VERSION 5.8 ;
BUSBITCHARS "[]" ;
DIVIDERCHAR "/" ;
UNITS
    DATABASE MICRONS 1000 ;
END UNITS

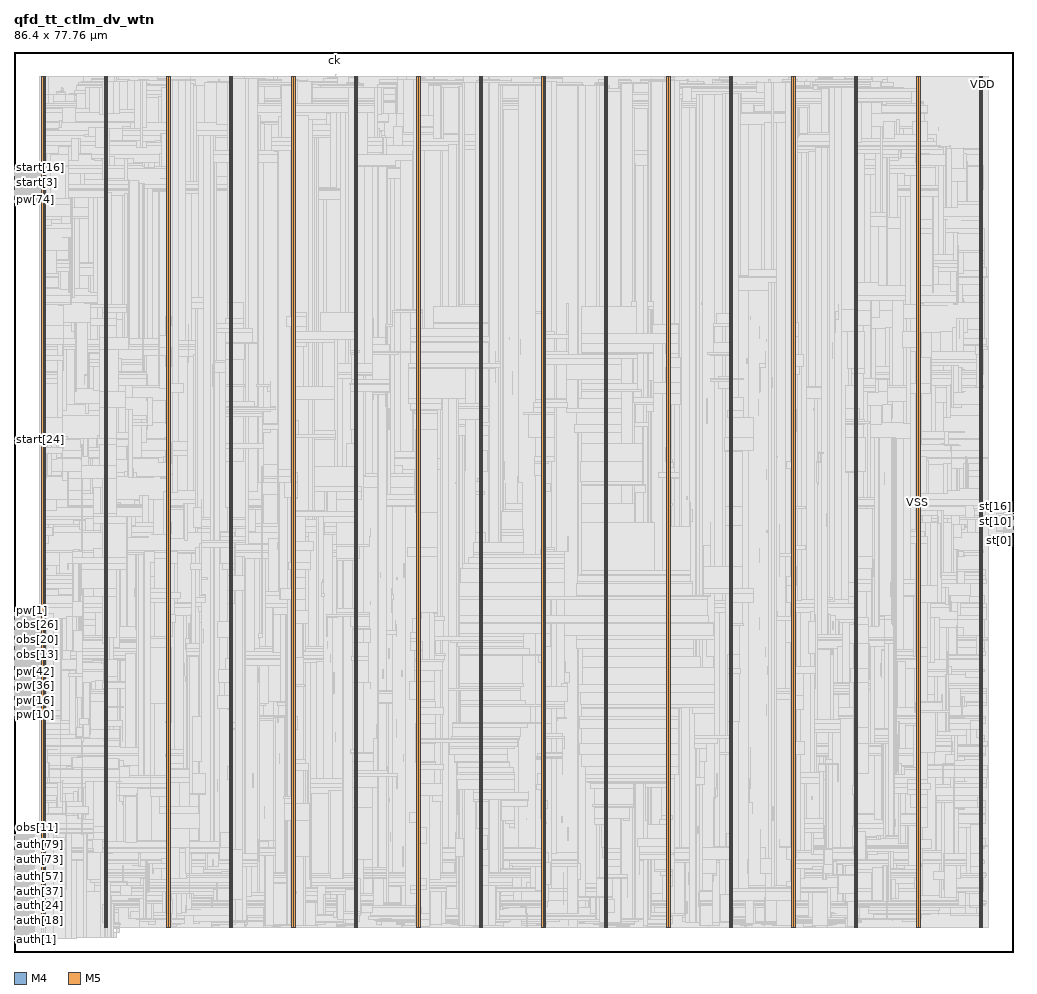
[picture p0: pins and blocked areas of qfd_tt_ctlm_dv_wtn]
MACRO qfd_tt_ctlm_dv_wtn
  FOREIGN qfd_tt_ctlm_dv_wtn 0 0 ;
  CLASS BLOCK ;
  SIZE 86.4 BY 77.76 ;
  PIN auth[0]
    DIRECTION INPUT ;
    USE SIGNAL ;
    PORT
      LAYER M4 ;
        RECT  0 1.008 0.084 1.032 ;
    END
  END auth[0]
  PIN auth[10]
    DIRECTION INPUT ;
    USE SIGNAL ;
    PORT
      LAYER M4 ;
        RECT  0 1.968 0.084 1.992 ;
    END
  END auth[10]
  PIN auth[11]
    DIRECTION INPUT ;
    USE SIGNAL ;
    PORT
      LAYER M4 ;
        RECT  0 2.064 0.084 2.088 ;
    END
  END auth[11]
  PIN auth[12]
    DIRECTION INPUT ;
    USE SIGNAL ;
    PORT
      LAYER M4 ;
        RECT  0 2.16 0.084 2.184 ;
    END
  END auth[12]
  PIN auth[13]
    DIRECTION INPUT ;
    USE SIGNAL ;
    PORT
      LAYER M4 ;
        RECT  0 2.256 0.084 2.28 ;
    END
  END auth[13]
  PIN auth[14]
    DIRECTION INPUT ;
    USE SIGNAL ;
    PORT
      LAYER M4 ;
        RECT  0 2.352 0.084 2.376 ;
    END
  END auth[14]
  PIN auth[15]
    DIRECTION INPUT ;
    USE SIGNAL ;
    PORT
      LAYER M4 ;
        RECT  0 2.448 0.084 2.472 ;
    END
  END auth[15]
  PIN auth[16]
    DIRECTION INPUT ;
    USE SIGNAL ;
    PORT
      LAYER M4 ;
        RECT  0 2.544 0.084 2.568 ;
    END
  END auth[16]
  PIN auth[17]
    DIRECTION INPUT ;
    USE SIGNAL ;
    PORT
      LAYER M4 ;
        RECT  0 2.64 0.084 2.664 ;
    END
  END auth[17]
  PIN auth[18]
    DIRECTION INPUT ;
    USE SIGNAL ;
    PORT
      LAYER M4 ;
        RECT  0 2.736 0.084 2.76 ;
    END
  END auth[18]
  PIN auth[19]
    DIRECTION INPUT ;
    USE SIGNAL ;
    PORT
      LAYER M4 ;
        RECT  0 2.832 0.084 2.856 ;
    END
  END auth[19]
  PIN auth[1]
    DIRECTION INPUT ;
    USE SIGNAL ;
    PORT
      LAYER M4 ;
        RECT  0 1.104 0.084 1.128 ;
    END
  END auth[1]
  PIN auth[20]
    DIRECTION INPUT ;
    USE SIGNAL ;
    PORT
      LAYER M4 ;
        RECT  0 2.928 0.084 2.952 ;
    END
  END auth[20]
  PIN auth[21]
    DIRECTION INPUT ;
    USE SIGNAL ;
    PORT
      LAYER M4 ;
        RECT  0 3.024 0.084 3.048 ;
    END
  END auth[21]
  PIN auth[22]
    DIRECTION INPUT ;
    USE SIGNAL ;
    PORT
      LAYER M4 ;
        RECT  0 3.12 0.084 3.144 ;
    END
  END auth[22]
  PIN auth[23]
    DIRECTION INPUT ;
    USE SIGNAL ;
    PORT
      LAYER M4 ;
        RECT  0 3.216 0.084 3.24 ;
    END
  END auth[23]
  PIN auth[24]
    DIRECTION INPUT ;
    USE SIGNAL ;
    PORT
      LAYER M4 ;
        RECT  0 3.312 0.084 3.336 ;
    END
  END auth[24]
  PIN auth[25]
    DIRECTION INPUT ;
    USE SIGNAL ;
    PORT
      LAYER M4 ;
        RECT  0 3.408 0.084 3.432 ;
    END
  END auth[25]
  PIN auth[26]
    DIRECTION INPUT ;
    USE SIGNAL ;
    PORT
      LAYER M4 ;
        RECT  0 3.504 0.084 3.528 ;
    END
  END auth[26]
  PIN auth[27]
    DIRECTION INPUT ;
    USE SIGNAL ;
    PORT
      LAYER M4 ;
        RECT  0 3.6 0.084 3.624 ;
    END
  END auth[27]
  PIN auth[28]
    DIRECTION INPUT ;
    USE SIGNAL ;
    PORT
      LAYER M4 ;
        RECT  0 3.696 0.084 3.72 ;
    END
  END auth[28]
  PIN auth[29]
    DIRECTION INPUT ;
    USE SIGNAL ;
    PORT
      LAYER M4 ;
        RECT  0 3.792 0.084 3.816 ;
    END
  END auth[29]
  PIN auth[2]
    DIRECTION INPUT ;
    USE SIGNAL ;
    PORT
      LAYER M4 ;
        RECT  0 1.2 0.084 1.224 ;
    END
  END auth[2]
  PIN auth[30]
    DIRECTION INPUT ;
    USE SIGNAL ;
    PORT
      LAYER M4 ;
        RECT  0 3.888 0.084 3.912 ;
    END
  END auth[30]
  PIN auth[31]
    DIRECTION INPUT ;
    USE SIGNAL ;
    PORT
      LAYER M4 ;
        RECT  0 3.984 0.084 4.008 ;
    END
  END auth[31]
  PIN auth[32]
    DIRECTION INPUT ;
    USE SIGNAL ;
    PORT
      LAYER M4 ;
        RECT  0 4.08 0.084 4.104 ;
    END
  END auth[32]
  PIN auth[33]
    DIRECTION INPUT ;
    USE SIGNAL ;
    PORT
      LAYER M4 ;
        RECT  0 4.176 0.084 4.2 ;
    END
  END auth[33]
  PIN auth[34]
    DIRECTION INPUT ;
    USE SIGNAL ;
    PORT
      LAYER M4 ;
        RECT  0 4.272 0.084 4.296 ;
    END
  END auth[34]
  PIN auth[35]
    DIRECTION INPUT ;
    USE SIGNAL ;
    PORT
      LAYER M4 ;
        RECT  0 4.368 0.084 4.392 ;
    END
  END auth[35]
  PIN auth[36]
    DIRECTION INPUT ;
    USE SIGNAL ;
    PORT
      LAYER M4 ;
        RECT  0 4.464 0.084 4.488 ;
    END
  END auth[36]
  PIN auth[37]
    DIRECTION INPUT ;
    USE SIGNAL ;
    PORT
      LAYER M4 ;
        RECT  0 4.56 0.084 4.584 ;
    END
  END auth[37]
  PIN auth[38]
    DIRECTION INPUT ;
    USE SIGNAL ;
    PORT
      LAYER M4 ;
        RECT  0 4.656 0.084 4.68 ;
    END
  END auth[38]
  PIN auth[39]
    DIRECTION INPUT ;
    USE SIGNAL ;
    PORT
      LAYER M4 ;
        RECT  0 4.752 0.084 4.776 ;
    END
  END auth[39]
  PIN auth[3]
    DIRECTION INPUT ;
    USE SIGNAL ;
    PORT
      LAYER M4 ;
        RECT  0 1.296 0.084 1.32 ;
    END
  END auth[3]
  PIN auth[40]
    DIRECTION INPUT ;
    USE SIGNAL ;
    PORT
      LAYER M4 ;
        RECT  0 4.848 0.084 4.872 ;
    END
  END auth[40]
  PIN auth[41]
    DIRECTION INPUT ;
    USE SIGNAL ;
    PORT
      LAYER M4 ;
        RECT  0 4.944 0.084 4.968 ;
    END
  END auth[41]
  PIN auth[42]
    DIRECTION INPUT ;
    USE SIGNAL ;
    PORT
      LAYER M4 ;
        RECT  0 5.04 0.084 5.064 ;
    END
  END auth[42]
  PIN auth[43]
    DIRECTION INPUT ;
    USE SIGNAL ;
    PORT
      LAYER M4 ;
        RECT  0 5.136 0.084 5.16 ;
    END
  END auth[43]
  PIN auth[44]
    DIRECTION INPUT ;
    USE SIGNAL ;
    PORT
      LAYER M4 ;
        RECT  0 5.232 0.084 5.256 ;
    END
  END auth[44]
  PIN auth[45]
    DIRECTION INPUT ;
    USE SIGNAL ;
    PORT
      LAYER M4 ;
        RECT  0 5.328 0.084 5.352 ;
    END
  END auth[45]
  PIN auth[46]
    DIRECTION INPUT ;
    USE SIGNAL ;
    PORT
      LAYER M4 ;
        RECT  0 5.424 0.084 5.448 ;
    END
  END auth[46]
  PIN auth[47]
    DIRECTION INPUT ;
    USE SIGNAL ;
    PORT
      LAYER M4 ;
        RECT  0 5.52 0.084 5.544 ;
    END
  END auth[47]
  PIN auth[48]
    DIRECTION INPUT ;
    USE SIGNAL ;
    PORT
      LAYER M4 ;
        RECT  0 5.616 0.084 5.64 ;
    END
  END auth[48]
  PIN auth[49]
    DIRECTION INPUT ;
    USE SIGNAL ;
    PORT
      LAYER M4 ;
        RECT  0 5.712 0.084 5.736 ;
    END
  END auth[49]
  PIN auth[4]
    DIRECTION INPUT ;
    USE SIGNAL ;
    PORT
      LAYER M4 ;
        RECT  0 1.392 0.084 1.416 ;
    END
  END auth[4]
  PIN auth[50]
    DIRECTION INPUT ;
    USE SIGNAL ;
    PORT
      LAYER M4 ;
        RECT  0 5.808 0.084 5.832 ;
    END
  END auth[50]
  PIN auth[51]
    DIRECTION INPUT ;
    USE SIGNAL ;
    PORT
      LAYER M4 ;
        RECT  0 5.904 0.084 5.928 ;
    END
  END auth[51]
  PIN auth[52]
    DIRECTION INPUT ;
    USE SIGNAL ;
    PORT
      LAYER M4 ;
        RECT  0 6 0.084 6.024 ;
    END
  END auth[52]
  PIN auth[53]
    DIRECTION INPUT ;
    USE SIGNAL ;
    PORT
      LAYER M4 ;
        RECT  0 6.096 0.084 6.12 ;
    END
  END auth[53]
  PIN auth[54]
    DIRECTION INPUT ;
    USE SIGNAL ;
    PORT
      LAYER M4 ;
        RECT  0 6.192 0.084 6.216 ;
    END
  END auth[54]
  PIN auth[55]
    DIRECTION INPUT ;
    USE SIGNAL ;
    PORT
      LAYER M4 ;
        RECT  0 6.288 0.084 6.312 ;
    END
  END auth[55]
  PIN auth[56]
    DIRECTION INPUT ;
    USE SIGNAL ;
    PORT
      LAYER M4 ;
        RECT  0 6.384 0.084 6.408 ;
    END
  END auth[56]
  PIN auth[57]
    DIRECTION INPUT ;
    USE SIGNAL ;
    PORT
      LAYER M4 ;
        RECT  0 6.48 0.084 6.504 ;
    END
  END auth[57]
  PIN auth[58]
    DIRECTION INPUT ;
    USE SIGNAL ;
    PORT
      LAYER M4 ;
        RECT  0 6.576 0.084 6.6 ;
    END
  END auth[58]
  PIN auth[59]
    DIRECTION INPUT ;
    USE SIGNAL ;
    PORT
      LAYER M4 ;
        RECT  0 6.672 0.084 6.696 ;
    END
  END auth[59]
  PIN auth[5]
    DIRECTION INPUT ;
    USE SIGNAL ;
    PORT
      LAYER M4 ;
        RECT  0 1.488 0.084 1.512 ;
    END
  END auth[5]
  PIN auth[60]
    DIRECTION INPUT ;
    USE SIGNAL ;
    PORT
      LAYER M4 ;
        RECT  0 6.768 0.084 6.792 ;
    END
  END auth[60]
  PIN auth[61]
    DIRECTION INPUT ;
    USE SIGNAL ;
    PORT
      LAYER M4 ;
        RECT  0 6.864 0.084 6.888 ;
    END
  END auth[61]
  PIN auth[62]
    DIRECTION INPUT ;
    USE SIGNAL ;
    PORT
      LAYER M4 ;
        RECT  0 6.96 0.084 6.984 ;
    END
  END auth[62]
  PIN auth[63]
    DIRECTION INPUT ;
    USE SIGNAL ;
    PORT
      LAYER M4 ;
        RECT  0 7.056 0.084 7.08 ;
    END
  END auth[63]
  PIN auth[64]
    DIRECTION INPUT ;
    USE SIGNAL ;
    PORT
      LAYER M4 ;
        RECT  0 7.152 0.084 7.176 ;
    END
  END auth[64]
  PIN auth[65]
    DIRECTION INPUT ;
    USE SIGNAL ;
    PORT
      LAYER M4 ;
        RECT  0 7.248 0.084 7.272 ;
    END
  END auth[65]
  PIN auth[66]
    DIRECTION INPUT ;
    USE SIGNAL ;
    PORT
      LAYER M4 ;
        RECT  0 7.344 0.084 7.368 ;
    END
  END auth[66]
  PIN auth[67]
    DIRECTION INPUT ;
    USE SIGNAL ;
    PORT
      LAYER M4 ;
        RECT  0 7.44 0.084 7.464 ;
    END
  END auth[67]
  PIN auth[68]
    DIRECTION INPUT ;
    USE SIGNAL ;
    PORT
      LAYER M4 ;
        RECT  0 7.536 0.084 7.56 ;
    END
  END auth[68]
  PIN auth[69]
    DIRECTION INPUT ;
    USE SIGNAL ;
    PORT
      LAYER M4 ;
        RECT  0 7.632 0.084 7.656 ;
    END
  END auth[69]
  PIN auth[6]
    DIRECTION INPUT ;
    USE SIGNAL ;
    PORT
      LAYER M4 ;
        RECT  0 1.584 0.084 1.608 ;
    END
  END auth[6]
  PIN auth[70]
    DIRECTION INPUT ;
    USE SIGNAL ;
    PORT
      LAYER M4 ;
        RECT  0 7.728 0.084 7.752 ;
    END
  END auth[70]
  PIN auth[71]
    DIRECTION INPUT ;
    USE SIGNAL ;
    PORT
      LAYER M4 ;
        RECT  0 7.824 0.084 7.848 ;
    END
  END auth[71]
  PIN auth[72]
    DIRECTION INPUT ;
    USE SIGNAL ;
    PORT
      LAYER M4 ;
        RECT  0 7.92 0.084 7.944 ;
    END
  END auth[72]
  PIN auth[73]
    DIRECTION INPUT ;
    USE SIGNAL ;
    PORT
      LAYER M4 ;
        RECT  0 8.016 0.084 8.04 ;
    END
  END auth[73]
  PIN auth[74]
    DIRECTION INPUT ;
    USE SIGNAL ;
    PORT
      LAYER M4 ;
        RECT  0 8.112 0.084 8.136 ;
    END
  END auth[74]
  PIN auth[75]
    DIRECTION INPUT ;
    USE SIGNAL ;
    PORT
      LAYER M4 ;
        RECT  0 8.208 0.084 8.232 ;
    END
  END auth[75]
  PIN auth[76]
    DIRECTION INPUT ;
    USE SIGNAL ;
    PORT
      LAYER M4 ;
        RECT  0 8.304 0.084 8.328 ;
    END
  END auth[76]
  PIN auth[77]
    DIRECTION INPUT ;
    USE SIGNAL ;
    PORT
      LAYER M4 ;
        RECT  0 8.4 0.084 8.424 ;
    END
  END auth[77]
  PIN auth[78]
    DIRECTION INPUT ;
    USE SIGNAL ;
    PORT
      LAYER M4 ;
        RECT  0 8.496 0.084 8.52 ;
    END
  END auth[78]
  PIN auth[79]
    DIRECTION INPUT ;
    USE SIGNAL ;
    PORT
      LAYER M4 ;
        RECT  0 8.592 0.084 8.616 ;
    END
  END auth[79]
  PIN auth[7]
    DIRECTION INPUT ;
    USE SIGNAL ;
    PORT
      LAYER M4 ;
        RECT  0 1.68 0.084 1.704 ;
    END
  END auth[7]
  PIN auth[80]
    DIRECTION INPUT ;
    USE SIGNAL ;
    PORT
      LAYER M4 ;
        RECT  0 8.688 0.084 8.712 ;
    END
  END auth[80]
  PIN auth[81]
    DIRECTION INPUT ;
    USE SIGNAL ;
    PORT
      LAYER M4 ;
        RECT  0 8.784 0.084 8.808 ;
    END
  END auth[81]
  PIN auth[82]
    DIRECTION INPUT ;
    USE SIGNAL ;
    PORT
      LAYER M4 ;
        RECT  0 8.88 0.084 8.904 ;
    END
  END auth[82]
  PIN auth[8]
    DIRECTION INPUT ;
    USE SIGNAL ;
    PORT
      LAYER M4 ;
        RECT  0 1.776 0.084 1.8 ;
    END
  END auth[8]
  PIN auth[9]
    DIRECTION INPUT ;
    USE SIGNAL ;
    PORT
      LAYER M4 ;
        RECT  0 1.872 0.084 1.896 ;
    END
  END auth[9]
  PIN ck
    DIRECTION INPUT ;
    USE SIGNAL ;
    PORT
      LAYER M5 ;
        RECT  27.696 77.676 27.72 77.76 ;
    END
  END ck
  PIN obs[0]
    DIRECTION INPUT ;
    USE SIGNAL ;
    PORT
      LAYER M4 ;
        RECT  0 8.976 0.084 9 ;
    END
  END obs[0]
  PIN obs[10]
    DIRECTION INPUT ;
    USE SIGNAL ;
    PORT
      LAYER M4 ;
        RECT  0 9.936 0.084 9.96 ;
    END
  END obs[10]
  PIN obs[11]
    DIRECTION INPUT ;
    USE SIGNAL ;
    PORT
      LAYER M4 ;
        RECT  0 10.032 0.084 10.056 ;
    END
  END obs[11]
  PIN obs[12]
    DIRECTION INPUT ;
    USE SIGNAL ;
    PORT
      LAYER M4 ;
        RECT  0 10.128 0.084 10.152 ;
    END
  END obs[12]
  PIN obs[13]
    DIRECTION INPUT ;
    USE SIGNAL ;
    PORT
      LAYER M4 ;
        RECT  0 26.352 0.084 26.376 ;
    END
  END obs[13]
  PIN obs[14]
    DIRECTION INPUT ;
    USE SIGNAL ;
    PORT
      LAYER M4 ;
        RECT  0 26.448 0.084 26.472 ;
    END
  END obs[14]
  PIN obs[15]
    DIRECTION INPUT ;
    USE SIGNAL ;
    PORT
      LAYER M4 ;
        RECT  0 26.544 0.084 26.568 ;
    END
  END obs[15]
  PIN obs[16]
    DIRECTION INPUT ;
    USE SIGNAL ;
    PORT
      LAYER M4 ;
        RECT  0 26.64 0.084 26.664 ;
    END
  END obs[16]
  PIN obs[17]
    DIRECTION INPUT ;
    USE SIGNAL ;
    PORT
      LAYER M4 ;
        RECT  0 26.736 0.084 26.76 ;
    END
  END obs[17]
  PIN obs[18]
    DIRECTION INPUT ;
    USE SIGNAL ;
    PORT
      LAYER M4 ;
        RECT  0 26.832 0.084 26.856 ;
    END
  END obs[18]
  PIN obs[19]
    DIRECTION INPUT ;
    USE SIGNAL ;
    PORT
      LAYER M4 ;
        RECT  0 26.928 0.084 26.952 ;
    END
  END obs[19]
  PIN obs[1]
    DIRECTION INPUT ;
    USE SIGNAL ;
    PORT
      LAYER M4 ;
        RECT  0 9.072 0.084 9.096 ;
    END
  END obs[1]
  PIN obs[20]
    DIRECTION INPUT ;
    USE SIGNAL ;
    PORT
      LAYER M4 ;
        RECT  0 27.024 0.084 27.048 ;
    END
  END obs[20]
  PIN obs[21]
    DIRECTION INPUT ;
    USE SIGNAL ;
    PORT
      LAYER M4 ;
        RECT  0 27.12 0.084 27.144 ;
    END
  END obs[21]
  PIN obs[22]
    DIRECTION INPUT ;
    USE SIGNAL ;
    PORT
      LAYER M4 ;
        RECT  0 27.216 0.084 27.24 ;
    END
  END obs[22]
  PIN obs[23]
    DIRECTION INPUT ;
    USE SIGNAL ;
    PORT
      LAYER M4 ;
        RECT  0 27.312 0.084 27.336 ;
    END
  END obs[23]
  PIN obs[24]
    DIRECTION INPUT ;
    USE SIGNAL ;
    PORT
      LAYER M4 ;
        RECT  0 27.408 0.084 27.432 ;
    END
  END obs[24]
  PIN obs[25]
    DIRECTION INPUT ;
    USE SIGNAL ;
    PORT
      LAYER M4 ;
        RECT  0 27.504 0.084 27.528 ;
    END
  END obs[25]
  PIN obs[26]
    DIRECTION INPUT ;
    USE SIGNAL ;
    PORT
      LAYER M4 ;
        RECT  0 27.6 0.084 27.624 ;
    END
  END obs[26]
  PIN obs[27]
    DIRECTION INPUT ;
    USE SIGNAL ;
    PORT
      LAYER M4 ;
        RECT  0 27.696 0.084 27.72 ;
    END
  END obs[27]
  PIN obs[28]
    DIRECTION INPUT ;
    USE SIGNAL ;
    PORT
      LAYER M4 ;
        RECT  0 27.792 0.084 27.816 ;
    END
  END obs[28]
  PIN obs[29]
    DIRECTION INPUT ;
    USE SIGNAL ;
    PORT
      LAYER M4 ;
        RECT  0 27.888 0.084 27.912 ;
    END
  END obs[29]
  PIN obs[2]
    DIRECTION INPUT ;
    USE SIGNAL ;
    PORT
      LAYER M4 ;
        RECT  0 9.168 0.084 9.192 ;
    END
  END obs[2]
  PIN obs[30]
    DIRECTION INPUT ;
    USE SIGNAL ;
    PORT
      LAYER M4 ;
        RECT  0 27.984 0.084 28.008 ;
    END
  END obs[30]
  PIN obs[31]
    DIRECTION INPUT ;
    USE SIGNAL ;
    PORT
      LAYER M4 ;
        RECT  0 28.08 0.084 28.104 ;
    END
  END obs[31]
  PIN obs[32]
    DIRECTION INPUT ;
    USE SIGNAL ;
    PORT
      LAYER M4 ;
        RECT  0 28.176 0.084 28.2 ;
    END
  END obs[32]
  PIN obs[33]
    DIRECTION INPUT ;
    USE SIGNAL ;
    PORT
      LAYER M4 ;
        RECT  0 28.272 0.084 28.296 ;
    END
  END obs[33]
  PIN obs[34]
    DIRECTION INPUT ;
    USE SIGNAL ;
    PORT
      LAYER M4 ;
        RECT  0 28.368 0.084 28.392 ;
    END
  END obs[34]
  PIN obs[35]
    DIRECTION INPUT ;
    USE SIGNAL ;
    PORT
      LAYER M4 ;
        RECT  0 28.464 0.084 28.488 ;
    END
  END obs[35]
  PIN obs[36]
    DIRECTION INPUT ;
    USE SIGNAL ;
    PORT
      LAYER M4 ;
        RECT  0 28.56 0.084 28.584 ;
    END
  END obs[36]
  PIN obs[37]
    DIRECTION INPUT ;
    USE SIGNAL ;
    PORT
      LAYER M4 ;
        RECT  0 28.656 0.084 28.68 ;
    END
  END obs[37]
  PIN obs[3]
    DIRECTION INPUT ;
    USE SIGNAL ;
    PORT
      LAYER M4 ;
        RECT  0 9.264 0.084 9.288 ;
    END
  END obs[3]
  PIN obs[4]
    DIRECTION INPUT ;
    USE SIGNAL ;
    PORT
      LAYER M4 ;
        RECT  0 9.36 0.084 9.384 ;
    END
  END obs[4]
  PIN obs[5]
    DIRECTION INPUT ;
    USE SIGNAL ;
    PORT
      LAYER M4 ;
        RECT  0 9.456 0.084 9.48 ;
    END
  END obs[5]
  PIN obs[6]
    DIRECTION INPUT ;
    USE SIGNAL ;
    PORT
      LAYER M4 ;
        RECT  0 9.552 0.084 9.576 ;
    END
  END obs[6]
  PIN obs[7]
    DIRECTION INPUT ;
    USE SIGNAL ;
    PORT
      LAYER M4 ;
        RECT  0 9.648 0.084 9.672 ;
    END
  END obs[7]
  PIN obs[8]
    DIRECTION INPUT ;
    USE SIGNAL ;
    PORT
      LAYER M4 ;
        RECT  0 9.744 0.084 9.768 ;
    END
  END obs[8]
  PIN obs[9]
    DIRECTION INPUT ;
    USE SIGNAL ;
    PORT
      LAYER M4 ;
        RECT  0 9.84 0.084 9.864 ;
    END
  END obs[9]
  PIN pw[0]
    DIRECTION INPUT ;
    USE SIGNAL ;
    PORT
      LAYER M4 ;
        RECT  0 28.752 0.084 28.776 ;
    END
  END pw[0]
  PIN pw[10]
    DIRECTION INPUT ;
    USE SIGNAL ;
    PORT
      LAYER M4 ;
        RECT  0 20.496 0.084 20.52 ;
    END
  END pw[10]
  PIN pw[11]
    DIRECTION INPUT ;
    USE SIGNAL ;
    PORT
      LAYER M4 ;
        RECT  0 20.592 0.084 20.616 ;
    END
  END pw[11]
  PIN pw[12]
    DIRECTION INPUT ;
    USE SIGNAL ;
    PORT
      LAYER M4 ;
        RECT  0 20.688 0.084 20.712 ;
    END
  END pw[12]
  PIN pw[13]
    DIRECTION INPUT ;
    USE SIGNAL ;
    PORT
      LAYER M4 ;
        RECT  0 20.784 0.084 20.808 ;
    END
  END pw[13]
  PIN pw[14]
    DIRECTION INPUT ;
    USE SIGNAL ;
    PORT
      LAYER M4 ;
        RECT  0 20.88 0.084 20.904 ;
    END
  END pw[14]
  PIN pw[15]
    DIRECTION INPUT ;
    USE SIGNAL ;
    PORT
      LAYER M4 ;
        RECT  0 20.976 0.084 21 ;
    END
  END pw[15]
  PIN pw[16]
    DIRECTION INPUT ;
    USE SIGNAL ;
    PORT
      LAYER M4 ;
        RECT  0 21.072 0.084 21.096 ;
    END
  END pw[16]
  PIN pw[17]
    DIRECTION INPUT ;
    USE SIGNAL ;
    PORT
      LAYER M4 ;
        RECT  0 21.168 0.084 21.192 ;
    END
  END pw[17]
  PIN pw[18]
    DIRECTION INPUT ;
    USE SIGNAL ;
    PORT
      LAYER M4 ;
        RECT  0 21.264 0.084 21.288 ;
    END
  END pw[18]
  PIN pw[19]
    DIRECTION INPUT ;
    USE SIGNAL ;
    PORT
      LAYER M4 ;
        RECT  0 21.36 0.084 21.384 ;
    END
  END pw[19]
  PIN pw[1]
    DIRECTION INPUT ;
    USE SIGNAL ;
    PORT
      LAYER M4 ;
        RECT  0 28.848 0.084 28.872 ;
    END
  END pw[1]
  PIN pw[20]
    DIRECTION INPUT ;
    USE SIGNAL ;
    PORT
      LAYER M4 ;
        RECT  0 21.456 0.084 21.48 ;
    END
  END pw[20]
  PIN pw[21]
    DIRECTION INPUT ;
    USE SIGNAL ;
    PORT
      LAYER M4 ;
        RECT  0 21.552 0.084 21.576 ;
    END
  END pw[21]
  PIN pw[22]
    DIRECTION INPUT ;
    USE SIGNAL ;
    PORT
      LAYER M4 ;
        RECT  0 21.648 0.084 21.672 ;
    END
  END pw[22]
  PIN pw[23]
    DIRECTION INPUT ;
    USE SIGNAL ;
    PORT
      LAYER M4 ;
        RECT  0 21.744 0.084 21.768 ;
    END
  END pw[23]
  PIN pw[24]
    DIRECTION INPUT ;
    USE SIGNAL ;
    PORT
      LAYER M4 ;
        RECT  0 21.84 0.084 21.864 ;
    END
  END pw[24]
  PIN pw[25]
    DIRECTION INPUT ;
    USE SIGNAL ;
    PORT
      LAYER M4 ;
        RECT  0 21.936 0.084 21.96 ;
    END
  END pw[25]
  PIN pw[26]
    DIRECTION INPUT ;
    USE SIGNAL ;
    PORT
      LAYER M4 ;
        RECT  0 22.032 0.084 22.056 ;
    END
  END pw[26]
  PIN pw[27]
    DIRECTION INPUT ;
    USE SIGNAL ;
    PORT
      LAYER M4 ;
        RECT  0 22.128 0.084 22.152 ;
    END
  END pw[27]
  PIN pw[28]
    DIRECTION INPUT ;
    USE SIGNAL ;
    PORT
      LAYER M4 ;
        RECT  0 22.224 0.084 22.248 ;
    END
  END pw[28]
  PIN pw[29]
    DIRECTION INPUT ;
    USE SIGNAL ;
    PORT
      LAYER M4 ;
        RECT  0 22.32 0.084 22.344 ;
    END
  END pw[29]
  PIN pw[2]
    DIRECTION INPUT ;
    USE SIGNAL ;
    PORT
      LAYER M4 ;
        RECT  0 28.944 0.084 28.968 ;
    END
  END pw[2]
  PIN pw[30]
    DIRECTION INPUT ;
    USE SIGNAL ;
    PORT
      LAYER M4 ;
        RECT  0 22.416 0.084 22.44 ;
    END
  END pw[30]
  PIN pw[31]
    DIRECTION INPUT ;
    USE SIGNAL ;
    PORT
      LAYER M4 ;
        RECT  0 22.512 0.084 22.536 ;
    END
  END pw[31]
  PIN pw[32]
    DIRECTION INPUT ;
    USE SIGNAL ;
    PORT
      LAYER M4 ;
        RECT  0 22.608 0.084 22.632 ;
    END
  END pw[32]
  PIN pw[33]
    DIRECTION INPUT ;
    USE SIGNAL ;
    PORT
      LAYER M4 ;
        RECT  0 22.704 0.084 22.728 ;
    END
  END pw[33]
  PIN pw[34]
    DIRECTION INPUT ;
    USE SIGNAL ;
    PORT
      LAYER M4 ;
        RECT  0 22.8 0.084 22.824 ;
    END
  END pw[34]
  PIN pw[35]
    DIRECTION INPUT ;
    USE SIGNAL ;
    PORT
      LAYER M4 ;
        RECT  0 22.896 0.084 22.92 ;
    END
  END pw[35]
  PIN pw[36]
    DIRECTION INPUT ;
    USE SIGNAL ;
    PORT
      LAYER M4 ;
        RECT  0 22.992 0.084 23.016 ;
    END
  END pw[36]
  PIN pw[37]
    DIRECTION INPUT ;
    USE SIGNAL ;
    PORT
      LAYER M4 ;
        RECT  0 23.088 0.084 23.112 ;
    END
  END pw[37]
  PIN pw[38]
    DIRECTION INPUT ;
    USE SIGNAL ;
    PORT
      LAYER M4 ;
        RECT  0 23.184 0.084 23.208 ;
    END
  END pw[38]
  PIN pw[39]
    DIRECTION INPUT ;
    USE SIGNAL ;
    PORT
      LAYER M4 ;
        RECT  0 23.28 0.084 23.304 ;
    END
  END pw[39]
  PIN pw[3]
    DIRECTION INPUT ;
    USE SIGNAL ;
    PORT
      LAYER M4 ;
        RECT  0 29.04 0.084 29.064 ;
    END
  END pw[3]
  PIN pw[40]
    DIRECTION INPUT ;
    USE SIGNAL ;
    PORT
      LAYER M4 ;
        RECT  0 23.376 0.084 23.4 ;
    END
  END pw[40]
  PIN pw[41]
    DIRECTION INPUT ;
    USE SIGNAL ;
    PORT
      LAYER M4 ;
        RECT  0 23.472 0.084 23.496 ;
    END
  END pw[41]
  PIN pw[42]
    DIRECTION INPUT ;
    USE SIGNAL ;
    PORT
      LAYER M4 ;
        RECT  0 23.568 0.084 23.592 ;
    END
  END pw[42]
  PIN pw[43]
    DIRECTION INPUT ;
    USE SIGNAL ;
    PORT
      LAYER M4 ;
        RECT  0 23.664 0.084 23.688 ;
    END
  END pw[43]
  PIN pw[44]
    DIRECTION INPUT ;
    USE SIGNAL ;
    PORT
      LAYER M4 ;
        RECT  0 23.76 0.084 23.784 ;
    END
  END pw[44]
  PIN pw[45]
    DIRECTION INPUT ;
    USE SIGNAL ;
    PORT
      LAYER M4 ;
        RECT  0 23.856 0.084 23.88 ;
    END
  END pw[45]
  PIN pw[46]
    DIRECTION INPUT ;
    USE SIGNAL ;
    PORT
      LAYER M4 ;
        RECT  0 23.952 0.084 23.976 ;
    END
  END pw[46]
  PIN pw[47]
    DIRECTION INPUT ;
    USE SIGNAL ;
    PORT
      LAYER M4 ;
        RECT  0 24.048 0.084 24.072 ;
    END
  END pw[47]
  PIN pw[48]
    DIRECTION INPUT ;
    USE SIGNAL ;
    PORT
      LAYER M4 ;
        RECT  0 24.144 0.084 24.168 ;
    END
  END pw[48]
  PIN pw[49]
    DIRECTION INPUT ;
    USE SIGNAL ;
    PORT
      LAYER M4 ;
        RECT  0 24.24 0.084 24.264 ;
    END
  END pw[49]
  PIN pw[4]
    DIRECTION INPUT ;
    USE SIGNAL ;
    PORT
      LAYER M4 ;
        RECT  0 29.136 0.084 29.16 ;
    END
  END pw[4]
  PIN pw[50]
    DIRECTION INPUT ;
    USE SIGNAL ;
    PORT
      LAYER M4 ;
        RECT  0 24.336 0.084 24.36 ;
    END
  END pw[50]
  PIN pw[51]
    DIRECTION INPUT ;
    USE SIGNAL ;
    PORT
      LAYER M4 ;
        RECT  0 24.432 0.084 24.456 ;
    END
  END pw[51]
  PIN pw[52]
    DIRECTION INPUT ;
    USE SIGNAL ;
    PORT
      LAYER M4 ;
        RECT  0 24.528 0.084 24.552 ;
    END
  END pw[52]
  PIN pw[53]
    DIRECTION INPUT ;
    USE SIGNAL ;
    PORT
      LAYER M4 ;
        RECT  0 24.624 0.084 24.648 ;
    END
  END pw[53]
  PIN pw[54]
    DIRECTION INPUT ;
    USE SIGNAL ;
    PORT
      LAYER M4 ;
        RECT  0 24.72 0.084 24.744 ;
    END
  END pw[54]
  PIN pw[55]
    DIRECTION INPUT ;
    USE SIGNAL ;
    PORT
      LAYER M4 ;
        RECT  0 24.816 0.084 24.84 ;
    END
  END pw[55]
  PIN pw[56]
    DIRECTION INPUT ;
    USE SIGNAL ;
    PORT
      LAYER M4 ;
        RECT  0 24.912 0.084 24.936 ;
    END
  END pw[56]
  PIN pw[57]
    DIRECTION INPUT ;
    USE SIGNAL ;
    PORT
      LAYER M4 ;
        RECT  0 25.008 0.084 25.032 ;
    END
  END pw[57]
  PIN pw[58]
    DIRECTION INPUT ;
    USE SIGNAL ;
    PORT
      LAYER M4 ;
        RECT  0 25.104 0.084 25.128 ;
    END
  END pw[58]
  PIN pw[59]
    DIRECTION INPUT ;
    USE SIGNAL ;
    PORT
      LAYER M4 ;
        RECT  0 25.2 0.084 25.224 ;
    END
  END pw[59]
  PIN pw[5]
    DIRECTION INPUT ;
    USE SIGNAL ;
    PORT
      LAYER M4 ;
        RECT  0 29.232 0.084 29.256 ;
    END
  END pw[5]
  PIN pw[60]
    DIRECTION INPUT ;
    USE SIGNAL ;
    PORT
      LAYER M4 ;
        RECT  0 25.296 0.084 25.32 ;
    END
  END pw[60]
  PIN pw[61]
    DIRECTION INPUT ;
    USE SIGNAL ;
    PORT
      LAYER M4 ;
        RECT  0 25.392 0.084 25.416 ;
    END
  END pw[61]
  PIN pw[62]
    DIRECTION INPUT ;
    USE SIGNAL ;
    PORT
      LAYER M4 ;
        RECT  0 25.488 0.084 25.512 ;
    END
  END pw[62]
  PIN pw[63]
    DIRECTION INPUT ;
    USE SIGNAL ;
    PORT
      LAYER M4 ;
        RECT  0 25.584 0.084 25.608 ;
    END
  END pw[63]
  PIN pw[64]
    DIRECTION INPUT ;
    USE SIGNAL ;
    PORT
      LAYER M4 ;
        RECT  0 25.68 0.084 25.704 ;
    END
  END pw[64]
  PIN pw[65]
    DIRECTION INPUT ;
    USE SIGNAL ;
    PORT
      LAYER M4 ;
        RECT  0 25.776 0.084 25.8 ;
    END
  END pw[65]
  PIN pw[66]
    DIRECTION INPUT ;
    USE SIGNAL ;
    PORT
      LAYER M4 ;
        RECT  0 25.872 0.084 25.896 ;
    END
  END pw[66]
  PIN pw[67]
    DIRECTION INPUT ;
    USE SIGNAL ;
    PORT
      LAYER M4 ;
        RECT  0 25.968 0.084 25.992 ;
    END
  END pw[67]
  PIN pw[68]
    DIRECTION INPUT ;
    USE SIGNAL ;
    PORT
      LAYER M4 ;
        RECT  0 26.064 0.084 26.088 ;
    END
  END pw[68]
  PIN pw[69]
    DIRECTION INPUT ;
    USE SIGNAL ;
    PORT
      LAYER M4 ;
        RECT  0 26.16 0.084 26.184 ;
    END
  END pw[69]
  PIN pw[6]
    DIRECTION INPUT ;
    USE SIGNAL ;
    PORT
      LAYER M4 ;
        RECT  0 29.328 0.084 29.352 ;
    END
  END pw[6]
  PIN pw[70]
    DIRECTION INPUT ;
    USE SIGNAL ;
    PORT
      LAYER M4 ;
        RECT  0 26.256 0.084 26.28 ;
    END
  END pw[70]
  PIN pw[71]
    DIRECTION INPUT ;
    USE SIGNAL ;
    PORT
      LAYER M4 ;
        RECT  0 64.752 0.084 64.776 ;
    END
  END pw[71]
  PIN pw[72]
    DIRECTION INPUT ;
    USE SIGNAL ;
    PORT
      LAYER M4 ;
        RECT  0 64.848 0.084 64.872 ;
    END
  END pw[72]
  PIN pw[73]
    DIRECTION INPUT ;
    USE SIGNAL ;
    PORT
      LAYER M4 ;
        RECT  0 64.944 0.084 64.968 ;
    END
  END pw[73]
  PIN pw[74]
    DIRECTION INPUT ;
    USE SIGNAL ;
    PORT
      LAYER M4 ;
        RECT  0 65.04 0.084 65.064 ;
    END
  END pw[74]
  PIN pw[7]
    DIRECTION INPUT ;
    USE SIGNAL ;
    PORT
      LAYER M4 ;
        RECT  0 20.208 0.084 20.232 ;
    END
  END pw[7]
  PIN pw[8]
    DIRECTION INPUT ;
    USE SIGNAL ;
    PORT
      LAYER M4 ;
        RECT  0 20.304 0.084 20.328 ;
    END
  END pw[8]
  PIN pw[9]
    DIRECTION INPUT ;
    USE SIGNAL ;
    PORT
      LAYER M4 ;
        RECT  0 20.4 0.084 20.424 ;
    END
  END pw[9]
  PIN retire[0]
    DIRECTION INPUT ;
    USE SIGNAL ;
    PORT
      LAYER M4 ;
        RECT  0 65.136 0.084 65.16 ;
    END
  END retire[0]
  PIN retire[1]
    DIRECTION INPUT ;
    USE SIGNAL ;
    PORT
      LAYER M4 ;
        RECT  0 65.232 0.084 65.256 ;
    END
  END retire[1]
  PIN retire[2]
    DIRECTION INPUT ;
    USE SIGNAL ;
    PORT
      LAYER M4 ;
        RECT  0 65.328 0.084 65.352 ;
    END
  END retire[2]
  PIN retire[3]
    DIRECTION INPUT ;
    USE SIGNAL ;
    PORT
      LAYER M4 ;
        RECT  0 65.424 0.084 65.448 ;
    END
  END retire[3]
  PIN rst_n
    DIRECTION INPUT ;
    USE SIGNAL ;
    PORT
      LAYER M5 ;
        RECT  27.792 77.676 27.816 77.76 ;
    END
  END rst_n
  PIN st[0]
    DIRECTION OUTPUT ;
    USE SIGNAL ;
    PORT
      LAYER M4 ;
        RECT  86.316 36.24 86.4 36.264 ;
    END
  END st[0]
  PIN st[10]
    DIRECTION OUTPUT ;
    USE SIGNAL ;
    PORT
      LAYER M4 ;
        RECT  86.316 37.2 86.4 37.224 ;
    END
  END st[10]
  PIN st[11]
    DIRECTION OUTPUT ;
    USE SIGNAL ;
    PORT
      LAYER M4 ;
        RECT  86.316 37.296 86.4 37.32 ;
    END
  END st[11]
  PIN st[12]
    DIRECTION OUTPUT ;
    USE SIGNAL ;
    PORT
      LAYER M4 ;
        RECT  86.316 37.392 86.4 37.416 ;
    END
  END st[12]
  PIN st[13]
    DIRECTION OUTPUT ;
    USE SIGNAL ;
    PORT
      LAYER M4 ;
        RECT  86.316 37.488 86.4 37.512 ;
    END
  END st[13]
  PIN st[14]
    DIRECTION OUTPUT ;
    USE SIGNAL ;
    PORT
      LAYER M4 ;
        RECT  86.316 37.584 86.4 37.608 ;
    END
  END st[14]
  PIN st[15]
    DIRECTION OUTPUT ;
    USE SIGNAL ;
    PORT
      LAYER M4 ;
        RECT  86.316 37.68 86.4 37.704 ;
    END
  END st[15]
  PIN st[16]
    DIRECTION OUTPUT ;
    USE SIGNAL ;
    PORT
      LAYER M4 ;
        RECT  86.316 37.776 86.4 37.8 ;
    END
  END st[16]
  PIN st[1]
    DIRECTION OUTPUT ;
    USE SIGNAL ;
    PORT
      LAYER M4 ;
        RECT  86.316 36.336 86.4 36.36 ;
    END
  END st[1]
  PIN st[2]
    DIRECTION OUTPUT ;
    USE SIGNAL ;
    PORT
      LAYER M4 ;
        RECT  86.316 36.432 86.4 36.456 ;
    END
  END st[2]
  PIN st[3]
    DIRECTION OUTPUT ;
    USE SIGNAL ;
    PORT
      LAYER M4 ;
        RECT  86.316 36.528 86.4 36.552 ;
    END
  END st[3]
  PIN st[4]
    DIRECTION OUTPUT ;
    USE SIGNAL ;
    PORT
      LAYER M4 ;
        RECT  86.316 36.624 86.4 36.648 ;
    END
  END st[4]
  PIN st[5]
    DIRECTION OUTPUT ;
    USE SIGNAL ;
    PORT
      LAYER M4 ;
        RECT  86.316 36.72 86.4 36.744 ;
    END
  END st[5]
  PIN st[6]
    DIRECTION OUTPUT ;
    USE SIGNAL ;
    PORT
      LAYER M4 ;
        RECT  86.316 36.816 86.4 36.84 ;
    END
  END st[6]
  PIN st[7]
    DIRECTION OUTPUT ;
    USE SIGNAL ;
    PORT
      LAYER M4 ;
        RECT  86.316 36.912 86.4 36.936 ;
    END
  END st[7]
  PIN st[8]
    DIRECTION OUTPUT ;
    USE SIGNAL ;
    PORT
      LAYER M4 ;
        RECT  86.316 37.008 86.4 37.032 ;
    END
  END st[8]
  PIN st[9]
    DIRECTION OUTPUT ;
    USE SIGNAL ;
    PORT
      LAYER M4 ;
        RECT  86.316 37.104 86.4 37.128 ;
    END
  END st[9]
  PIN start[0]
    DIRECTION INPUT ;
    USE SIGNAL ;
    PORT
      LAYER M4 ;
        RECT  0 65.52 0.084 65.544 ;
    END
  END start[0]
  PIN start[10]
    DIRECTION INPUT ;
    USE SIGNAL ;
    PORT
      LAYER M4 ;
        RECT  0 66.48 0.084 66.504 ;
    END
  END start[10]
  PIN start[11]
    DIRECTION INPUT ;
    USE SIGNAL ;
    PORT
      LAYER M4 ;
        RECT  0 66.576 0.084 66.6 ;
    END
  END start[11]
  PIN start[12]
    DIRECTION INPUT ;
    USE SIGNAL ;
    PORT
      LAYER M4 ;
        RECT  0 66.672 0.084 66.696 ;
    END
  END start[12]
  PIN start[13]
    DIRECTION INPUT ;
    USE SIGNAL ;
    PORT
      LAYER M4 ;
        RECT  0 66.768 0.084 66.792 ;
    END
  END start[13]
  PIN start[14]
    DIRECTION INPUT ;
    USE SIGNAL ;
    PORT
      LAYER M4 ;
        RECT  0 66.864 0.084 66.888 ;
    END
  END start[14]
  PIN start[15]
    DIRECTION INPUT ;
    USE SIGNAL ;
    PORT
      LAYER M4 ;
        RECT  0 66.96 0.084 66.984 ;
    END
  END start[15]
  PIN start[16]
    DIRECTION INPUT ;
    USE SIGNAL ;
    PORT
      LAYER M4 ;
        RECT  0 67.056 0.084 67.08 ;
    END
  END start[16]
  PIN start[17]
    DIRECTION INPUT ;
    USE SIGNAL ;
    PORT
      LAYER M4 ;
        RECT  0 67.152 0.084 67.176 ;
    END
  END start[17]
  PIN start[18]
    DIRECTION INPUT ;
    USE SIGNAL ;
    PORT
      LAYER M4 ;
        RECT  0 67.248 0.084 67.272 ;
    END
  END start[18]
  PIN start[19]
    DIRECTION INPUT ;
    USE SIGNAL ;
    PORT
      LAYER M4 ;
        RECT  0 67.344 0.084 67.368 ;
    END
  END start[19]
  PIN start[1]
    DIRECTION INPUT ;
    USE SIGNAL ;
    PORT
      LAYER M4 ;
        RECT  0 65.616 0.084 65.64 ;
    END
  END start[1]
  PIN start[20]
    DIRECTION INPUT ;
    USE SIGNAL ;
    PORT
      LAYER M4 ;
        RECT  0 67.44 0.084 67.464 ;
    END
  END start[20]
  PIN start[21]
    DIRECTION INPUT ;
    USE SIGNAL ;
    PORT
      LAYER M4 ;
        RECT  0 67.536 0.084 67.56 ;
    END
  END start[21]
  PIN start[22]
    DIRECTION INPUT ;
    USE SIGNAL ;
    PORT
      LAYER M4 ;
        RECT  0 67.632 0.084 67.656 ;
    END
  END start[22]
  PIN start[23]
    DIRECTION INPUT ;
    USE SIGNAL ;
    PORT
      LAYER M4 ;
        RECT  0 67.728 0.084 67.752 ;
    END
  END start[23]
  PIN start[24]
    DIRECTION INPUT ;
    USE SIGNAL ;
    PORT
      LAYER M4 ;
        RECT  0 44.304 0.084 44.328 ;
    END
    PORT
      LAYER M4 ;
        RECT  0.06 44.304 2.408 44.328 ;
    END
  END start[24]
  PIN start[2]
    DIRECTION INPUT ;
    USE SIGNAL ;
    PORT
      LAYER M4 ;
        RECT  0 65.712 0.084 65.736 ;
    END
  END start[2]
  PIN start[3]
    DIRECTION INPUT ;
    USE SIGNAL ;
    PORT
      LAYER M4 ;
        RECT  0 65.808 0.084 65.832 ;
    END
  END start[3]
  PIN start[4]
    DIRECTION INPUT ;
    USE SIGNAL ;
    PORT
      LAYER M4 ;
        RECT  0 65.904 0.084 65.928 ;
    END
  END start[4]
  PIN start[5]
    DIRECTION INPUT ;
    USE SIGNAL ;
    PORT
      LAYER M4 ;
        RECT  0 66 0.084 66.024 ;
    END
  END start[5]
  PIN start[6]
    DIRECTION INPUT ;
    USE SIGNAL ;
    PORT
      LAYER M4 ;
        RECT  0 66.096 0.084 66.12 ;
    END
  END start[6]
  PIN start[7]
    DIRECTION INPUT ;
    USE SIGNAL ;
    PORT
      LAYER M4 ;
        RECT  0 66.192 0.084 66.216 ;
    END
  END start[7]
  PIN start[8]
    DIRECTION INPUT ;
    USE SIGNAL ;
    PORT
      LAYER M4 ;
        RECT  0 66.288 0.084 66.312 ;
    END
  END start[8]
  PIN start[9]
    DIRECTION INPUT ;
    USE SIGNAL ;
    PORT
      LAYER M4 ;
        RECT  0 66.384 0.084 66.408 ;
    END
  END start[9]
  PIN VDD
    DIRECTION INOUT ;
    USE POWER ;
    PORT
      LAYER M5 ;
        RECT  83.592 2.151 83.712 75.609 ;
        RECT  78.192 2.151 78.312 75.609 ;
        RECT  72.792 2.151 72.912 75.609 ;
        RECT  67.392 2.151 67.512 75.609 ;
        RECT  61.992 2.151 62.112 75.609 ;
        RECT  56.592 2.151 56.712 75.609 ;
        RECT  51.192 2.151 51.312 75.609 ;
        RECT  45.792 2.151 45.912 75.609 ;
        RECT  40.392 2.151 40.512 75.609 ;
        RECT  34.992 2.151 35.112 75.609 ;
        RECT  29.592 2.151 29.712 75.609 ;
        RECT  24.192 2.151 24.312 75.609 ;
        RECT  18.792 2.151 18.912 75.609 ;
        RECT  13.392 2.151 13.512 75.609 ;
        RECT  7.992 2.151 8.112 75.609 ;
        RECT  2.592 2.151 2.712 75.609 ;
    END
  END VDD
  PIN VSS
    DIRECTION INOUT ;
    USE GROUND ;
    PORT
      LAYER M5 ;
        RECT  83.4 2.137 83.52 75.623 ;
        RECT  78 2.137 78.12 75.623 ;
        RECT  72.6 2.137 72.72 75.623 ;
        RECT  67.2 2.137 67.32 75.623 ;
        RECT  61.8 2.137 61.92 75.623 ;
        RECT  56.4 2.137 56.52 75.623 ;
        RECT  51 2.137 51.12 75.623 ;
        RECT  45.6 2.137 45.72 75.623 ;
        RECT  40.2 2.137 40.32 75.623 ;
        RECT  34.8 2.137 34.92 75.623 ;
        RECT  29.4 2.137 29.52 75.623 ;
        RECT  24 2.137 24.12 75.623 ;
        RECT  18.6 2.137 18.72 75.623 ;
        RECT  13.2 2.137 13.32 75.623 ;
        RECT  7.8 2.137 7.92 75.623 ;
        RECT  2.4 2.137 2.52 75.623 ;
    END
  END VSS
  # OT_OBS_CLOSED layer=M5 d_um=1.536 added=723
  OBS
    LAYER RVTN ;
     RECT  2.16 2.16 84.24 2.295 ;
     RECT  2.16 2.565 84.24 2.835 ;
     RECT  2.16 3.105 84.24 3.375 ;
     RECT  2.16 3.645 84.24 3.915 ;
     RECT  2.16 4.185 84.24 4.455 ;
     RECT  2.16 4.725 84.24 4.995 ;
     RECT  2.16 5.265 84.24 5.535 ;
     RECT  2.16 5.805 84.24 6.075 ;
     RECT  2.16 6.345 84.24 6.615 ;
     RECT  2.16 6.885 84.24 7.155 ;
     RECT  2.16 7.425 84.24 7.695 ;
     RECT  2.16 7.965 84.24 8.235 ;
     RECT  2.16 8.505 84.24 8.775 ;
     RECT  2.16 9.045 84.24 9.315 ;
     RECT  2.16 9.585 84.24 9.855 ;
     RECT  2.16 10.125 84.24 10.395 ;
     RECT  2.16 10.665 84.24 10.935 ;
     RECT  2.16 11.205 84.24 11.475 ;
     RECT  2.16 11.745 84.24 12.015 ;
     RECT  2.16 12.285 84.24 12.555 ;
     RECT  2.16 12.825 84.24 13.095 ;
     RECT  2.16 13.365 84.24 13.635 ;
     RECT  2.16 13.905 84.24 14.175 ;
     RECT  2.16 14.445 84.24 14.715 ;
     RECT  2.16 14.985 84.24 15.255 ;
     RECT  2.16 15.525 84.24 15.795 ;
     RECT  2.16 16.065 84.24 16.335 ;
     RECT  2.16 16.605 84.24 16.875 ;
     RECT  2.16 17.145 84.24 17.415 ;
     RECT  2.16 17.685 84.24 17.955 ;
     RECT  2.16 18.225 84.24 18.495 ;
     RECT  2.16 18.765 84.24 19.035 ;
     RECT  2.16 19.305 84.24 19.575 ;
     RECT  2.16 19.845 84.24 20.115 ;
     RECT  2.16 20.385 84.24 20.655 ;
     RECT  2.16 20.925 84.24 21.195 ;
     RECT  2.16 21.465 84.24 21.735 ;
     RECT  2.16 22.005 84.24 22.275 ;
     RECT  2.16 22.545 84.24 22.815 ;
     RECT  2.16 23.085 84.24 23.355 ;
     RECT  2.16 23.625 84.24 23.895 ;
     RECT  2.16 24.165 84.24 24.435 ;
     RECT  2.16 24.705 84.24 24.975 ;
     RECT  2.16 25.245 84.24 25.515 ;
     RECT  2.16 25.785 84.24 26.055 ;
     RECT  2.16 26.325 84.24 26.595 ;
     RECT  2.16 26.865 84.24 27.135 ;
     RECT  2.16 27.405 84.24 27.675 ;
     RECT  2.16 27.945 84.24 28.215 ;
     RECT  2.16 28.485 84.24 28.755 ;
     RECT  2.16 29.025 84.24 29.295 ;
     RECT  2.16 29.565 84.24 29.835 ;
     RECT  2.16 30.105 84.24 30.375 ;
     RECT  2.16 30.645 84.24 30.915 ;
     RECT  2.16 31.185 84.24 31.455 ;
     RECT  2.16 31.725 84.24 31.995 ;
     RECT  2.16 32.265 84.24 32.535 ;
     RECT  2.16 32.805 84.24 33.075 ;
     RECT  2.16 33.345 84.24 33.615 ;
     RECT  2.16 33.885 84.24 34.155 ;
     RECT  2.16 34.425 84.24 34.695 ;
     RECT  2.16 34.965 84.24 35.235 ;
     RECT  2.16 35.505 84.24 35.775 ;
     RECT  2.16 36.045 84.24 36.315 ;
     RECT  2.16 36.585 84.24 36.855 ;
     RECT  2.16 37.125 84.24 37.395 ;
     RECT  2.16 37.665 84.24 37.935 ;
     RECT  2.16 38.205 84.24 38.475 ;
     RECT  2.16 38.745 84.24 39.015 ;
     RECT  2.16 39.285 84.24 39.555 ;
     RECT  2.16 39.825 84.24 40.095 ;
     RECT  2.16 40.365 84.24 40.635 ;
     RECT  2.16 40.905 84.24 41.175 ;
     RECT  2.16 41.445 84.24 41.715 ;
     RECT  2.16 41.985 84.24 42.255 ;
     RECT  2.16 42.525 84.24 42.795 ;
     RECT  2.16 43.065 84.24 43.335 ;
     RECT  2.16 43.605 84.24 43.875 ;
     RECT  2.16 44.145 84.24 44.415 ;
     RECT  2.16 44.685 84.24 44.955 ;
     RECT  2.16 45.225 84.24 45.495 ;
     RECT  2.16 45.765 84.24 46.035 ;
     RECT  2.16 46.305 84.24 46.575 ;
     RECT  2.16 46.845 84.24 47.115 ;
     RECT  2.16 47.385 84.24 47.655 ;
     RECT  2.16 47.925 84.24 48.195 ;
     RECT  2.16 48.465 84.24 48.735 ;
     RECT  2.16 49.005 84.24 49.275 ;
     RECT  2.16 49.545 84.24 49.815 ;
     RECT  2.16 50.085 84.24 50.355 ;
     RECT  2.16 50.625 84.24 50.895 ;
     RECT  2.16 51.165 84.24 51.435 ;
     RECT  2.16 51.705 84.24 51.975 ;
     RECT  2.16 52.245 84.24 52.515 ;
     RECT  2.16 52.785 84.24 53.055 ;
     RECT  2.16 53.325 84.24 53.595 ;
     RECT  2.16 53.865 84.24 54.135 ;
     RECT  2.16 54.405 84.24 54.675 ;
     RECT  2.16 54.945 84.24 55.215 ;
     RECT  2.16 55.485 84.24 55.755 ;
     RECT  2.16 56.025 84.24 56.295 ;
     RECT  2.16 56.565 84.24 56.835 ;
     RECT  2.16 57.105 84.24 57.375 ;
     RECT  2.16 57.645 84.24 57.915 ;
     RECT  2.16 58.185 84.24 58.455 ;
     RECT  2.16 58.725 84.24 58.995 ;
     RECT  2.16 59.265 84.24 59.535 ;
     RECT  2.16 59.805 84.24 60.075 ;
     RECT  2.16 60.345 84.24 60.615 ;
     RECT  2.16 60.885 84.24 61.155 ;
     RECT  2.16 61.425 84.24 61.695 ;
     RECT  2.16 61.965 84.24 62.235 ;
     RECT  2.16 62.505 84.24 62.775 ;
     RECT  2.16 63.045 84.24 63.315 ;
     RECT  2.16 63.585 84.24 63.855 ;
     RECT  2.16 64.125 84.24 64.395 ;
     RECT  2.16 64.665 84.24 64.935 ;
     RECT  2.16 65.205 84.24 65.475 ;
     RECT  2.16 65.745 84.24 66.015 ;
     RECT  2.16 66.285 84.24 66.555 ;
     RECT  2.16 66.825 84.24 67.095 ;
     RECT  2.16 67.365 84.24 67.635 ;
     RECT  2.16 67.905 84.24 68.175 ;
     RECT  2.16 68.445 84.24 68.715 ;
     RECT  2.16 68.985 84.24 69.255 ;
     RECT  2.16 69.525 84.24 69.795 ;
     RECT  2.16 70.065 84.24 70.335 ;
     RECT  2.16 70.605 84.24 70.875 ;
     RECT  2.16 71.145 84.24 71.415 ;
     RECT  2.16 71.685 84.24 71.955 ;
     RECT  2.16 72.225 84.24 72.495 ;
     RECT  2.16 72.765 84.24 73.035 ;
     RECT  2.16 73.305 84.24 73.575 ;
     RECT  2.16 73.845 84.24 74.115 ;
     RECT  2.16 74.385 84.24 74.655 ;
     RECT  2.16 74.925 84.24 75.195 ;
     RECT  2.16 75.465 84.24 75.6 ;
    LAYER RVTP ;
     RECT  2.16 2.295 84.24 2.565 ;
     RECT  2.16 2.835 84.24 3.105 ;
     RECT  2.16 3.375 84.24 3.645 ;
     RECT  2.16 3.915 84.24 4.185 ;
     RECT  2.16 4.455 84.24 4.725 ;
     RECT  2.16 4.995 84.24 5.265 ;
     RECT  2.16 5.535 84.24 5.805 ;
     RECT  2.16 6.075 84.24 6.345 ;
     RECT  2.16 6.615 84.24 6.885 ;
     RECT  2.16 7.155 84.24 7.425 ;
     RECT  2.16 7.695 84.24 7.965 ;
     RECT  2.16 8.235 84.24 8.505 ;
     RECT  2.16 8.775 84.24 9.045 ;
     RECT  2.16 9.315 84.24 9.585 ;
     RECT  2.16 9.855 84.24 10.125 ;
     RECT  2.16 10.395 84.24 10.665 ;
     RECT  2.16 10.935 84.24 11.205 ;
     RECT  2.16 11.475 84.24 11.745 ;
     RECT  2.16 12.015 84.24 12.285 ;
     RECT  2.16 12.555 84.24 12.825 ;
     RECT  2.16 13.095 84.24 13.365 ;
     RECT  2.16 13.635 84.24 13.905 ;
     RECT  2.16 14.175 84.24 14.445 ;
     RECT  2.16 14.715 84.24 14.985 ;
     RECT  2.16 15.255 84.24 15.525 ;
     RECT  2.16 15.795 84.24 16.065 ;
     RECT  2.16 16.335 84.24 16.605 ;
     RECT  2.16 16.875 84.24 17.145 ;
     RECT  2.16 17.415 84.24 17.685 ;
     RECT  2.16 17.955 84.24 18.225 ;
     RECT  2.16 18.495 84.24 18.765 ;
     RECT  2.16 19.035 84.24 19.305 ;
     RECT  2.16 19.575 84.24 19.845 ;
     RECT  2.16 20.115 84.24 20.385 ;
     RECT  2.16 20.655 84.24 20.925 ;
     RECT  2.16 21.195 84.24 21.465 ;
     RECT  2.16 21.735 84.24 22.005 ;
     RECT  2.16 22.275 84.24 22.545 ;
     RECT  2.16 22.815 84.24 23.085 ;
     RECT  2.16 23.355 84.24 23.625 ;
     RECT  2.16 23.895 84.24 24.165 ;
     RECT  2.16 24.435 84.24 24.705 ;
     RECT  2.16 24.975 84.24 25.245 ;
     RECT  2.16 25.515 84.24 25.785 ;
     RECT  2.16 26.055 84.24 26.325 ;
     RECT  2.16 26.595 84.24 26.865 ;
     RECT  2.16 27.135 84.24 27.405 ;
     RECT  2.16 27.675 84.24 27.945 ;
     RECT  2.16 28.215 84.24 28.485 ;
     RECT  2.16 28.755 84.24 29.025 ;
     RECT  2.16 29.295 84.24 29.565 ;
     RECT  2.16 29.835 84.24 30.105 ;
     RECT  2.16 30.375 84.24 30.645 ;
     RECT  2.16 30.915 84.24 31.185 ;
     RECT  2.16 31.455 84.24 31.725 ;
     RECT  2.16 31.995 84.24 32.265 ;
     RECT  2.16 32.535 84.24 32.805 ;
     RECT  2.16 33.075 84.24 33.345 ;
     RECT  2.16 33.615 84.24 33.885 ;
     RECT  2.16 34.155 84.24 34.425 ;
     RECT  2.16 34.695 84.24 34.965 ;
     RECT  2.16 35.235 84.24 35.505 ;
     RECT  2.16 35.775 84.24 36.045 ;
     RECT  2.16 36.315 84.24 36.585 ;
     RECT  2.16 36.855 84.24 37.125 ;
     RECT  2.16 37.395 84.24 37.665 ;
     RECT  2.16 37.935 84.24 38.205 ;
     RECT  2.16 38.475 84.24 38.745 ;
     RECT  2.16 39.015 84.24 39.285 ;
     RECT  2.16 39.555 84.24 39.825 ;
     RECT  2.16 40.095 84.24 40.365 ;
     RECT  2.16 40.635 84.24 40.905 ;
     RECT  2.16 41.175 84.24 41.445 ;
     RECT  2.16 41.715 84.24 41.985 ;
     RECT  2.16 42.255 84.24 42.525 ;
     RECT  2.16 42.795 84.24 43.065 ;
     RECT  2.16 43.335 84.24 43.605 ;
     RECT  2.16 43.875 84.24 44.145 ;
     RECT  2.16 44.415 84.24 44.685 ;
     RECT  2.16 44.955 84.24 45.225 ;
     RECT  2.16 45.495 84.24 45.765 ;
     RECT  2.16 46.035 84.24 46.305 ;
     RECT  2.16 46.575 84.24 46.845 ;
     RECT  2.16 47.115 84.24 47.385 ;
     RECT  2.16 47.655 84.24 47.925 ;
     RECT  2.16 48.195 84.24 48.465 ;
     RECT  2.16 48.735 84.24 49.005 ;
     RECT  2.16 49.275 84.24 49.545 ;
     RECT  2.16 49.815 84.24 50.085 ;
     RECT  2.16 50.355 84.24 50.625 ;
     RECT  2.16 50.895 84.24 51.165 ;
     RECT  2.16 51.435 84.24 51.705 ;
     RECT  2.16 51.975 84.24 52.245 ;
     RECT  2.16 52.515 84.24 52.785 ;
     RECT  2.16 53.055 84.24 53.325 ;
     RECT  2.16 53.595 84.24 53.865 ;
     RECT  2.16 54.135 84.24 54.405 ;
     RECT  2.16 54.675 84.24 54.945 ;
     RECT  2.16 55.215 84.24 55.485 ;
     RECT  2.16 55.755 84.24 56.025 ;
     RECT  2.16 56.295 84.24 56.565 ;
     RECT  2.16 56.835 84.24 57.105 ;
     RECT  2.16 57.375 84.24 57.645 ;
     RECT  2.16 57.915 84.24 58.185 ;
     RECT  2.16 58.455 84.24 58.725 ;
     RECT  2.16 58.995 84.24 59.265 ;
     RECT  2.16 59.535 84.24 59.805 ;
     RECT  2.16 60.075 84.24 60.345 ;
     RECT  2.16 60.615 84.24 60.885 ;
     RECT  2.16 61.155 84.24 61.425 ;
     RECT  2.16 61.695 84.24 61.965 ;
     RECT  2.16 62.235 84.24 62.505 ;
     RECT  2.16 62.775 84.24 63.045 ;
     RECT  2.16 63.315 84.24 63.585 ;
     RECT  2.16 63.855 84.24 64.125 ;
     RECT  2.16 64.395 84.24 64.665 ;
     RECT  2.16 64.935 84.24 65.205 ;
     RECT  2.16 65.475 84.24 65.745 ;
     RECT  2.16 66.015 84.24 66.285 ;
     RECT  2.16 66.555 84.24 66.825 ;
     RECT  2.16 67.095 84.24 67.365 ;
     RECT  2.16 67.635 84.24 67.905 ;
     RECT  2.16 68.175 84.24 68.445 ;
     RECT  2.16 68.715 84.24 68.985 ;
     RECT  2.16 69.255 84.24 69.525 ;
     RECT  2.16 69.795 84.24 70.065 ;
     RECT  2.16 70.335 84.24 70.605 ;
     RECT  2.16 70.875 84.24 71.145 ;
     RECT  2.16 71.415 84.24 71.685 ;
     RECT  2.16 71.955 84.24 72.225 ;
     RECT  2.16 72.495 84.24 72.765 ;
     RECT  2.16 73.035 84.24 73.305 ;
     RECT  2.16 73.575 84.24 73.845 ;
     RECT  2.16 74.115 84.24 74.385 ;
     RECT  2.16 74.655 84.24 74.925 ;
     RECT  2.16 75.195 84.24 75.465 ;
    LAYER M1 ;
     RECT  2.16 2.151 84.24 75.609 ;
    LAYER M2 ;
     RECT  0.103 2.538 0.203 2.556 ;
     RECT  0.103 4.23 0.535 4.248 ;
     RECT  0.175 7.398 0.535 7.416 ;
     RECT  0.103 8.442 0.535 9.108 ;
     RECT  0.535 3.96 0.571 4.248 ;
     RECT  0.535 22.212 0.571 22.806 ;
     RECT  0.571 3.96 1.147 4.824 ;
     RECT  1.147 3.312 1.291 4.824 ;
     RECT  1.291 3.114 1.723 4.824 ;
     RECT  1.723 2.502 1.759 4.824 ;
     RECT  1.759 2.376 2.16 4.824 ;
     RECT  0.535 6.696 2.16 9.108 ;
     RECT  0.571 22.176 2.16 22.806 ;
     RECT  0.535 24.444 2.16 24.462 ;
     RECT  0.535 26.37 2.16 26.388 ;
     RECT  0.535 27.918 2.16 27.936 ;
     RECT  0.103 64.944 2.16 65.538 ;
     RECT  0.535 67.14 2.16 67.158 ;
     RECT  2.16 2.151 2.695 75.609 ;
     RECT  2.695 2.07 3.019 75.609 ;
     RECT  3.019 1.962 6.035 75.609 ;
     RECT  6.035 2.034 8.663 75.609 ;
     RECT  8.663 2.106 8.987 75.609 ;
     RECT  8.987 2.151 19.939 75.609 ;
     RECT  19.939 2.106 22.379 75.609 ;
     RECT  22.379 2.151 84.24 75.609 ;
     RECT  84.24 35.982 85.487 38.124 ;
     RECT  85.487 35.982 85.523 38.034 ;
     RECT  85.523 36.396 86.315 36.414 ;
     RECT  85.523 37.944 86.315 37.962 ;
    LAYER M3 ;
     RECT  1.728 1.003 1.746 1.099 ;
     RECT  1.728 1.099 1.782 1.387 ;
     RECT  5.328 1.195 5.346 1.579 ;
     RECT  8.82 1.291 8.838 1.675 ;
     RECT  2.556 1.771 2.574 1.867 ;
     RECT  2.556 1.867 2.646 1.957 ;
     RECT  5.184 1.579 5.346 1.957 ;
     RECT  8.82 1.675 9.126 2.029 ;
     RECT  8.64 2.029 9.126 2.059 ;
     RECT  4.104 2.029 4.122 2.065 ;
     RECT  5.184 1.957 6.03 2.065 ;
     RECT  2.556 1.957 3.042 2.101 ;
     RECT  7.38 2.029 7.47 2.101 ;
     RECT  1.152 1.387 1.782 2.143 ;
     RECT  2.556 2.101 3.33 2.143 ;
     RECT  7.236 2.101 7.578 2.143 ;
     RECT  8.46 2.059 9.126 2.143 ;
     RECT  7.236 2.143 9.126 2.191 ;
     RECT  13.215 2.143 13.305 2.191 ;
     RECT  22.356 2.101 22.374 2.191 ;
     RECT  45.615 2.143 45.705 2.191 ;
     RECT  56.415 2.143 56.505 2.191 ;
     RECT  27.9 2.191 27.918 2.227 ;
     RECT  40.215 2.143 40.305 2.227 ;
     RECT  51.015 2.143 51.105 2.227 ;
     RECT  52.416 2.191 52.434 2.227 ;
     RECT  55.62 2.191 56.505 2.227 ;
     RECT  68.22 2.191 68.238 2.227 ;
     RECT  71.82 2.191 71.838 2.227 ;
     RECT  72.615 2.143 72.705 2.227 ;
     RECT  68.22 2.227 68.346 2.24 ;
     RECT  69.264 2.227 69.282 2.24 ;
     RECT  26.244 2.191 26.262 2.251 ;
     RECT  34.815 2.143 34.905 2.251 ;
     RECT  42.264 2.227 42.282 2.251 ;
     RECT  45.615 2.191 45.774 2.251 ;
     RECT  67.215 2.143 67.305 2.251 ;
     RECT  4.104 2.065 6.03 2.263 ;
     RECT  17.1 2.227 17.118 2.263 ;
     RECT  27.9 2.227 28.602 2.263 ;
     RECT  29.415 2.143 29.505 2.263 ;
     RECT  38.484 2.227 38.502 2.263 ;
     RECT  50.58 2.227 51.105 2.263 ;
     RECT  52.056 2.227 53.154 2.263 ;
     RECT  60.012 2.191 60.03 2.263 ;
     RECT  65.916 2.251 65.934 2.263 ;
     RECT  67.215 2.251 67.374 2.263 ;
     RECT  70.236 2.227 70.29 2.263 ;
     RECT  19.944 2.101 19.962 2.299 ;
     RECT  21.528 2.101 21.546 2.299 ;
     RECT  22.356 2.191 23.022 2.299 ;
     RECT  24.015 2.143 24.105 2.299 ;
     RECT  25.992 2.251 26.262 2.299 ;
     RECT  38.484 2.263 38.862 2.299 ;
     RECT  59.58 2.263 60.03 2.299 ;
     RECT  63.108 2.227 63.27 2.299 ;
     RECT  66.924 2.263 67.374 2.335 ;
     RECT  35.928 2.251 35.946 2.347 ;
     RECT  7.056 2.191 9.126 2.371 ;
     RECT  13.215 2.191 14.022 2.371 ;
     RECT  17.1 2.263 17.73 2.371 ;
     RECT  18.615 2.143 18.705 2.371 ;
     RECT  19.944 2.299 20.07 2.371 ;
     RECT  25.884 2.299 26.262 2.371 ;
     RECT  31.752 2.299 31.77 2.371 ;
     RECT  33.516 2.227 33.534 2.371 ;
     RECT  34.704 2.251 34.905 2.371 ;
     RECT  35.928 2.347 35.982 2.371 ;
     RECT  36.936 2.299 36.954 2.371 ;
     RECT  38.34 2.299 38.862 2.371 ;
     RECT  39.672 2.227 40.305 2.371 ;
     RECT  45.108 2.251 45.774 2.371 ;
     RECT  47.916 2.263 47.934 2.371 ;
     RECT  50.58 2.263 53.154 2.371 ;
     RECT  62.748 2.299 63.774 2.371 ;
     RECT  64.8 2.263 64.818 2.371 ;
     RECT  65.556 2.263 66.042 2.371 ;
     RECT  66.852 2.335 67.374 2.371 ;
     RECT  70.236 2.263 70.722 2.371 ;
     RECT  21.528 2.299 24.105 2.413 ;
     RECT  24.948 2.251 24.966 2.413 ;
     RECT  27.9 2.263 29.505 2.413 ;
     RECT  33.084 2.371 34.905 2.413 ;
     RECT  54.684 2.227 56.505 2.413 ;
     RECT  61.815 2.143 61.905 2.413 ;
     RECT  62.64 2.371 63.81 2.413 ;
     RECT  64.62 2.371 67.374 2.413 ;
     RECT  71.82 2.227 72.705 2.413 ;
     RECT  78.015 2.143 78.105 2.413 ;
     RECT  83.415 2.143 83.505 2.413 ;
     RECT  61.815 2.413 63.81 2.443 ;
     RECT  64.62 2.413 67.497 2.443 ;
     RECT  13.215 2.371 14.382 2.461 ;
     RECT  43.848 2.251 43.866 2.461 ;
     RECT  45.108 2.371 46.026 2.461 ;
     RECT  48.708 2.227 48.726 2.461 ;
     RECT  50.076 2.371 53.586 2.461 ;
     RECT  54.684 2.413 56.697 2.461 ;
     RECT  61.815 2.443 67.497 2.461 ;
     RECT  68.22 2.24 69.282 2.461 ;
     RECT  7.056 2.371 9.234 2.489 ;
     RECT  1.152 2.143 3.33 2.491 ;
     RECT  4.104 2.263 6.21 2.491 ;
     RECT  35.928 2.371 36.954 2.491 ;
     RECT  37.8 2.371 40.59 2.491 ;
     RECT  16.02 2.461 16.038 2.497 ;
     RECT  33.084 2.413 35.097 2.497 ;
     RECT  35.928 2.491 40.59 2.497 ;
     RECT  48.708 2.461 49.086 2.497 ;
     RECT  49.932 2.461 53.586 2.497 ;
     RECT  70.236 2.371 71.046 2.497 ;
     RECT  71.82 2.413 72.897 2.497 ;
     RECT  7.056 2.489 9.126 2.525 ;
     RECT  7.056 2.525 8.658 2.533 ;
     RECT  25.884 2.371 26.946 2.533 ;
     RECT  27.9 2.413 29.697 2.533 ;
     RECT  41.544 2.251 42.282 2.533 ;
     RECT  59.58 2.299 60.966 2.539 ;
     RECT  17.1 2.371 19.098 2.569 ;
     RECT  19.944 2.371 20.142 2.569 ;
     RECT  33.084 2.497 35.19 2.569 ;
     RECT  35.928 2.497 40.662 2.569 ;
     RECT  61.815 2.461 69.282 2.569 ;
     RECT  70.236 2.497 72.897 2.569 ;
     RECT  1.152 2.491 6.21 2.605 ;
     RECT  6.984 2.533 8.658 2.605 ;
     RECT  21.528 2.413 24.966 2.605 ;
     RECT  31.284 2.371 31.77 2.605 ;
     RECT  33.084 2.569 40.662 2.605 ;
     RECT  48.708 2.497 53.586 2.605 ;
     RECT  58.032 2.533 58.05 2.605 ;
     RECT  59.148 2.539 61.074 2.605 ;
     RECT  1.152 2.605 8.658 2.621 ;
     RECT  10.8 2.227 10.818 2.641 ;
     RECT  11.664 2.371 12.186 2.641 ;
     RECT  15.48 2.497 16.038 2.641 ;
     RECT  17.1 2.569 20.142 2.641 ;
     RECT  20.88 2.605 24.966 2.641 ;
     RECT  25.884 2.533 29.697 2.641 ;
     RECT  41.544 2.533 42.714 2.641 ;
     RECT  43.848 2.461 46.026 2.641 ;
     RECT  46.764 2.605 47.07 2.641 ;
     RECT  58.968 2.605 61.074 2.641 ;
     RECT  61.815 2.569 73.242 2.641 ;
     RECT  76.752 2.605 76.77 2.641 ;
     RECT  78.015 2.413 78.297 2.641 ;
     RECT  2.268 2.621 8.658 2.669 ;
     RECT  31.284 2.605 40.698 2.731 ;
     RECT  58.968 2.641 73.242 2.731 ;
     RECT  0.108 2.524 0.198 2.765 ;
     RECT  31.176 2.731 40.698 2.767 ;
     RECT  41.508 2.641 42.858 2.767 ;
     RECT  58.896 2.731 73.242 2.767 ;
     RECT  58.824 2.767 73.242 2.795 ;
     RECT  10.8 2.641 12.222 2.803 ;
     RECT  31.176 2.767 42.858 2.803 ;
     RECT  43.848 2.641 47.142 2.803 ;
     RECT  47.88 2.371 47.934 2.803 ;
     RECT  48.708 2.605 53.946 2.803 ;
     RECT  75.888 2.731 75.906 2.803 ;
     RECT  10.584 2.803 12.222 2.839 ;
     RECT  13.215 2.461 14.706 2.839 ;
     RECT  30.636 2.803 53.946 2.839 ;
     RECT  54.684 2.461 56.862 2.839 ;
     RECT  10.584 2.839 14.706 2.875 ;
     RECT  74.232 2.767 74.25 2.911 ;
     RECT  75.456 2.803 75.906 2.911 ;
     RECT  76.752 2.641 78.297 2.911 ;
     RECT  57.78 2.605 58.05 3.001 ;
     RECT  58.824 2.795 73.062 3.001 ;
     RECT  30.636 2.839 56.862 3.029 ;
     RECT  1.152 2.621 1.314 3.137 ;
     RECT  30.816 3.029 56.862 3.145 ;
     RECT  57.78 3.001 73.062 3.145 ;
     RECT  9.864 2.875 14.706 3.181 ;
     RECT  15.48 2.641 29.862 3.181 ;
     RECT  80.928 3.145 81.666 3.181 ;
     RECT  83.415 2.413 83.697 3.181 ;
     RECT  74.232 2.911 78.426 3.271 ;
     RECT  74.232 3.271 79.146 3.301 ;
     RECT  79.884 3.271 79.902 3.301 ;
     RECT  74.232 3.301 79.902 3.307 ;
     RECT  1.152 3.137 1.17 3.335 ;
     RECT  80.928 3.181 83.697 3.335 ;
     RECT  2.304 2.669 8.658 3.379 ;
     RECT  2.304 3.379 8.694 3.451 ;
     RECT  0.144 2.765 0.198 3.499 ;
     RECT  73.8 3.307 79.902 3.613 ;
     RECT  2.304 3.451 9.054 3.713 ;
     RECT  6.948 3.713 9.054 3.811 ;
     RECT  9.864 3.181 29.97 3.811 ;
     RECT  0.144 3.499 0.594 3.883 ;
     RECT  30.816 3.145 73.062 3.883 ;
     RECT  73.8 3.613 79.938 3.883 ;
     RECT  80.928 3.335 82.206 3.883 ;
     RECT  6.948 3.811 29.97 3.979 ;
     RECT  30.816 3.883 82.206 3.979 ;
     RECT  83.124 3.335 83.697 3.991 ;
     RECT  6.948 3.979 82.206 4.081 ;
     RECT  83.124 3.991 83.898 4.081 ;
     RECT  6.948 4.081 83.898 4.153 ;
     RECT  0.108 3.883 0.594 4.253 ;
     RECT  6.948 4.153 84.042 4.379 ;
     RECT  6.948 4.379 83.898 4.415 ;
     RECT  0.144 4.253 0.594 4.445 ;
     RECT  0.576 4.445 0.594 4.829 ;
     RECT  6.948 4.415 43.146 4.919 ;
     RECT  2.304 3.713 6.138 5.179 ;
     RECT  6.948 4.919 9.234 5.179 ;
     RECT  2.304 5.179 9.234 5.225 ;
     RECT  10.116 4.919 43.146 5.269 ;
     RECT  43.884 4.415 83.697 5.269 ;
     RECT  2.304 5.225 6.21 5.419 ;
     RECT  10.116 5.269 83.79 5.459 ;
     RECT  10.116 5.459 83.754 5.531 ;
     RECT  2.268 5.419 6.21 5.603 ;
     RECT  6.948 5.225 9.234 5.707 ;
     RECT  10.116 5.531 43.038 5.707 ;
     RECT  2.304 5.603 6.21 5.729 ;
     RECT  6.948 5.707 43.038 5.971 ;
     RECT  2.304 5.729 5.814 5.999 ;
     RECT  0.144 5.899 0.162 6.077 ;
     RECT  2.304 5.999 4.302 6.305 ;
     RECT  6.588 5.971 43.038 6.421 ;
     RECT  43.884 5.531 83.754 6.421 ;
     RECT  5.04 5.999 5.814 6.583 ;
     RECT  6.588 6.421 83.898 6.583 ;
     RECT  5.04 6.583 83.898 6.619 ;
     RECT  5.04 6.619 84.042 6.809 ;
     RECT  3.744 6.305 4.302 6.811 ;
     RECT  5.04 6.809 83.898 6.811 ;
     RECT  3.744 6.811 83.898 6.845 ;
     RECT  0.54 6.691 0.558 6.893 ;
     RECT  2.304 6.305 2.934 7.087 ;
     RECT  3.744 6.845 83.697 7.087 ;
     RECT  0.324 7.051 0.342 7.181 ;
     RECT  0.216 7.195 0.234 7.393 ;
     RECT  0.18 7.393 0.234 7.469 ;
     RECT  2.304 7.087 83.697 7.663 ;
     RECT  2.304 7.663 83.862 7.889 ;
     RECT  2.304 7.889 83.79 8.033 ;
     RECT  0.54 7.933 0.558 8.141 ;
     RECT  0.324 8.395 0.342 8.437 ;
     RECT  0.108 8.437 0.342 8.525 ;
     RECT  2.304 8.033 83.697 8.573 ;
     RECT  2.304 8.573 6.894 8.683 ;
     RECT  2.268 8.683 6.894 8.735 ;
     RECT  7.668 8.573 83.697 8.941 ;
     RECT  2.304 8.735 6.894 8.969 ;
     RECT  7.668 8.941 83.826 9.005 ;
     RECT  22.788 9.005 83.826 9.085 ;
     RECT  0.108 8.525 0.126 9.197 ;
     RECT  22.788 9.085 84.114 9.239 ;
     RECT  7.668 9.005 22.014 9.509 ;
     RECT  2.304 8.969 6.75 9.643 ;
     RECT  2.268 9.643 6.75 9.691 ;
     RECT  7.668 9.509 21.978 9.691 ;
     RECT  22.788 9.239 83.898 9.815 ;
     RECT  2.268 9.691 21.978 9.887 ;
     RECT  0.144 9.739 0.162 9.917 ;
     RECT  22.788 9.815 83.697 9.959 ;
     RECT  2.304 9.887 21.978 10.355 ;
     RECT  2.34 10.355 21.978 10.363 ;
     RECT  22.788 9.959 48.762 10.363 ;
     RECT  2.34 10.363 48.762 10.625 ;
     RECT  2.415 10.625 48.762 10.699 ;
     RECT  49.608 9.959 83.697 10.699 ;
     RECT  2.415 10.699 83.697 11.137 ;
     RECT  2.415 11.137 83.898 11.911 ;
     RECT  2.376 11.911 83.898 11.947 ;
     RECT  2.376 11.947 83.934 12.479 ;
     RECT  2.376 12.479 83.898 13.055 ;
     RECT  2.376 13.055 83.697 13.559 ;
     RECT  2.376 13.559 31.878 14.179 ;
     RECT  32.616 13.559 83.697 14.251 ;
     RECT  2.34 14.179 31.878 14.521 ;
     RECT  32.616 14.251 84.042 14.521 ;
     RECT  2.34 14.521 84.042 15.061 ;
     RECT  2.34 15.061 84.114 15.791 ;
     RECT  2.376 15.791 84.114 16.133 ;
     RECT  2.376 16.133 83.697 16.951 ;
     RECT  2.376 16.951 83.97 17.117 ;
     RECT  2.415 17.117 83.97 17.725 ;
     RECT  2.415 17.725 84.114 17.879 ;
     RECT  22.752 17.879 84.114 18.149 ;
     RECT  2.415 17.879 22.014 18.419 ;
     RECT  22.788 18.149 83.862 18.419 ;
     RECT  22.86 18.419 83.862 18.725 ;
     RECT  2.415 18.419 21.978 19.192 ;
     RECT  22.86 18.725 83.697 19.192 ;
     RECT  2.415 19.192 83.697 19.741 ;
     RECT  2.415 19.741 83.97 20.155 ;
     RECT  2.304 20.155 83.97 20.309 ;
     RECT  2.304 20.309 83.862 20.345 ;
     RECT  2.304 20.345 83.697 20.395 ;
     RECT  2.196 20.395 83.697 20.417 ;
     RECT  2.196 20.417 21.546 20.453 ;
     RECT  2.304 20.453 21.546 21.271 ;
     RECT  22.86 20.417 83.697 21.271 ;
     RECT  2.304 21.271 21.69 21.433 ;
     RECT  2.304 21.433 21.726 21.496 ;
     RECT  22.752 21.271 84.006 21.541 ;
     RECT  0.576 22.171 0.594 22.207 ;
     RECT  0.54 22.207 0.594 22.349 ;
     RECT  2.304 21.496 21.942 22.351 ;
     RECT  22.716 21.541 84.006 22.351 ;
     RECT  2.304 22.351 84.042 22.477 ;
     RECT  2.268 22.477 84.042 22.739 ;
     RECT  2.268 22.739 83.898 22.775 ;
     RECT  0.54 22.349 0.558 22.925 ;
     RECT  2.268 22.775 83.697 23.035 ;
     RECT  1.98 23.035 83.697 23.213 ;
     RECT  0.144 23.947 0.162 24.221 ;
     RECT  2.268 23.213 83.697 24.241 ;
     RECT  2.268 24.241 83.862 24.395 ;
     RECT  0.54 24.439 0.558 24.557 ;
     RECT  2.268 24.395 83.697 25.277 ;
     RECT  4.896 25.277 83.697 25.321 ;
     RECT  4.896 25.321 83.718 25.591 ;
     RECT  2.268 25.277 4.158 25.825 ;
     RECT  2.232 25.825 4.158 25.949 ;
     RECT  4.896 25.591 83.97 25.979 ;
     RECT  2.304 25.949 4.158 26.248 ;
     RECT  4.896 25.979 83.862 26.248 ;
     RECT  0.324 25.675 0.342 26.299 ;
     RECT  0.144 26.299 0.342 26.365 ;
     RECT  0.144 26.365 0.558 26.477 ;
     RECT  0.54 26.477 0.558 26.861 ;
     RECT  2.304 26.248 83.862 26.941 ;
     RECT  2.304 26.941 84.114 27.019 ;
     RECT  1.98 27.019 84.114 27.197 ;
     RECT  2.304 27.197 84.114 27.203 ;
     RECT  0.324 27.787 0.342 27.913 ;
     RECT  0.324 27.913 0.558 27.917 ;
     RECT  0.54 27.917 0.558 28.013 ;
     RECT  2.304 27.203 83.826 28.723 ;
     RECT  2.304 28.723 84.042 29.795 ;
     RECT  2.415 29.795 84.042 30.101 ;
     RECT  2.415 30.101 83.826 30.839 ;
     RECT  2.415 30.839 83.697 31.801 ;
     RECT  2.376 31.801 84.042 32.189 ;
     RECT  2.376 32.189 83.898 32.539 ;
     RECT  2.34 32.539 83.898 33.035 ;
     RECT  2.34 33.035 83.697 34.501 ;
     RECT  2.34 34.501 83.79 34.655 ;
     RECT  85.5 35.977 85.518 36.121 ;
     RECT  2.34 34.655 83.697 36.239 ;
     RECT  2.34 36.239 82.35 36.275 ;
     RECT  85.464 36.121 85.518 36.319 ;
     RECT  86.292 36.391 86.31 36.557 ;
     RECT  80.568 36.275 82.35 36.701 ;
     RECT  2.34 36.275 79.686 36.779 ;
     RECT  80.64 36.701 82.35 36.779 ;
     RECT  79.236 36.779 79.686 37.201 ;
     RECT  84.888 36.319 85.518 37.387 ;
     RECT  2.34 36.779 78.498 37.391 ;
     RECT  81.72 36.779 82.35 37.399 ;
     RECT  83.088 36.239 83.697 37.399 ;
     RECT  79.236 37.201 79.866 37.435 ;
     RECT  80.64 36.779 80.982 37.435 ;
     RECT  81.72 37.399 83.697 37.499 ;
     RECT  2.415 37.391 78.498 37.613 ;
     RECT  2.415 37.613 19.602 37.625 ;
     RECT  83.016 37.499 83.697 37.675 ;
     RECT  20.628 37.613 78.498 37.733 ;
     RECT  73.62 37.733 78.498 37.741 ;
     RECT  79.236 37.435 80.982 37.741 ;
     RECT  81.72 37.499 82.206 37.741 ;
     RECT  84.852 37.387 85.518 37.859 ;
     RECT  86.292 37.579 86.31 37.967 ;
     RECT  85.464 37.859 85.518 38.039 ;
     RECT  83.016 37.675 83.934 38.129 ;
     RECT  85.464 38.039 85.482 38.129 ;
     RECT  83.016 38.129 83.697 38.281 ;
     RECT  2.415 37.625 19.566 38.407 ;
     RECT  2.415 38.407 19.638 38.443 ;
     RECT  20.628 37.733 72.897 38.443 ;
     RECT  2.415 38.443 72.897 38.479 ;
     RECT  73.62 37.741 82.206 38.479 ;
     RECT  2.415 38.479 82.206 38.551 ;
     RECT  82.944 38.281 83.697 38.551 ;
     RECT  2.415 38.551 83.697 39.067 ;
     RECT  2.376 39.067 83.697 39.119 ;
     RECT  2.415 39.119 83.697 41.107 ;
     RECT  2.34 41.107 83.697 42.601 ;
     RECT  2.34 42.601 84.114 42.719 ;
     RECT  2.34 42.719 83.697 43.295 ;
     RECT  2.415 43.295 83.697 44.299 ;
     RECT  2.304 44.299 83.697 44.375 ;
     RECT  2.415 44.375 83.697 46.345 ;
     RECT  2.376 46.345 83.697 48.811 ;
     RECT  2.376 48.811 83.754 48.965 ;
     RECT  2.376 48.965 83.697 49.549 ;
     RECT  2.34 49.549 83.697 49.891 ;
     RECT  2.34 49.891 83.754 50.081 ;
     RECT  2.376 50.081 83.754 50.971 ;
     RECT  2.376 50.971 83.79 51.161 ;
     RECT  2.376 51.161 83.754 52.051 ;
     RECT  2.376 52.051 84.114 52.277 ;
     RECT  2.376 52.277 84.042 52.475 ;
     RECT  2.415 52.475 84.042 52.979 ;
     RECT  2.415 52.979 83.826 56.101 ;
     RECT  2.376 56.101 83.826 56.759 ;
     RECT  2.415 56.759 83.826 58.261 ;
     RECT  2.415 58.261 84.114 58.379 ;
     RECT  2.415 58.379 84.042 59.099 ;
     RECT  2.415 59.099 83.826 59.467 ;
     RECT  2.412 59.467 83.826 59.765 ;
     RECT  2.415 59.765 83.826 60.571 ;
     RECT  2.376 60.571 83.826 62.501 ;
     RECT  2.376 62.501 83.697 63.509 ;
     RECT  2.415 63.509 83.697 64.597 ;
     RECT  0.108 64.939 0.126 65.035 ;
     RECT  0.108 65.035 0.342 65.443 ;
     RECT  0.108 65.443 0.558 65.645 ;
     RECT  0.54 65.645 0.558 65.741 ;
     RECT  2.304 64.597 83.697 65.785 ;
     RECT  2.268 65.785 83.697 65.911 ;
     RECT  2.268 65.911 83.79 65.933 ;
     RECT  2.304 65.933 83.79 66.317 ;
     RECT  0.18 66.907 0.198 66.955 ;
     RECT  0.18 66.955 0.342 67.135 ;
     RECT  0.18 67.135 0.558 67.277 ;
     RECT  0.144 67.435 0.162 67.613 ;
     RECT  2.304 66.317 83.754 67.667 ;
     RECT  2.34 67.667 83.754 67.973 ;
     RECT  2.34 67.973 83.697 68.909 ;
     RECT  2.34 68.909 41.31 68.945 ;
     RECT  42.048 68.909 83.697 69.323 ;
     RECT  81.828 69.323 83.697 69.449 ;
     RECT  82.008 69.449 82.026 69.485 ;
     RECT  42.048 69.323 80.874 69.581 ;
     RECT  2.415 68.945 41.31 69.691 ;
     RECT  42.048 69.581 80.082 69.691 ;
     RECT  2.415 69.691 80.082 69.719 ;
     RECT  80.856 69.581 80.874 69.719 ;
     RECT  2.415 69.719 79.722 69.989 ;
     RECT  2.415 69.989 32.13 70.565 ;
     RECT  32.868 69.989 79.722 70.637 ;
     RECT  32.868 70.637 78.93 70.877 ;
     RECT  32.868 70.877 78.678 70.879 ;
     RECT  2.415 70.565 32.022 70.951 ;
     RECT  79.884 70.951 79.902 71.213 ;
     RECT  32.76 70.879 78.678 71.309 ;
     RECT  2.376 70.951 32.022 71.653 ;
     RECT  2.376 71.653 32.346 71.753 ;
     RECT  33.084 71.309 78.678 72.463 ;
     RECT  2.415 71.753 32.346 72.523 ;
     RECT  33.084 72.463 78.894 72.523 ;
     RECT  2.415 72.523 78.894 72.571 ;
     RECT  2.415 72.571 78.966 73.103 ;
     RECT  2.415 73.103 78.606 73.301 ;
     RECT  3.42 73.301 78.606 73.499 ;
     RECT  5.184 73.499 57.762 73.571 ;
     RECT  58.536 73.499 78.354 73.769 ;
     RECT  5.22 73.571 57.762 74.093 ;
     RECT  3.42 73.499 4.446 74.098 ;
     RECT  16.488 74.093 57.762 74.111 ;
     RECT  16.488 74.111 25.614 74.183 ;
     RECT  3.636 74.098 4.446 74.219 ;
     RECT  3.636 74.219 4.374 74.309 ;
     RECT  3.636 74.309 4.302 74.345 ;
     RECT  58.536 73.769 78.297 74.353 ;
     RECT  16.488 74.183 25.506 74.381 ;
     RECT  3.996 74.345 4.302 74.417 ;
     RECT  4.032 74.417 4.302 74.453 ;
     RECT  5.22 74.093 15.678 74.453 ;
     RECT  4.068 74.453 4.302 74.579 ;
     RECT  26.46 74.111 57.762 74.579 ;
     RECT  58.5 74.353 78.297 74.579 ;
     RECT  30.96 74.579 51.426 74.621 ;
     RECT  58.5 74.579 76.878 74.651 ;
     RECT  39.888 74.621 51.426 74.687 ;
     RECT  52.272 74.579 57.762 74.695 ;
     RECT  58.5 74.651 76.41 74.695 ;
     RECT  4.068 74.579 4.158 74.723 ;
     RECT  39.924 74.687 51.426 74.723 ;
     RECT  52.272 74.695 76.41 74.723 ;
     RECT  52.272 74.723 76.014 74.759 ;
     RECT  50.112 74.723 51.426 74.849 ;
     RECT  5.364 74.453 15.678 74.885 ;
     RECT  39.924 74.723 49.338 74.885 ;
     RECT  26.46 74.579 30.222 74.893 ;
     RECT  31.392 74.621 39.114 74.921 ;
     RECT  50.112 74.849 51.297 74.921 ;
     RECT  52.272 74.759 74.178 74.921 ;
     RECT  39.924 74.885 49.194 74.957 ;
     RECT  21.096 74.381 25.506 74.965 ;
     RECT  26.28 74.893 30.222 74.965 ;
     RECT  5.472 74.885 15.678 74.993 ;
     RECT  21.096 74.965 30.222 74.993 ;
     RECT  52.272 74.921 62.406 74.993 ;
     RECT  28.764 74.993 30.222 75.029 ;
     RECT  31.572 74.921 39.114 75.029 ;
     RECT  50.148 74.921 51.297 75.029 ;
     RECT  5.616 74.993 9.99 75.119 ;
     RECT  21.096 74.993 27.918 75.119 ;
     RECT  28.764 75.029 29.826 75.119 ;
     RECT  31.572 75.029 38.898 75.119 ;
     RECT  39.924 74.957 49.086 75.119 ;
     RECT  50.256 75.029 51.297 75.119 ;
     RECT  52.272 74.993 59.634 75.119 ;
     RECT  63.288 74.921 74.178 75.119 ;
     RECT  74.916 74.759 76.014 75.119 ;
     RECT  16.488 74.381 20.358 75.155 ;
     RECT  21.096 75.119 23.166 75.155 ;
     RECT  28.764 75.119 29.754 75.155 ;
     RECT  39.924 75.119 43.254 75.155 ;
     RECT  48.528 75.119 48.546 75.155 ;
     RECT  60.372 74.993 62.406 75.155 ;
     RECT  65.232 75.119 74.178 75.155 ;
     RECT  5.796 75.119 9.99 75.191 ;
     RECT  16.704 75.155 20.358 75.191 ;
     RECT  24.015 75.119 27.918 75.191 ;
     RECT  64.188 75.119 64.206 75.191 ;
     RECT  58.14 75.119 59.526 75.197 ;
     RECT  6.336 75.191 9.99 75.227 ;
     RECT  16.956 75.191 20.358 75.227 ;
     RECT  24.015 75.191 25.866 75.227 ;
     RECT  26.676 75.191 27.918 75.227 ;
     RECT  59.076 75.197 59.31 75.227 ;
     RECT  66.42 75.155 74.178 75.227 ;
     RECT  6.66 75.227 9.99 75.245 ;
     RECT  24.015 75.227 25.65 75.245 ;
     RECT  66.42 75.227 68.49 75.245 ;
     RECT  10.728 74.993 15.678 75.263 ;
     RECT  18.615 75.227 20.358 75.263 ;
     RECT  24.015 75.245 25.398 75.263 ;
     RECT  52.272 75.119 53.334 75.263 ;
     RECT  21.096 75.155 23.094 75.271 ;
     RECT  54.144 75.119 57.294 75.293 ;
     RECT  10.764 75.263 15.678 75.299 ;
     RECT  33.876 75.119 38.826 75.299 ;
     RECT  39.924 75.155 43.002 75.299 ;
     RECT  2.415 73.301 2.697 75.347 ;
     RECT  6.66 75.245 8.097 75.347 ;
     RECT  40.14 75.299 41.958 75.347 ;
     RECT  50.544 75.119 51.297 75.347 ;
     RECT  60.372 75.155 62.097 75.347 ;
     RECT  78.015 74.579 78.297 75.347 ;
     RECT  83.415 69.449 83.697 75.347 ;
     RECT  6.66 75.347 7.974 75.389 ;
     RECT  8.856 75.245 9.99 75.389 ;
     RECT  10.764 75.299 11.646 75.389 ;
     RECT  12.384 75.299 15.678 75.389 ;
     RECT  17.676 75.227 17.766 75.389 ;
     RECT  18.615 75.263 19.854 75.389 ;
     RECT  20.772 75.271 23.094 75.389 ;
     RECT  24.015 75.263 24.57 75.389 ;
     RECT  25.38 75.263 25.398 75.389 ;
     RECT  31.572 75.119 33.138 75.389 ;
     RECT  33.876 75.299 37.422 75.389 ;
     RECT  38.16 75.299 38.826 75.389 ;
     RECT  41.04 75.347 41.958 75.389 ;
     RECT  50.544 75.347 51.105 75.389 ;
     RECT  52.272 75.263 53.226 75.389 ;
     RECT  54.144 75.293 57.042 75.389 ;
     RECT  58.14 75.197 58.302 75.389 ;
     RECT  59.076 75.227 59.094 75.389 ;
     RECT  60.372 75.347 61.974 75.389 ;
     RECT  65.232 75.155 65.394 75.389 ;
     RECT  66.42 75.245 67.698 75.389 ;
     RECT  68.472 75.245 68.49 75.389 ;
     RECT  69.264 75.227 74.178 75.389 ;
     RECT  75.024 75.119 75.474 75.389 ;
     RECT  8.856 75.389 9.126 75.425 ;
     RECT  11.412 75.389 11.43 75.425 ;
     RECT  12.384 75.389 13.878 75.425 ;
     RECT  17.676 75.389 17.694 75.425 ;
     RECT  22.752 75.389 23.094 75.425 ;
     RECT  31.572 75.389 31.59 75.425 ;
     RECT  33.876 75.389 34.002 75.425 ;
     RECT  40.14 75.347 40.305 75.425 ;
     RECT  54.144 75.389 54.162 75.425 ;
     RECT  54.972 75.389 55.098 75.425 ;
     RECT  55.908 75.389 57.042 75.425 ;
     RECT  58.14 75.389 58.158 75.425 ;
     RECT  60.516 75.389 61.974 75.425 ;
     RECT  66.924 75.389 67.554 75.425 ;
     RECT  69.264 75.389 72.846 75.425 ;
     RECT  73.584 75.389 74.142 75.425 ;
     RECT  20.772 75.389 21.726 75.437 ;
     RECT  21.708 75.437 21.726 75.461 ;
     RECT  26.748 75.227 27.918 75.461 ;
     RECT  42.984 75.299 43.002 75.461 ;
     RECT  55.08 75.425 55.098 75.461 ;
     RECT  71.784 75.425 72.846 75.461 ;
     RECT  6.696 75.389 7.974 75.497 ;
     RECT  12.384 75.425 13.374 75.497 ;
     RECT  19.44 75.389 19.458 75.497 ;
     RECT  34.815 75.389 35.514 75.497 ;
     RECT  44.892 75.119 47.394 75.497 ;
     RECT  69.48 75.425 70.686 75.497 ;
     RECT  7.815 75.497 7.974 75.533 ;
     RECT  15.228 75.389 15.246 75.533 ;
     RECT  22.752 75.425 22.77 75.533 ;
     RECT  27.072 75.461 27.918 75.533 ;
     RECT  28.944 75.155 29.754 75.533 ;
     RECT  33.12 75.389 33.138 75.533 ;
     RECT  36.288 75.389 36.306 75.533 ;
     RECT  38.808 75.389 38.826 75.533 ;
     RECT  44.892 75.497 47.358 75.533 ;
     RECT  56.196 75.425 57.042 75.533 ;
     RECT  60.948 75.425 61.974 75.533 ;
     RECT  69.516 75.497 70.686 75.533 ;
     RECT  71.784 75.461 71.802 75.533 ;
     RECT  72.615 75.461 72.846 75.533 ;
     RECT  74.124 75.425 74.142 75.533 ;
     RECT  75.456 75.389 75.474 75.533 ;
     RECT  8.856 75.425 8.874 75.569 ;
     RECT  12.384 75.497 12.402 75.569 ;
     RECT  13.215 75.497 13.374 75.569 ;
     RECT  24.015 75.389 24.174 75.569 ;
     RECT  28.944 75.533 29.505 75.569 ;
     RECT  33.876 75.425 33.894 75.569 ;
     RECT  34.815 75.497 35.478 75.569 ;
     RECT  41.04 75.389 41.058 75.569 ;
     RECT  46.476 75.533 47.358 75.569 ;
     RECT  60.948 75.533 60.966 75.569 ;
     RECT  61.815 75.533 61.974 75.569 ;
     RECT  66.924 75.425 67.305 75.569 ;
     RECT  69.516 75.533 69.534 75.569 ;
     RECT  2.415 75.347 2.505 75.617 ;
     RECT  7.815 75.533 7.905 75.617 ;
     RECT  13.215 75.569 13.305 75.617 ;
     RECT  18.615 75.389 18.705 75.617 ;
     RECT  24.015 75.569 24.105 75.617 ;
     RECT  29.415 75.569 29.505 75.617 ;
     RECT  34.815 75.569 34.905 75.617 ;
     RECT  40.215 75.425 40.305 75.617 ;
     RECT  45.615 75.533 45.705 75.617 ;
     RECT  51.015 75.389 51.105 75.617 ;
     RECT  56.415 75.533 56.505 75.617 ;
     RECT  61.815 75.569 61.905 75.617 ;
     RECT  67.215 75.569 67.305 75.617 ;
     RECT  72.615 75.533 72.705 75.617 ;
     RECT  78.015 75.347 78.105 75.617 ;
     RECT  83.415 75.347 83.505 75.617 ;
     RECT  27.792 75.533 27.81 75.821 ;
    LAYER M4 ;
     RECT  0.084 1.008 1.757 1.032 ;
     RECT  0.06 1.032 1.757 1.104 ;
     RECT  0.084 1.104 1.757 1.128 ;
     RECT  0.06 1.128 1.757 1.2 ;
     RECT  0.084 1.2 1.757 1.224 ;
     RECT  0.06 1.224 1.757 1.296 ;
     RECT  0.084 1.296 1.757 1.32 ;
     RECT  0.06 1.32 1.757 1.392 ;
     RECT  0.084 1.392 1.757 1.416 ;
     RECT  0.06 1.416 1.757 1.488 ;
     RECT  0.084 1.488 1.757 1.512 ;
     RECT  0.06 1.512 1.757 1.584 ;
     RECT  0.084 1.584 1.757 1.608 ;
     RECT  0.06 1.608 1.757 1.68 ;
     RECT  0.084 1.68 1.757 1.704 ;
     RECT  0.06 1.704 1.757 1.776 ;
     RECT  0.084 1.776 1.757 1.8 ;
     RECT  0.06 1.8 1.757 1.872 ;
     RECT  0.084 1.872 1.757 1.896 ;
     RECT  0.06 1.896 1.757 1.968 ;
     RECT  0.084 1.968 1.757 1.992 ;
     RECT  0.06 1.992 1.757 2.064 ;
     RECT  0.084 2.064 1.757 2.088 ;
     RECT  0.06 2.088 1.757 2.16 ;
     RECT  0.084 2.16 1.757 2.184 ;
     RECT  0.06 2.184 1.757 2.256 ;
     RECT  0.084 2.256 1.757 2.28 ;
     RECT  0.06 2.28 1.757 2.352 ;
     RECT  0.084 2.352 1.757 2.376 ;
     RECT  0.06 2.376 1.757 2.448 ;
     RECT  0.084 2.448 1.757 2.472 ;
     RECT  0.06 2.472 1.757 2.544 ;
     RECT  0.084 2.544 1.757 2.568 ;
     RECT  0.06 2.568 1.757 2.64 ;
     RECT  0.084 2.64 1.757 2.664 ;
     RECT  0.06 2.664 1.757 2.736 ;
     RECT  0.084 2.736 1.757 2.76 ;
     RECT  0.06 2.76 1.757 2.832 ;
     RECT  0.084 2.832 1.757 2.856 ;
     RECT  0.06 2.856 1.757 2.928 ;
     RECT  0.084 2.928 1.757 2.952 ;
     RECT  0.06 2.952 1.757 3.024 ;
     RECT  0.084 3.024 1.757 3.048 ;
     RECT  0.06 3.048 1.757 3.12 ;
     RECT  0.084 3.12 1.757 3.144 ;
     RECT  0.06 3.144 1.757 3.216 ;
     RECT  0.084 3.216 1.757 3.24 ;
     RECT  0.06 3.24 1.757 3.312 ;
     RECT  0.084 3.312 1.757 3.336 ;
     RECT  0.06 3.336 1.757 3.408 ;
     RECT  0.084 3.408 1.757 3.432 ;
     RECT  0.06 3.432 1.757 3.504 ;
     RECT  0.084 3.504 1.757 3.528 ;
     RECT  0.06 3.528 1.757 3.6 ;
     RECT  0.084 3.6 1.757 3.624 ;
     RECT  0.06 3.624 1.757 3.696 ;
     RECT  0.084 3.696 1.757 3.72 ;
     RECT  0.06 3.72 1.757 3.792 ;
     RECT  0.084 3.792 1.757 3.816 ;
     RECT  0.06 3.816 1.757 3.888 ;
     RECT  0.084 3.888 1.757 3.912 ;
     RECT  0.06 3.912 1.757 3.984 ;
     RECT  0.084 3.984 1.757 4.008 ;
     RECT  0.06 4.008 1.757 4.08 ;
     RECT  0.084 4.08 1.757 4.104 ;
     RECT  0.06 4.104 1.757 4.176 ;
     RECT  0.084 4.176 1.757 4.2 ;
     RECT  0.06 4.2 1.757 4.272 ;
     RECT  0.084 4.272 1.757 4.296 ;
     RECT  0.06 4.296 1.757 4.368 ;
     RECT  0.084 4.368 1.757 4.392 ;
     RECT  0.06 4.392 1.757 4.464 ;
     RECT  0.084 4.464 1.757 4.488 ;
     RECT  0.06 4.488 1.757 4.56 ;
     RECT  0.084 4.56 1.757 4.584 ;
     RECT  0.06 4.584 1.757 4.656 ;
     RECT  0.084 4.656 1.757 4.68 ;
     RECT  0.06 4.68 1.757 4.752 ;
     RECT  0.084 4.752 1.757 4.776 ;
     RECT  0.06 4.776 1.757 4.848 ;
     RECT  0.084 4.848 1.757 4.872 ;
     RECT  0.06 4.872 1.757 4.944 ;
     RECT  0.084 4.944 1.757 4.968 ;
     RECT  0.06 4.968 1.757 5.04 ;
     RECT  0.084 5.04 1.757 5.064 ;
     RECT  0.06 5.064 1.757 5.136 ;
     RECT  0.084 5.136 1.757 5.16 ;
     RECT  0.06 5.16 1.757 5.232 ;
     RECT  0.084 5.232 1.757 5.256 ;
     RECT  0.06 5.256 1.757 5.328 ;
     RECT  0.084 5.328 1.757 5.352 ;
     RECT  0.06 5.352 1.757 5.424 ;
     RECT  0.084 5.424 1.757 5.448 ;
     RECT  0.06 5.448 1.757 5.52 ;
     RECT  0.084 5.52 1.757 5.544 ;
     RECT  0.06 5.544 1.757 5.616 ;
     RECT  0.084 5.616 1.757 5.64 ;
     RECT  0.06 5.64 1.757 5.712 ;
     RECT  0.084 5.712 1.757 5.736 ;
     RECT  0.06 5.736 1.757 5.808 ;
     RECT  0.084 5.808 1.757 5.832 ;
     RECT  0.06 5.832 1.757 5.904 ;
     RECT  0.084 5.904 1.757 5.928 ;
     RECT  0.06 5.928 1.757 6 ;
     RECT  0.084 6 1.757 6.024 ;
     RECT  0.06 6.024 1.757 6.096 ;
     RECT  0.084 6.096 1.757 6.12 ;
     RECT  0.06 6.12 1.757 6.192 ;
     RECT  0.084 6.192 1.757 6.216 ;
     RECT  0.06 6.216 1.757 6.288 ;
     RECT  0.084 6.288 1.757 6.312 ;
     RECT  0.06 6.312 1.757 6.384 ;
     RECT  0.084 6.384 1.757 6.408 ;
     RECT  0.06 6.408 1.757 6.48 ;
     RECT  0.084 6.48 1.757 6.504 ;
     RECT  0.06 6.504 1.757 6.576 ;
     RECT  0.084 6.576 1.757 6.6 ;
     RECT  0.06 6.6 1.757 6.672 ;
     RECT  0.084 6.672 1.757 6.696 ;
     RECT  0.06 6.696 1.757 6.768 ;
     RECT  0.084 6.768 1.757 6.792 ;
     RECT  0.06 6.792 1.757 6.864 ;
     RECT  0.084 6.864 1.757 6.888 ;
     RECT  0.06 6.888 1.757 6.96 ;
     RECT  0.084 6.96 1.757 6.984 ;
     RECT  0.06 6.984 1.757 7.056 ;
     RECT  0.084 7.056 1.757 7.08 ;
     RECT  0.06 7.08 1.757 7.152 ;
     RECT  0.084 7.152 1.757 7.176 ;
     RECT  0.06 7.176 1.757 7.248 ;
     RECT  0.084 7.248 1.757 7.272 ;
     RECT  0.06 7.272 1.757 7.344 ;
     RECT  0.084 7.344 1.757 7.368 ;
     RECT  0.06 7.368 1.757 7.44 ;
     RECT  0.084 7.44 1.757 7.464 ;
     RECT  0.06 7.464 1.757 7.536 ;
     RECT  0.084 7.536 1.757 7.56 ;
     RECT  0.06 7.56 1.757 7.632 ;
     RECT  0.084 7.632 1.757 7.656 ;
     RECT  0.06 7.656 1.757 7.728 ;
     RECT  0.084 7.728 1.757 7.752 ;
     RECT  0.06 7.752 1.757 7.824 ;
     RECT  0.084 7.824 1.757 7.848 ;
     RECT  0.06 7.848 1.757 7.92 ;
     RECT  0.084 7.92 1.757 7.944 ;
     RECT  0.06 7.944 1.757 8.016 ;
     RECT  0.084 8.016 1.757 8.04 ;
     RECT  0.06 8.04 1.757 8.112 ;
     RECT  0.084 8.112 1.757 8.136 ;
     RECT  0.06 8.136 1.757 8.208 ;
     RECT  0.084 8.208 1.757 8.232 ;
     RECT  0.06 8.232 1.757 8.304 ;
     RECT  0.084 8.304 1.757 8.328 ;
     RECT  0.06 8.328 1.757 8.4 ;
     RECT  0.084 8.4 1.757 8.424 ;
     RECT  0.06 8.424 1.757 8.496 ;
     RECT  0.084 8.496 1.757 8.52 ;
     RECT  0.06 8.52 1.757 8.592 ;
     RECT  0.084 8.592 1.757 8.616 ;
     RECT  0.06 8.616 1.757 8.688 ;
     RECT  0.084 8.688 1.757 8.712 ;
     RECT  0.06 8.712 1.757 8.784 ;
     RECT  0.084 8.784 1.757 8.808 ;
     RECT  0.06 8.808 1.757 8.88 ;
     RECT  0.084 8.88 1.757 8.904 ;
     RECT  0.06 8.904 1.757 8.976 ;
     RECT  0.084 8.976 1.757 9 ;
     RECT  0.06 9 1.757 9.072 ;
     RECT  0.084 9.072 1.757 9.096 ;
     RECT  0.06 9.096 1.757 9.168 ;
     RECT  0.084 9.168 1.757 9.192 ;
     RECT  0.06 9.192 1.757 9.264 ;
     RECT  0.084 9.264 1.757 9.288 ;
     RECT  0.06 9.288 1.757 9.36 ;
     RECT  0.084 9.36 1.757 9.384 ;
     RECT  0.06 9.384 1.757 9.456 ;
     RECT  0.084 9.456 1.757 9.48 ;
     RECT  0.06 9.48 1.757 9.552 ;
     RECT  0.084 9.552 1.757 9.576 ;
     RECT  0.06 9.576 1.757 9.648 ;
     RECT  0.084 9.648 1.757 9.672 ;
     RECT  0.06 9.672 1.757 9.744 ;
     RECT  0.084 9.744 1.757 9.768 ;
     RECT  0.06 9.768 1.757 9.84 ;
     RECT  0.084 9.84 1.757 9.864 ;
     RECT  0.06 9.864 1.757 9.936 ;
     RECT  0.084 9.936 1.757 9.96 ;
     RECT  0.06 9.96 1.757 10.032 ;
     RECT  0.084 10.032 1.757 10.056 ;
     RECT  0.06 10.056 1.757 10.128 ;
     RECT  0.084 10.128 1.757 10.152 ;
     RECT  1.757 1.104 1.793 10.152 ;
     RECT  1.793 1.2 2.408 10.152 ;
     RECT  2.365 11.952 2.408 12.552 ;
     RECT  2.365 14.64 2.408 14.664 ;
     RECT  2.365 16.368 2.408 17.112 ;
     RECT  0.084 20.208 2.408 20.232 ;
     RECT  0.06 20.232 2.408 20.304 ;
     RECT  0.084 20.304 2.408 20.328 ;
     RECT  0.06 20.328 2.408 20.4 ;
     RECT  0.084 20.4 2.408 20.424 ;
     RECT  0.06 20.424 2.408 20.496 ;
     RECT  0.084 20.496 2.408 20.52 ;
     RECT  0.06 20.52 2.408 20.592 ;
     RECT  0.084 20.592 2.408 20.616 ;
     RECT  0.06 20.616 2.408 20.688 ;
     RECT  0.084 20.688 2.408 20.712 ;
     RECT  0.06 20.712 2.408 20.784 ;
     RECT  0.084 20.784 2.408 20.808 ;
     RECT  0.06 20.808 2.408 20.88 ;
     RECT  0.084 20.88 2.408 20.904 ;
     RECT  0.06 20.904 2.408 20.976 ;
     RECT  0.084 20.976 2.408 21 ;
     RECT  0.06 21 2.408 21.072 ;
     RECT  0.084 21.072 2.408 21.096 ;
     RECT  0.06 21.096 2.408 21.168 ;
     RECT  0.084 21.168 2.408 21.192 ;
     RECT  0.06 21.192 2.408 21.264 ;
     RECT  0.084 21.264 2.408 21.288 ;
     RECT  0.06 21.288 2.408 21.36 ;
     RECT  0.084 21.36 2.408 21.384 ;
     RECT  0.06 21.384 2.408 21.456 ;
     RECT  0.084 21.456 2.408 21.48 ;
     RECT  0.06 21.48 2.408 21.552 ;
     RECT  0.084 21.552 2.408 21.576 ;
     RECT  0.06 21.576 2.408 21.648 ;
     RECT  0.084 21.648 2.408 21.672 ;
     RECT  0.06 21.672 2.408 21.744 ;
     RECT  0.084 21.744 2.408 21.768 ;
     RECT  0.06 21.768 2.408 21.84 ;
     RECT  0.084 21.84 2.408 21.864 ;
     RECT  0.06 21.864 2.408 21.936 ;
     RECT  0.084 21.936 2.408 21.96 ;
     RECT  0.06 21.96 2.408 22.032 ;
     RECT  0.084 22.032 2.408 22.056 ;
     RECT  0.06 22.056 2.408 22.128 ;
     RECT  0.084 22.128 2.408 22.152 ;
     RECT  0.06 22.152 2.408 22.224 ;
     RECT  0.084 22.224 2.408 22.248 ;
     RECT  0.06 22.248 2.408 22.32 ;
     RECT  0.084 22.32 2.408 22.344 ;
     RECT  0.06 22.344 2.408 22.416 ;
     RECT  0.084 22.416 2.408 22.44 ;
     RECT  0.06 22.44 2.408 22.512 ;
     RECT  0.084 22.512 2.408 22.536 ;
     RECT  0.06 22.536 2.408 22.608 ;
     RECT  0.084 22.608 2.408 22.632 ;
     RECT  0.06 22.632 2.408 22.704 ;
     RECT  0.084 22.704 2.408 22.728 ;
     RECT  0.06 22.728 2.408 22.8 ;
     RECT  0.084 22.8 2.408 22.824 ;
     RECT  0.06 22.824 2.408 22.896 ;
     RECT  0.084 22.896 2.408 22.92 ;
     RECT  0.06 22.92 2.408 22.992 ;
     RECT  0.084 22.992 2.408 23.016 ;
     RECT  0.06 23.016 2.408 23.088 ;
     RECT  0.084 23.088 2.408 23.112 ;
     RECT  0.06 23.112 2.408 23.184 ;
     RECT  0.084 23.184 2.408 23.208 ;
     RECT  0.06 23.208 2.408 23.28 ;
     RECT  0.084 23.28 2.408 23.304 ;
     RECT  0.06 23.304 2.408 23.376 ;
     RECT  0.084 23.376 2.408 23.4 ;
     RECT  0.06 23.4 2.408 23.472 ;
     RECT  0.084 23.472 2.408 23.496 ;
     RECT  0.06 23.496 2.408 23.568 ;
     RECT  0.084 23.568 2.408 23.592 ;
     RECT  0.06 23.592 2.408 23.664 ;
     RECT  0.084 23.664 2.408 23.688 ;
     RECT  0.06 23.688 2.408 23.76 ;
     RECT  0.084 23.76 2.408 23.784 ;
     RECT  0.06 23.784 2.408 23.856 ;
     RECT  0.084 23.856 2.408 23.88 ;
     RECT  0.06 23.88 2.408 23.952 ;
     RECT  0.084 23.952 2.408 23.976 ;
     RECT  0.06 23.976 2.408 24.048 ;
     RECT  0.084 24.048 2.408 24.072 ;
     RECT  0.06 24.072 2.408 24.144 ;
     RECT  0.084 24.144 2.408 24.168 ;
     RECT  0.06 24.168 2.408 24.24 ;
     RECT  0.084 24.24 2.408 24.264 ;
     RECT  0.06 24.264 2.408 24.336 ;
     RECT  0.084 24.336 2.408 24.36 ;
     RECT  0.06 24.36 2.408 24.432 ;
     RECT  0.084 24.432 2.408 24.456 ;
     RECT  0.06 24.456 2.408 24.528 ;
     RECT  0.084 24.528 2.408 24.552 ;
     RECT  0.06 24.552 2.408 24.624 ;
     RECT  0.084 24.624 2.408 24.648 ;
     RECT  0.06 24.648 2.408 24.72 ;
     RECT  0.084 24.72 2.408 24.744 ;
     RECT  0.06 24.744 2.408 24.816 ;
     RECT  0.084 24.816 2.408 24.84 ;
     RECT  0.06 24.84 2.408 24.912 ;
     RECT  0.084 24.912 2.408 24.936 ;
     RECT  0.06 24.936 2.408 25.008 ;
     RECT  0.084 25.008 2.408 25.032 ;
     RECT  0.06 25.032 2.408 25.104 ;
     RECT  0.084 25.104 2.408 25.128 ;
     RECT  0.06 25.128 2.408 25.2 ;
     RECT  0.084 25.2 2.408 25.224 ;
     RECT  0.06 25.224 2.408 25.296 ;
     RECT  0.084 25.296 2.408 25.32 ;
     RECT  0.06 25.32 2.408 25.392 ;
     RECT  0.084 25.392 2.408 25.416 ;
     RECT  0.06 25.416 2.408 25.488 ;
     RECT  0.084 25.488 2.408 25.512 ;
     RECT  0.06 25.512 2.408 25.584 ;
     RECT  0.084 25.584 2.408 25.608 ;
     RECT  0.06 25.608 2.408 25.68 ;
     RECT  0.084 25.68 2.408 25.704 ;
     RECT  0.06 25.704 2.408 25.776 ;
     RECT  0.084 25.776 2.408 25.8 ;
     RECT  0.06 25.8 2.408 25.872 ;
     RECT  0.084 25.872 2.408 25.896 ;
     RECT  0.06 25.896 2.408 25.968 ;
     RECT  0.084 25.968 2.408 25.992 ;
     RECT  0.06 25.992 2.408 26.064 ;
     RECT  0.084 26.064 2.408 26.088 ;
     RECT  0.06 26.088 2.408 26.16 ;
     RECT  0.084 26.16 2.408 26.184 ;
     RECT  0.06 26.184 2.408 26.256 ;
     RECT  0.084 26.256 2.408 26.28 ;
     RECT  0.06 26.28 2.408 26.352 ;
     RECT  0.084 26.352 2.408 26.376 ;
     RECT  0.06 26.376 2.408 26.448 ;
     RECT  0.084 26.448 2.408 26.472 ;
     RECT  0.06 26.472 2.408 26.544 ;
     RECT  0.084 26.544 2.408 26.568 ;
     RECT  0.06 26.568 2.408 26.64 ;
     RECT  0.084 26.64 2.408 26.664 ;
     RECT  0.06 26.664 2.408 26.736 ;
     RECT  0.084 26.736 2.408 26.76 ;
     RECT  0.06 26.76 2.408 26.832 ;
     RECT  0.084 26.832 2.408 26.856 ;
     RECT  0.06 26.856 2.408 26.928 ;
     RECT  0.084 26.928 2.408 26.952 ;
     RECT  0.06 26.952 2.408 27.024 ;
     RECT  0.084 27.024 2.408 27.048 ;
     RECT  0.06 27.048 2.408 27.12 ;
     RECT  0.084 27.12 2.408 27.144 ;
     RECT  0.06 27.144 2.408 27.216 ;
     RECT  0.084 27.216 2.408 27.24 ;
     RECT  0.06 27.24 2.408 27.312 ;
     RECT  0.084 27.312 2.408 27.336 ;
     RECT  0.06 27.336 2.408 27.408 ;
     RECT  0.084 27.408 2.408 27.432 ;
     RECT  0.06 27.432 2.408 27.504 ;
     RECT  0.084 27.504 2.408 27.528 ;
     RECT  0.06 27.528 2.408 27.6 ;
     RECT  0.084 27.6 2.408 27.624 ;
     RECT  0.06 27.624 2.408 27.696 ;
     RECT  0.084 27.696 2.408 27.72 ;
     RECT  0.06 27.72 2.408 27.792 ;
     RECT  0.084 27.792 2.408 27.816 ;
     RECT  0.06 27.816 2.408 27.888 ;
     RECT  0.084 27.888 2.408 27.912 ;
     RECT  0.06 27.912 2.408 27.984 ;
     RECT  0.084 27.984 2.408 28.008 ;
     RECT  0.06 28.008 2.408 28.08 ;
     RECT  0.084 28.08 2.408 28.104 ;
     RECT  0.06 28.104 2.408 28.176 ;
     RECT  0.084 28.176 2.408 28.2 ;
     RECT  0.06 28.2 2.408 28.272 ;
     RECT  0.084 28.272 2.408 28.296 ;
     RECT  0.06 28.296 2.408 28.368 ;
     RECT  0.084 28.368 2.408 28.392 ;
     RECT  0.06 28.392 2.408 28.464 ;
     RECT  0.084 28.464 2.408 28.488 ;
     RECT  0.06 28.488 2.408 28.56 ;
     RECT  0.084 28.56 2.408 28.584 ;
     RECT  0.06 28.584 2.408 28.656 ;
     RECT  0.084 28.656 2.408 28.68 ;
     RECT  0.06 28.68 2.408 28.752 ;
     RECT  0.084 28.752 2.408 28.776 ;
     RECT  0.06 28.776 2.408 28.848 ;
     RECT  0.084 28.848 2.408 28.872 ;
     RECT  0.06 28.872 2.408 28.944 ;
     RECT  0.084 28.944 2.408 28.968 ;
     RECT  0.06 28.968 2.408 29.04 ;
     RECT  0.084 29.04 2.408 29.064 ;
     RECT  0.06 29.064 2.408 29.136 ;
     RECT  0.084 29.136 2.408 29.16 ;
     RECT  0.06 29.16 2.408 29.232 ;
     RECT  0.084 29.232 2.408 29.256 ;
     RECT  0.06 29.256 2.408 29.328 ;
     RECT  0.084 29.328 2.408 29.352 ;
     RECT  2.365 33.024 2.408 33.048 ;
     RECT  2.365 36 2.408 36.936 ;
     RECT  2.365 39.072 2.408 39.096 ;
     RECT  2.365 41.664 2.408 42.6 ;
     RECT  2.365 46.8 2.408 46.824 ;
     RECT  2.365 48.96 2.408 48.984 ;
     RECT  2.365 60.576 2.408 60.6 ;
     RECT  2.365 63.264 2.408 63.288 ;
     RECT  0.084 64.752 2.408 64.776 ;
     RECT  0.06 64.776 2.408 64.848 ;
     RECT  0.084 64.848 2.408 64.872 ;
     RECT  0.06 64.872 2.408 64.944 ;
     RECT  0.084 64.944 2.408 64.968 ;
     RECT  0.06 64.968 2.408 65.04 ;
     RECT  0.084 65.04 2.408 65.064 ;
     RECT  0.06 65.064 2.408 65.136 ;
     RECT  0.084 65.136 2.408 65.16 ;
     RECT  0.06 65.16 2.408 65.232 ;
     RECT  0.084 65.232 2.408 65.256 ;
     RECT  0.06 65.256 2.408 65.328 ;
     RECT  0.084 65.328 2.408 65.352 ;
     RECT  0.06 65.352 2.408 65.424 ;
     RECT  0.084 65.424 2.408 65.448 ;
     RECT  0.06 65.448 2.408 65.52 ;
     RECT  0.084 65.52 2.408 65.544 ;
     RECT  0.06 65.544 2.408 65.616 ;
     RECT  0.084 65.616 2.408 65.64 ;
     RECT  0.06 65.64 2.408 65.712 ;
     RECT  0.084 65.712 2.408 65.736 ;
     RECT  0.06 65.736 2.408 65.808 ;
     RECT  0.084 65.808 2.408 65.832 ;
     RECT  0.06 65.832 2.408 65.904 ;
     RECT  0.084 65.904 2.408 65.928 ;
     RECT  0.06 65.928 2.408 66 ;
     RECT  0.084 66 2.408 66.024 ;
     RECT  0.06 66.024 2.408 66.096 ;
     RECT  0.084 66.096 2.408 66.12 ;
     RECT  0.06 66.12 2.408 66.192 ;
     RECT  0.084 66.192 2.408 66.216 ;
     RECT  0.06 66.216 2.408 66.288 ;
     RECT  0.084 66.288 2.408 66.312 ;
     RECT  0.06 66.312 2.408 66.384 ;
     RECT  0.084 66.384 2.408 66.408 ;
     RECT  0.06 66.408 2.408 66.48 ;
     RECT  0.084 66.48 2.408 66.504 ;
     RECT  0.06 66.504 2.408 66.576 ;
     RECT  0.084 66.576 2.408 66.6 ;
     RECT  0.06 66.6 2.408 66.672 ;
     RECT  0.084 66.672 2.408 66.696 ;
     RECT  0.06 66.696 2.408 66.768 ;
     RECT  0.084 66.768 2.408 66.792 ;
     RECT  0.06 66.792 2.408 66.864 ;
     RECT  0.084 66.864 2.408 66.888 ;
     RECT  0.06 66.888 2.408 66.96 ;
     RECT  0.084 66.96 2.408 66.984 ;
     RECT  0.06 66.984 2.408 67.056 ;
     RECT  0.084 67.056 2.408 67.08 ;
     RECT  0.06 67.08 2.408 67.152 ;
     RECT  0.084 67.152 2.408 67.176 ;
     RECT  0.06 67.176 2.408 67.248 ;
     RECT  0.084 67.248 2.408 67.272 ;
     RECT  0.06 67.272 2.408 67.344 ;
     RECT  0.084 67.344 2.408 67.368 ;
     RECT  0.06 67.368 2.408 67.44 ;
     RECT  0.084 67.44 2.408 67.464 ;
     RECT  0.06 67.464 2.408 67.536 ;
     RECT  0.084 67.536 2.408 67.56 ;
     RECT  0.06 67.56 2.408 67.632 ;
     RECT  0.084 67.632 2.408 67.656 ;
     RECT  0.06 67.656 2.408 67.728 ;
     RECT  0.084 67.728 2.408 67.752 ;
     RECT  2.365 71.088 2.408 71.112 ;
     RECT  2.408 1.2 2.512 75.612 ;
     RECT  2.512 1.2 2.704 75.342 ;
     RECT  2.704 40.944 2.819 44.52 ;
     RECT  2.704 20.304 2.837 29.256 ;
     RECT  2.704 64.944 2.837 68.952 ;
     RECT  2.704 14.64 2.909 17.496 ;
     RECT  2.819 41.088 2.909 44.52 ;
     RECT  2.704 11.952 2.981 12.888 ;
     RECT  2.704 35.28 2.981 36.936 ;
     RECT  2.909 14.64 3.045 16.392 ;
     RECT  3.045 14.64 3.053 15.864 ;
     RECT  2.837 65.088 3.125 68.952 ;
     RECT  2.909 41.136 3.197 44.52 ;
     RECT  2.704 62.784 3.197 63.288 ;
     RECT  2.704 1.2 3.443 10.824 ;
     RECT  2.837 20.88 3.449 29.256 ;
     RECT  2.981 36 3.449 36.936 ;
     RECT  3.443 9.888 3.629 10.824 ;
     RECT  3.197 42.576 3.629 44.52 ;
     RECT  2.704 32.544 3.665 33.432 ;
     RECT  2.704 58.656 3.683 60.6 ;
     RECT  2.981 12.528 3.697 12.888 ;
     RECT  2.704 38.16 3.701 39.096 ;
     RECT  2.704 46.224 3.733 49.08 ;
     RECT  2.704 50.16 3.733 51.528 ;
     RECT  2.909 17.472 3.737 17.496 ;
     RECT  3.697 12.528 3.769 13.32 ;
     RECT  3.053 14.64 3.769 14.664 ;
     RECT  3.733 46.224 3.769 51.528 ;
     RECT  3.683 58.656 3.805 58.824 ;
     RECT  3.125 68.928 3.805 68.952 ;
     RECT  2.704 71.088 3.805 71.112 ;
     RECT  2.704 55.92 3.841 55.944 ;
     RECT  3.805 71.088 3.845 71.256 ;
     RECT  2.704 31.344 3.877 31.368 ;
     RECT  2.704 57.312 3.877 57.384 ;
     RECT  3.805 58.56 3.877 58.824 ;
     RECT  3.665 32.736 3.949 33.432 ;
     RECT  3.845 71.232 3.949 71.256 ;
     RECT  3.877 57.312 3.985 58.824 ;
     RECT  3.449 20.88 4.021 28.776 ;
     RECT  4.021 19.968 4.061 28.776 ;
     RECT  3.197 41.136 4.061 41.544 ;
     RECT  3.629 42.72 4.061 44.52 ;
     RECT  3.197 62.976 4.093 63.288 ;
     RECT  3.949 71.232 4.133 71.88 ;
     RECT  3.769 12.528 4.165 14.664 ;
     RECT  4.061 41.136 4.165 41.496 ;
     RECT  4.133 71.712 4.165 71.88 ;
     RECT  2.704 72.912 4.165 72.936 ;
     RECT  4.165 12.528 4.169 14.808 ;
     RECT  4.061 25.44 4.169 28.776 ;
     RECT  3.769 46.224 4.169 52.488 ;
     RECT  4.169 12.528 4.201 13.704 ;
     RECT  4.169 46.512 4.211 52.056 ;
     RECT  2.704 54.096 4.237 54.12 ;
     RECT  4.237 54.096 4.261 54.216 ;
     RECT  3.841 55.872 4.307 55.944 ;
     RECT  4.169 14.784 4.313 14.808 ;
     RECT  4.061 43.536 4.313 44.52 ;
     RECT  3.125 65.088 4.453 67.848 ;
     RECT  3.443 1.2 4.46 8.856 ;
     RECT  3.629 9.888 4.46 10.248 ;
     RECT  4.201 11.952 4.489 13.704 ;
     RECT  4.169 26.016 4.525 28.776 ;
     RECT  4.211 46.8 4.529 52.056 ;
     RECT  3.053 15.84 4.561 15.864 ;
     RECT  3.701 38.448 4.597 39.096 ;
     RECT  4.165 40.752 4.597 41.496 ;
     RECT  4.313 44.304 4.601 44.52 ;
     RECT  4.453 65.088 4.673 67.896 ;
     RECT  4.597 38.448 4.701 41.496 ;
     RECT  4.673 66.336 4.705 67.896 ;
     RECT  3.805 68.928 4.705 69.576 ;
     RECT  4.701 39.888 4.709 41.496 ;
     RECT  4.673 65.088 4.709 65.304 ;
     RECT  3.683 59.856 4.741 60.6 ;
     RECT  4.165 61.728 4.741 61.752 ;
     RECT  4.705 66.336 4.745 69.576 ;
     RECT  3.985 57.264 4.748 58.824 ;
     RECT  4.748 57.024 4.777 58.824 ;
     RECT  4.741 59.856 4.777 61.752 ;
     RECT  2.704 74.064 4.789 74.088 ;
     RECT  2.704 18.768 4.813 18.792 ;
     RECT  4.061 19.968 4.813 24.36 ;
     RECT  4.307 55.92 4.849 55.944 ;
     RECT  4.777 57.024 4.849 61.752 ;
     RECT  4.093 62.976 4.849 63.576 ;
     RECT  4.709 65.088 4.849 65.208 ;
     RECT  4.261 54.096 4.957 54.36 ;
     RECT  4.745 68.352 4.957 69.576 ;
     RECT  4.561 15.84 4.988 16.008 ;
     RECT  4.849 55.92 4.993 61.752 ;
     RECT  4.849 62.976 4.993 65.208 ;
     RECT  4.46 1.2 4.997 10.248 ;
     RECT  4.993 55.92 4.997 65.208 ;
     RECT  3.877 30.864 5.029 31.368 ;
     RECT  3.949 32.736 5.029 34.488 ;
     RECT  4.997 56.592 5.075 65.208 ;
     RECT  4.525 26.016 5.077 28.968 ;
     RECT  5.029 30.24 5.077 34.584 ;
     RECT  5.077 30.24 5.101 34.632 ;
     RECT  4.489 11.76 5.137 13.704 ;
     RECT  3.449 36.912 5.137 36.936 ;
     RECT  5.101 30 5.173 34.632 ;
     RECT  4.988 15.84 5.177 16.824 ;
     RECT  4.957 53.616 5.209 54.36 ;
     RECT  5.075 56.592 5.213 63.336 ;
     RECT  5.075 64.32 5.213 65.208 ;
     RECT  4.529 47.28 5.249 52.056 ;
     RECT  4.789 74.064 5.281 74.136 ;
     RECT  4.165 71.712 5.285 72.936 ;
     RECT  5.249 48.432 5.317 52.056 ;
     RECT  5.209 53.04 5.317 54.36 ;
     RECT  4.813 18.768 5.324 24.36 ;
     RECT  4.997 1.2 5.357 7.896 ;
     RECT  5.317 48.432 5.363 54.36 ;
     RECT  5.285 72.864 5.389 72.936 ;
     RECT  5.281 74.016 5.389 74.136 ;
     RECT  5.077 26.016 5.411 29.016 ;
     RECT  5.177 15.984 5.461 16.824 ;
     RECT  5.137 11.76 5.497 13.896 ;
     RECT  5.324 18.576 5.501 24.36 ;
     RECT  4.701 38.448 5.573 38.472 ;
     RECT  4.957 68.352 5.573 70.296 ;
     RECT  5.497 11.52 5.605 13.896 ;
     RECT  5.411 26.64 5.605 29.016 ;
     RECT  5.173 30 5.605 34.776 ;
     RECT  5.213 57.36 5.617 63.336 ;
     RECT  5.137 36.912 5.641 37.32 ;
     RECT  5.605 26.64 5.645 34.776 ;
     RECT  4.601 44.304 5.713 44.328 ;
     RECT  5.501 24.288 5.749 24.36 ;
     RECT  4.745 66.336 5.749 67.224 ;
     RECT  5.645 26.64 5.753 34.584 ;
     RECT  5.573 68.976 5.753 70.296 ;
     RECT  5.285 71.712 5.789 71.736 ;
     RECT  5.605 11.52 5.857 14.232 ;
     RECT  5.501 18.576 5.857 23.304 ;
     RECT  5.641 36.48 5.857 37.32 ;
     RECT  4.709 39.888 5.857 39.912 ;
     RECT  5.749 24.288 5.861 25.08 ;
     RECT  5.753 26.64 5.861 33.912 ;
     RECT  5.861 24.336 5.933 25.08 ;
     RECT  5.857 35.904 5.941 37.32 ;
     RECT  5.713 42.528 5.965 42.552 ;
     RECT  5.713 43.632 5.965 44.328 ;
     RECT  5.357 1.296 6.001 7.896 ;
     RECT  4.997 9.072 6.001 10.248 ;
     RECT  5.861 26.88 6.005 33.912 ;
     RECT  5.857 18.192 6.028 23.304 ;
     RECT  5.857 11.472 6.037 14.232 ;
     RECT  6.005 29.328 6.041 33.912 ;
     RECT  5.749 66.336 6.113 67.272 ;
     RECT  5.249 47.28 6.145 47.352 ;
     RECT  5.389 72.864 6.145 74.136 ;
     RECT  6.037 11.424 6.181 14.232 ;
     RECT  5.941 36.384 6.181 37.32 ;
     RECT  6.001 1.296 6.221 10.248 ;
     RECT  6.221 6.24 6.365 10.248 ;
     RECT  4.709 40.944 6.369 41.496 ;
     RECT  5.965 42.528 6.369 44.328 ;
     RECT  5.363 48.72 6.371 54.36 ;
     RECT  5.617 57.36 6.397 58.488 ;
     RECT  5.617 59.616 6.397 63.336 ;
     RECT  5.213 64.32 6.397 65.16 ;
     RECT  6.073 70.464 6.397 70.632 ;
     RECT  6.369 40.944 6.419 44.328 ;
     RECT  6.371 48.72 6.433 51.768 ;
     RECT  6.145 46.512 6.437 47.352 ;
     RECT  6.145 72.864 6.505 74.664 ;
     RECT  6.028 18.576 6.545 23.304 ;
     RECT  6.433 48.672 6.545 51.768 ;
     RECT  6.371 52.944 6.572 54.36 ;
     RECT  6.109 56.016 6.572 56.04 ;
     RECT  5.857 39.6 6.577 39.912 ;
     RECT  6.419 40.944 6.577 42.6 ;
     RECT  6.545 18.768 6.581 23.304 ;
     RECT  6.397 57.072 6.613 58.488 ;
     RECT  6.581 19.248 6.617 23.304 ;
     RECT  6.617 22.656 6.685 23.304 ;
     RECT  5.753 68.976 6.685 69 ;
     RECT  6.685 68.496 6.725 69 ;
     RECT  5.933 25.056 6.757 25.08 ;
     RECT  6.577 39.6 6.803 42.6 ;
     RECT  6.365 9.696 6.853 10.248 ;
     RECT  6.181 11.424 6.853 14.76 ;
     RECT  6.041 30.72 6.853 33.912 ;
     RECT  6.613 57.024 6.865 58.488 ;
     RECT  6.397 59.616 6.865 65.16 ;
     RECT  6.853 30.72 6.901 34.056 ;
     RECT  6.181 36.384 6.901 37.416 ;
     RECT  6.803 39.6 6.901 40.152 ;
     RECT  6.545 48.672 6.901 50.616 ;
     RECT  6.725 68.496 6.973 68.52 ;
     RECT  6.005 27.36 7.009 28.248 ;
     RECT  6.041 29.328 7.009 29.352 ;
     RECT  6.397 70.464 7.009 71.208 ;
     RECT  6.685 22.656 7.045 23.352 ;
     RECT  6.419 43.584 7.153 44.328 ;
     RECT  7.153 43.584 7.189 44.376 ;
     RECT  6.572 52.944 7.189 56.04 ;
     RECT  6.865 57.024 7.189 65.16 ;
     RECT  6.505 72.528 7.369 74.664 ;
     RECT  6.803 41.136 7.397 42.6 ;
     RECT  7.189 43.584 7.397 44.664 ;
     RECT  6.901 36.384 7.477 40.152 ;
     RECT  6.221 1.296 7.513 5.208 ;
     RECT  6.365 6.24 7.513 8.568 ;
     RECT  6.973 68.4 7.525 68.52 ;
     RECT  6.757 25.056 7.549 25.224 ;
     RECT  7.397 41.136 7.573 44.664 ;
     RECT  7.009 27.36 7.621 29.352 ;
     RECT  6.437 46.752 7.621 47.352 ;
     RECT  7.369 72.384 7.621 74.664 ;
     RECT  6.113 66.72 7.669 67.272 ;
     RECT  7.525 68.352 7.669 68.52 ;
     RECT  7.045 22.656 7.765 23.448 ;
     RECT  7.549 24.96 7.765 25.224 ;
     RECT  7.669 66.72 7.801 68.52 ;
     RECT  7.009 69.552 7.801 71.208 ;
     RECT  7.513 1.296 7.808 8.568 ;
     RECT  6.853 9.696 7.808 14.76 ;
     RECT  5.461 15.984 7.808 16.92 ;
     RECT  7.729 18.24 7.808 18.264 ;
     RECT  6.617 19.248 7.808 21.672 ;
     RECT  7.765 22.656 7.808 25.224 ;
     RECT  7.621 26.688 7.808 29.352 ;
     RECT  6.901 30.72 7.808 34.872 ;
     RECT  7.477 36.288 7.808 40.152 ;
     RECT  7.573 41.136 7.808 45.048 ;
     RECT  7.621 46.512 7.808 47.352 ;
     RECT  6.901 48.48 7.808 50.616 ;
     RECT  6.545 51.744 7.808 51.768 ;
     RECT  7.189 52.944 7.808 65.16 ;
     RECT  7.801 66.72 7.808 71.208 ;
     RECT  7.621 72.384 7.808 75.24 ;
     RECT  7.808 1.296 7.912 75.612 ;
     RECT  7.912 1.296 8.104 75.342 ;
     RECT  8.104 19.248 8.237 34.392 ;
     RECT  8.104 67.968 8.243 71.112 ;
     RECT  8.104 1.296 8.309 6.12 ;
     RECT  8.104 41.088 8.345 54.648 ;
     RECT  8.104 55.824 8.435 65.64 ;
     RECT  8.309 1.296 8.453 4.776 ;
     RECT  8.104 8.544 8.525 8.568 ;
     RECT  8.345 41.088 8.531 49.032 ;
     RECT  8.453 1.296 8.633 4.152 ;
     RECT  8.237 19.248 8.633 33.624 ;
     RECT  8.104 39.888 8.633 39.912 ;
     RECT  8.104 72.432 8.633 75.24 ;
     RECT  8.243 67.968 8.669 68.76 ;
     RECT  8.633 3.408 8.705 4.152 ;
     RECT  8.531 42.576 8.705 49.032 ;
     RECT  8.345 50.064 8.771 54.648 ;
     RECT  8.104 9.552 8.813 14.76 ;
     RECT  8.633 1.296 8.849 1.704 ;
     RECT  8.104 15.84 8.993 16.68 ;
     RECT  8.705 44.928 9.011 49.032 ;
     RECT  8.771 50.064 9.011 51.24 ;
     RECT  8.705 4.128 9.065 4.152 ;
     RECT  8.104 38.64 9.065 38.856 ;
     RECT  8.104 17.76 9.097 18.264 ;
     RECT  8.633 19.248 9.097 25.224 ;
     RECT  8.104 36.096 9.097 36.312 ;
     RECT  8.633 26.352 9.101 33.624 ;
     RECT  9.097 35.856 9.109 37.08 ;
     RECT  8.849 1.68 9.137 1.704 ;
     RECT  9.101 26.784 9.137 33.624 ;
     RECT  8.633 72.432 9.137 75.192 ;
     RECT  9.137 28.128 9.205 33.624 ;
     RECT  9.065 38.64 9.209 38.808 ;
     RECT  9.097 17.76 9.241 25.224 ;
     RECT  9.011 50.16 9.281 51.24 ;
     RECT  9.109 35.856 9.313 37.176 ;
     RECT  8.813 14.736 9.317 14.76 ;
     RECT  8.771 52.416 9.349 54.648 ;
     RECT  8.435 55.824 9.349 65.352 ;
     RECT  8.243 70.08 9.385 71.112 ;
     RECT  9.385 70.08 9.389 71.304 ;
     RECT  8.813 9.552 9.443 13.512 ;
     RECT  9.377 7.44 9.461 7.464 ;
     RECT  8.993 15.84 9.461 16.584 ;
     RECT  8.531 41.088 9.529 41.448 ;
     RECT  8.104 66.624 9.529 66.792 ;
     RECT  8.669 67.968 9.529 68.52 ;
     RECT  9.349 52.416 9.565 65.352 ;
     RECT  9.443 9.552 9.601 13.464 ;
     RECT  9.011 44.928 9.635 48.936 ;
     RECT  9.241 17.712 9.637 25.224 ;
     RECT  9.205 28.128 9.685 34.344 ;
     RECT  9.313 35.856 9.685 37.656 ;
     RECT  8.309 6.096 9.745 6.12 ;
     RECT  8.705 42.576 9.745 43.656 ;
     RECT  9.745 5.712 9.785 6.12 ;
     RECT  9.529 41.088 9.817 41.544 ;
     RECT  9.745 42.576 9.817 43.704 ;
     RECT  9.137 72.816 9.817 75.192 ;
     RECT  9.685 28.128 9.821 37.656 ;
     RECT  9.529 66.624 9.821 68.52 ;
     RECT  9.565 52.416 9.829 65.544 ;
     RECT  9.817 41.088 9.853 43.8 ;
     RECT  9.635 44.928 9.853 46.872 ;
     RECT  9.829 52.032 9.853 65.544 ;
     RECT  9.821 66.624 9.853 66.744 ;
     RECT  9.461 15.84 9.884 16.152 ;
     RECT  9.853 52.032 9.916 66.744 ;
     RECT  9.853 41.088 9.925 46.872 ;
     RECT  9.916 52.512 9.929 66.744 ;
     RECT  9.929 52.512 9.965 66.648 ;
     RECT  9.884 15.072 9.971 16.152 ;
     RECT  9.853 2.88 10.069 2.904 ;
     RECT  9.389 71.184 10.069 71.304 ;
     RECT  9.821 35.856 10.109 37.656 ;
     RECT  9.925 41.04 10.217 46.872 ;
     RECT  9.635 47.904 10.253 48.936 ;
     RECT  10.217 41.04 10.259 46.344 ;
     RECT  9.821 68.16 10.289 68.52 ;
     RECT  10.259 41.04 10.325 41.736 ;
     RECT  10.069 71.184 10.393 71.688 ;
     RECT  9.817 72.816 10.393 75.288 ;
     RECT  10.253 48.912 10.397 48.936 ;
     RECT  9.209 38.64 10.429 38.664 ;
     RECT  10.109 36.864 10.469 37.656 ;
     RECT  9.637 17.712 10.501 25.752 ;
     RECT  9.821 28.128 10.501 34.344 ;
     RECT  9.601 9.504 10.573 13.464 ;
     RECT  10.501 17.664 10.573 25.752 ;
     RECT  9.137 26.784 10.573 26.808 ;
     RECT  9.389 70.08 10.573 70.104 ;
     RECT  10.573 9.504 10.577 13.704 ;
     RECT  10.573 17.664 10.609 26.808 ;
     RECT  10.501 27.84 10.609 34.344 ;
     RECT  10.325 41.04 10.613 41.448 ;
     RECT  10.577 9.6 10.645 13.704 ;
     RECT  10.249 7.488 10.717 7.512 ;
     RECT  10.609 17.664 10.717 34.344 ;
     RECT  10.717 7.488 10.753 7.944 ;
     RECT  9.965 52.992 10.757 66.648 ;
     RECT  10.753 7.488 10.789 8.52 ;
     RECT  9.971 15.264 10.789 16.152 ;
     RECT  10.717 17.472 10.789 34.344 ;
     RECT  10.429 38.64 10.825 39.048 ;
     RECT  10.757 52.992 10.829 66.456 ;
     RECT  10.069 2.88 10.861 3.48 ;
     RECT  9.853 4.56 10.861 4.584 ;
     RECT  10.789 7.392 10.901 8.52 ;
     RECT  9.785 5.712 10.969 5.736 ;
     RECT  10.573 69.504 10.969 70.104 ;
     RECT  10.393 71.184 10.969 75.288 ;
     RECT  10.259 42.72 11.009 46.008 ;
     RECT  10.469 37.104 11.077 37.656 ;
     RECT  10.825 38.64 11.077 39.48 ;
     RECT  10.289 68.16 11.077 68.184 ;
     RECT  10.969 69.504 11.117 75.288 ;
     RECT  10.829 52.992 11.125 66.36 ;
     RECT  10.861 2.88 11.149 4.584 ;
     RECT  10.969 5.712 11.149 6.36 ;
     RECT  10.789 15.264 11.185 34.344 ;
     RECT  11.125 52.128 11.212 66.36 ;
     RECT  11.185 15.264 11.257 34.392 ;
     RECT  9.281 50.16 11.257 50.76 ;
     RECT  11.077 67.872 11.257 68.184 ;
     RECT  11.212 52.992 11.261 66.36 ;
     RECT  11.149 2.88 11.365 6.36 ;
     RECT  10.901 7.392 11.365 7.944 ;
     RECT  11.365 2.88 11.405 7.944 ;
     RECT  11.117 69.504 11.405 70.008 ;
     RECT  11.117 71.28 11.405 75.288 ;
     RECT  10.613 41.04 11.44 41.064 ;
     RECT  11.44 40.992 11.441 41.064 ;
     RECT  11.405 71.664 11.441 75.288 ;
     RECT  11.009 44.064 11.459 46.008 ;
     RECT  11.42 48.96 11.461 48.984 ;
     RECT  11.257 50.16 11.461 51.576 ;
     RECT  11.459 45.168 11.473 46.008 ;
     RECT  10.253 47.904 11.473 47.928 ;
     RECT  11.473 47.664 11.509 47.928 ;
     RECT  11.405 5.136 11.513 7.944 ;
     RECT  11.261 52.992 11.513 65.976 ;
     RECT  11.473 45.168 11.545 46.248 ;
     RECT  11.509 47.28 11.545 47.928 ;
     RECT  11.545 45.168 11.555 47.928 ;
     RECT  11.077 37.104 11.585 39.48 ;
     RECT  10.109 35.856 11.621 35.88 ;
     RECT  11.257 67.776 11.653 68.184 ;
     RECT  11.513 5.136 11.657 7.656 ;
     RECT  11.657 5.232 11.699 7.656 ;
     RECT  11.441 75.024 11.729 75.048 ;
     RECT  10.645 9.6 11.869 14.088 ;
     RECT  11.405 2.88 11.905 4.152 ;
     RECT  11.555 45.504 11.945 47.928 ;
     RECT  11.513 52.992 11.945 65.928 ;
     RECT  11.945 45.504 11.981 47.688 ;
     RECT  11.905 2.832 12.017 4.152 ;
     RECT  11.869 36.048 12.085 36.072 ;
     RECT  11.585 37.104 12.085 39.096 ;
     RECT  11.441 40.992 12.089 41.016 ;
     RECT  11.653 67.776 12.131 68.232 ;
     RECT  11.257 15.264 12.161 34.584 ;
     RECT  12.161 15.264 12.179 34.248 ;
     RECT  11.405 69.984 12.229 70.008 ;
     RECT  11.009 42.72 12.517 42.744 ;
     RECT  11.461 48.96 12.517 51.576 ;
     RECT  11.945 52.992 12.517 65.688 ;
     RECT  11.441 71.664 12.517 73.848 ;
     RECT  12.517 48.96 12.553 65.688 ;
     RECT  12.131 67.872 12.589 68.232 ;
     RECT  12.229 69.984 12.697 70.104 ;
     RECT  12.517 71.664 12.733 73.896 ;
     RECT  11.699 6.288 12.769 7.656 ;
     RECT  12.589 67.872 12.769 68.952 ;
     RECT  12.697 69.984 12.769 70.68 ;
     RECT  12.017 3.456 12.841 4.152 ;
     RECT  11.699 5.232 12.841 5.256 ;
     RECT  12.085 36.048 12.913 39.096 ;
     RECT  12.517 42.288 12.949 42.744 ;
     RECT  12.841 3.456 13.093 5.256 ;
     RECT  12.949 42.288 13.093 42.792 ;
     RECT  11.981 45.792 13.093 47.688 ;
     RECT  13.093 3.312 13.208 5.256 ;
     RECT  12.769 6.288 13.208 8.04 ;
     RECT  11.869 9.6 13.208 14.232 ;
     RECT  12.179 15.264 13.208 33.96 ;
     RECT  12.913 36.048 13.208 39.768 ;
     RECT  12.661 40.944 13.208 40.968 ;
     RECT  13.093 42.288 13.208 43.368 ;
     RECT  13.021 44.448 13.208 44.472 ;
     RECT  13.093 45.696 13.208 47.688 ;
     RECT  12.553 48.72 13.208 65.688 ;
     RECT  12.697 66.816 13.208 66.84 ;
     RECT  12.769 67.872 13.208 70.68 ;
     RECT  12.733 71.664 13.208 74.712 ;
     RECT  13.208 2.148 13.312 75.612 ;
     RECT  13.312 2.256 13.504 75.342 ;
     RECT  13.504 6.384 13.529 16.296 ;
     RECT  13.504 2.256 13.619 5.016 ;
     RECT  13.504 39.744 13.709 75.288 ;
     RECT  13.504 17.472 13.853 34.584 ;
     RECT  13.619 2.88 13.997 5.016 ;
     RECT  13.709 39.744 14.105 42.888 ;
     RECT  13.853 30.192 14.147 34.584 ;
     RECT  13.709 44.112 14.177 75.288 ;
     RECT  13.529 6.384 14.329 14.664 ;
     RECT  13.997 3.312 14.429 5.016 ;
     RECT  13.529 15.84 14.641 16.296 ;
     RECT  13.853 17.472 14.641 29.112 ;
     RECT  13.504 35.712 14.641 38.232 ;
     RECT  14.641 35.712 14.713 38.712 ;
     RECT  14.177 52.8 14.825 75.288 ;
     RECT  14.429 3.408 14.867 5.016 ;
     RECT  14.329 6.384 14.867 8.568 ;
     RECT  14.867 6.384 14.897 8.52 ;
     RECT  14.641 15.84 14.933 29.112 ;
     RECT  14.105 39.888 14.965 42.888 ;
     RECT  14.177 44.112 14.965 51.48 ;
     RECT  14.713 35.52 14.969 38.712 ;
     RECT  14.933 15.84 15.005 25.56 ;
     RECT  14.329 9.648 15.145 14.664 ;
     RECT  15.145 9.648 15.181 14.76 ;
     RECT  15.005 15.84 15.181 25.512 ;
     RECT  14.933 26.688 15.217 29.112 ;
     RECT  14.825 66.576 15.257 75.288 ;
     RECT  15.217 26.688 15.325 29.16 ;
     RECT  14.147 30.192 15.325 34.392 ;
     RECT  14.867 3.648 15.329 5.016 ;
     RECT  14.897 6.816 15.329 8.52 ;
     RECT  14.825 52.8 15.365 65.496 ;
     RECT  14.965 39.888 15.469 51.48 ;
     RECT  15.329 4.656 15.473 5.016 ;
     RECT  15.257 66.576 15.473 75 ;
     RECT  15.325 26.688 15.649 34.392 ;
     RECT  14.969 36.24 15.685 38.712 ;
     RECT  15.469 39.888 15.685 51.624 ;
     RECT  15.685 36.24 15.721 51.624 ;
     RECT  15.365 52.8 15.721 55.56 ;
     RECT  15.473 66.576 15.797 74.904 ;
     RECT  15.721 36.24 15.869 55.56 ;
     RECT  15.797 66.576 15.901 70.584 ;
     RECT  15.181 9.648 15.937 25.512 ;
     RECT  15.365 56.592 15.973 65.496 ;
     RECT  15.901 66.528 15.973 70.584 ;
     RECT  15.937 9.552 16.045 25.512 ;
     RECT  15.649 26.688 16.045 34.92 ;
     RECT  15.329 3.648 16.085 3.672 ;
     RECT  15.869 37.584 16.405 55.56 ;
     RECT  15.973 56.592 16.405 70.584 ;
     RECT  15.329 6.816 16.409 7.416 ;
     RECT  15.797 71.664 16.477 74.904 ;
     RECT  16.409 7.152 16.549 7.416 ;
     RECT  15.329 8.496 16.549 8.52 ;
     RECT  15.473 4.656 16.693 4.68 ;
     RECT  16.549 7.152 16.697 8.52 ;
     RECT  16.045 9.552 17.017 35.256 ;
     RECT  15.869 36.24 17.017 36.6 ;
     RECT  16.405 37.584 17.017 70.584 ;
     RECT  16.693 4.608 17.089 4.68 ;
     RECT  17.089 3.936 17.173 4.68 ;
     RECT  17.173 4.416 17.221 4.68 ;
     RECT  17.017 9.552 17.273 70.584 ;
     RECT  17.273 9.552 17.345 68.184 ;
     RECT  17.273 69.264 17.417 70.584 ;
     RECT  17.345 51.072 17.453 68.184 ;
     RECT  16.477 71.664 17.485 75.144 ;
     RECT  17.221 4.416 17.509 5.448 ;
     RECT  17.509 4.416 17.596 6.024 ;
     RECT  16.697 7.392 17.633 8.52 ;
     RECT  17.633 7.968 17.756 8.52 ;
     RECT  17.345 9.552 17.756 50.088 ;
     RECT  17.453 51.072 18.421 65.784 ;
     RECT  17.453 67.008 18.421 68.184 ;
     RECT  17.417 69.264 18.449 70.392 ;
     RECT  17.485 71.52 18.449 75.144 ;
     RECT  17.596 4.416 18.608 5.448 ;
     RECT  17.917 6.816 18.608 6.936 ;
     RECT  17.756 7.968 18.608 50.088 ;
     RECT  18.421 51.072 18.608 68.184 ;
     RECT  18.449 69.264 18.608 75.144 ;
     RECT  18.608 2.148 18.712 75.612 ;
     RECT  18.712 2.418 18.904 75.432 ;
     RECT  18.904 2.688 19.145 36.6 ;
     RECT  19.145 2.688 19.715 34.2 ;
     RECT  19.715 2.688 19.721 7.464 ;
     RECT  19.715 8.544 19.937 34.2 ;
     RECT  19.145 35.232 20.005 36.6 ;
     RECT  18.904 37.584 20.005 75.432 ;
     RECT  19.937 8.544 20.009 33.96 ;
     RECT  19.721 2.688 20.045 7.416 ;
     RECT  20.045 4.512 20.081 7.416 ;
     RECT  20.045 2.688 20.153 3.144 ;
     RECT  20.005 35.232 20.297 75.432 ;
     RECT  20.081 4.8 20.477 7.416 ;
     RECT  20.009 25.968 20.801 33.96 ;
     RECT  20.297 36.336 20.837 38.232 ;
     RECT  20.297 39.792 21.017 75.432 ;
     RECT  20.477 5.184 21.049 7.416 ;
     RECT  20.009 8.544 21.049 24.792 ;
     RECT  21.017 39.792 21.053 72.264 ;
     RECT  21.053 40.56 21.125 72.264 ;
     RECT  21.017 73.344 21.125 75.432 ;
     RECT  21.049 5.184 21.169 24.792 ;
     RECT  21.169 9.648 21.233 24.792 ;
     RECT  20.801 26.208 21.233 33.96 ;
     RECT  21.125 69.264 21.269 72.264 ;
     RECT  20.153 2.688 21.517 3 ;
     RECT  21.517 2.688 21.553 3.72 ;
     RECT  20.837 37.008 21.553 38.232 ;
     RECT  21.397 39.504 21.553 39.528 ;
     RECT  21.553 37.008 21.593 39.528 ;
     RECT  21.125 40.56 21.593 68.184 ;
     RECT  21.553 2.352 21.625 3.72 ;
     RECT  21.169 5.184 21.625 8.376 ;
     RECT  21.125 73.344 21.665 74.76 ;
     RECT  21.269 69.264 21.683 71.592 ;
     RECT  21.233 26.4 21.701 33.96 ;
     RECT  21.625 2.352 21.733 8.376 ;
     RECT  21.701 31.152 21.949 33.96 ;
     RECT  20.297 35.232 21.949 35.256 ;
     RECT  21.233 21.504 21.953 24.792 ;
     RECT  21.683 69.264 22.241 71.496 ;
     RECT  21.701 26.4 22.309 29.784 ;
     RECT  21.733 2.256 22.385 8.376 ;
     RECT  22.309 25.872 22.421 29.784 ;
     RECT  21.233 9.648 22.453 20.04 ;
     RECT  22.385 2.256 22.457 5.88 ;
     RECT  22.241 69.264 22.525 69.288 ;
     RECT  22.385 6.912 22.597 8.376 ;
     RECT  22.453 9.648 22.597 20.28 ;
     RECT  21.593 37.056 22.777 39.528 ;
     RECT  21.593 40.56 22.777 40.872 ;
     RECT  21.593 42.144 22.777 68.184 ;
     RECT  22.525 69.168 22.777 69.288 ;
     RECT  21.949 31.152 22.849 35.736 ;
     RECT  22.777 37.056 22.849 69.288 ;
     RECT  22.849 31.152 22.853 69.288 ;
     RECT  22.241 70.368 22.885 71.496 ;
     RECT  22.853 31.152 22.889 40.68 ;
     RECT  22.889 31.152 22.957 40.584 ;
     RECT  21.953 21.648 23.029 24.792 ;
     RECT  22.421 25.872 23.029 29.16 ;
     RECT  21.665 73.776 23.029 74.76 ;
     RECT  22.885 70.368 23.101 72.216 ;
     RECT  23.029 73.776 23.101 74.856 ;
     RECT  22.597 6.912 23.353 20.28 ;
     RECT  23.353 6.912 23.497 20.376 ;
     RECT  23.029 21.648 23.497 29.16 ;
     RECT  22.457 2.352 23.569 5.88 ;
     RECT  23.497 6.912 23.569 29.16 ;
     RECT  23.569 2.352 23.641 29.16 ;
     RECT  22.957 30.432 23.641 40.584 ;
     RECT  23.641 2.352 23.857 40.584 ;
     RECT  22.853 41.664 23.857 69.288 ;
     RECT  23.857 2.352 24.008 69.288 ;
     RECT  23.101 70.368 24.008 74.856 ;
     RECT  24.008 2.148 24.112 75.612 ;
     RECT  24.112 2.256 24.304 75.342 ;
     RECT  24.304 37.104 24.329 72.264 ;
     RECT  24.304 73.344 24.46 75.288 ;
     RECT  24.304 2.256 25.013 35.928 ;
     RECT  25.013 2.256 25.049 25.08 ;
     RECT  25.013 26.064 25.157 35.928 ;
     RECT  25.049 2.256 25.193 24.984 ;
     RECT  24.329 37.392 25.409 72.264 ;
     RECT  25.157 26.4 25.477 35.928 ;
     RECT  25.193 5.568 25.589 24.984 ;
     RECT  24.46 73.344 25.661 75.24 ;
     RECT  25.589 5.568 25.697 13.704 ;
     RECT  25.409 37.392 25.769 71.928 ;
     RECT  25.661 73.344 25.769 75.144 ;
     RECT  25.769 73.728 25.805 75.144 ;
     RECT  25.769 37.392 25.945 70.392 ;
     RECT  25.193 2.256 26.021 4.248 ;
     RECT  25.589 14.976 26.125 24.984 ;
     RECT  25.477 26.4 26.161 36.264 ;
     RECT  25.945 37.344 26.161 70.392 ;
     RECT  26.021 3.12 26.201 4.248 ;
     RECT  26.201 3.216 26.233 4.248 ;
     RECT  25.697 5.568 26.233 5.784 ;
     RECT  26.161 26.4 26.309 70.392 ;
     RECT  26.125 14.976 26.737 25.08 ;
     RECT  26.309 26.4 26.737 65.016 ;
     RECT  26.737 14.976 26.777 65.016 ;
     RECT  26.233 3.216 26.885 5.784 ;
     RECT  26.777 37.104 26.993 65.016 ;
     RECT  25.769 71.472 27.013 71.928 ;
     RECT  26.993 37.104 27.1 53.4 ;
     RECT  25.697 6.816 27.205 13.704 ;
     RECT  27.205 6.816 27.313 13.944 ;
     RECT  26.309 66.096 27.313 70.392 ;
     RECT  27.013 71.472 27.313 72.456 ;
     RECT  27.313 66.096 27.349 72.456 ;
     RECT  26.885 4.608 27.353 5.16 ;
     RECT  26.777 14.976 27.497 36.072 ;
     RECT  26.885 3.216 27.565 3.48 ;
     RECT  27.565 3.024 27.853 3.48 ;
     RECT  27.353 4.608 27.853 4.968 ;
     RECT  27.349 66.096 27.853 72.552 ;
     RECT  27.781 75.792 27.865 75.816 ;
     RECT  27.853 3.024 27.961 4.968 ;
     RECT  27.1 37.344 27.965 53.4 ;
     RECT  27.497 35.184 28.213 36.072 ;
     RECT  26.993 54.432 28.213 65.016 ;
     RECT  27.853 66 28.213 72.552 ;
     RECT  27.313 6.384 28.393 13.944 ;
     RECT  27.497 14.976 28.393 34.152 ;
     RECT  28.213 35.184 28.393 36.36 ;
     RECT  27.965 37.344 28.393 49.512 ;
     RECT  27.961 2.832 28.429 4.968 ;
     RECT  28.393 6.384 28.433 34.152 ;
     RECT  28.429 2.496 28.681 4.968 ;
     RECT  27.965 50.88 28.681 53.4 ;
     RECT  28.213 54.432 28.681 72.552 ;
     RECT  28.681 50.88 28.885 72.552 ;
     RECT  25.805 73.728 28.885 74.712 ;
     RECT  28.433 6.816 29.257 34.152 ;
     RECT  28.393 35.184 29.257 49.512 ;
     RECT  28.681 2.496 29.408 5.4 ;
     RECT  29.257 6.816 29.408 49.848 ;
     RECT  28.885 50.88 29.408 74.712 ;
     RECT  29.408 2.148 29.512 75.612 ;
     RECT  29.512 2.418 29.704 75.342 ;
     RECT  29.704 3.312 29.987 4.008 ;
     RECT  29.704 5.04 30.233 49.848 ;
     RECT  29.704 50.832 30.269 67.896 ;
     RECT  30.233 41.184 30.377 49.848 ;
     RECT  29.704 68.928 30.521 72.552 ;
     RECT  30.377 41.376 30.949 49.848 ;
     RECT  30.269 50.832 30.949 67.848 ;
     RECT  29.987 3.408 30.953 4.008 ;
     RECT  30.953 3.984 31.021 4.008 ;
     RECT  30.233 5.04 31.021 6.312 ;
     RECT  30.521 70.368 31.129 72.552 ;
     RECT  29.704 73.776 31.129 74.712 ;
     RECT  31.129 70.368 31.385 74.712 ;
     RECT  30.233 7.344 31.417 40.104 ;
     RECT  30.949 41.376 31.417 67.848 ;
     RECT  31.417 7.344 31.457 67.848 ;
     RECT  31.385 70.368 31.601 71.112 ;
     RECT  30.521 68.928 31.669 69.048 ;
     RECT  31.385 72.384 31.709 74.712 ;
     RECT  31.601 70.368 31.781 70.92 ;
     RECT  31.669 68.928 31.813 69.096 ;
     RECT  31.781 70.368 31.813 70.392 ;
     RECT  31.813 68.928 31.909 70.392 ;
     RECT  31.021 3.984 31.925 6.312 ;
     RECT  31.709 72.432 31.961 74.712 ;
     RECT  31.909 68.88 32.147 70.392 ;
     RECT  31.925 4.272 32.173 6.312 ;
     RECT  31.457 7.344 32.173 21.48 ;
     RECT  31.457 22.56 32.213 67.848 ;
     RECT  32.213 39.504 32.285 67.848 ;
     RECT  32.173 4.272 32.321 21.48 ;
     RECT  32.285 39.504 32.501 66.84 ;
     RECT  31.561 2.832 32.609 2.856 ;
     RECT  32.321 6.864 32.677 21.48 ;
     RECT  32.213 22.56 32.677 38.52 ;
     RECT  32.147 69.696 32.749 70.392 ;
     RECT  32.501 41.376 32.897 66.84 ;
     RECT  32.285 67.824 32.965 67.848 ;
     RECT  31.961 72.432 33.001 73.368 ;
     RECT  31.961 74.592 33.001 74.712 ;
     RECT  33.001 72.432 33.073 74.712 ;
     RECT  33.073 72.432 33.109 74.904 ;
     RECT  32.321 4.272 33.361 5.64 ;
     RECT  32.897 43.248 33.397 66.84 ;
     RECT  32.965 67.824 33.397 68.376 ;
     RECT  33.361 4.272 33.469 5.736 ;
     RECT  32.749 69.696 33.545 71.304 ;
     RECT  32.897 41.376 33.581 42.024 ;
     RECT  33.545 70.656 33.587 71.304 ;
     RECT  33.587 70.8 33.613 71.304 ;
     RECT  33.109 72.432 33.613 75.384 ;
     RECT  33.505 2.256 33.757 2.28 ;
     RECT  33.469 4.032 33.793 5.736 ;
     RECT  32.677 6.864 33.793 38.52 ;
     RECT  33.397 43.248 34.405 68.376 ;
     RECT  34.405 43.248 34.549 69.288 ;
     RECT  33.613 70.8 34.549 75.384 ;
     RECT  32.501 39.504 34.604 40.104 ;
     RECT  33.581 41.376 34.604 41.688 ;
     RECT  33.757 2.256 34.652 2.52 ;
     RECT  34.652 2.256 34.765 2.856 ;
     RECT  33.793 4.032 34.765 38.52 ;
     RECT  34.765 2.256 34.808 38.52 ;
     RECT  34.604 39.504 34.808 41.688 ;
     RECT  34.549 43.248 34.808 75.384 ;
     RECT  34.808 2.148 34.912 75.612 ;
     RECT  34.912 2.418 35.104 75.342 ;
     RECT  35.104 42.672 35.453 69.288 ;
     RECT  35.104 72.24 35.777 75.144 ;
     RECT  35.777 72.24 35.813 75 ;
     RECT  35.104 2.418 35.893 41.688 ;
     RECT  35.893 2.256 35.921 41.688 ;
     RECT  35.921 2.256 35.98 5.256 ;
     RECT  35.104 70.8 36.205 71.208 ;
     RECT  35.813 72.24 36.205 74.904 ;
     RECT  35.921 6.288 36.821 41.688 ;
     RECT  36.205 70.32 36.853 74.904 ;
     RECT  36.821 6.912 36.889 41.688 ;
     RECT  35.453 42.672 36.889 69.24 ;
     RECT  36.853 70.272 36.929 74.904 ;
     RECT  35.98 2.352 36.965 5.256 ;
     RECT  36.889 6.912 37.001 69.24 ;
     RECT  36.929 70.272 37.109 74.712 ;
     RECT  36.965 2.496 37.289 5.256 ;
     RECT  37.289 3.744 37.357 5.256 ;
     RECT  37.001 9.072 37.573 69.24 ;
     RECT  37.001 6.912 38.101 7.752 ;
     RECT  37.357 3.744 38.197 5.688 ;
     RECT  38.101 6.864 38.197 7.752 ;
     RECT  38.197 3.744 38.257 7.752 ;
     RECT  37.573 9.072 38.257 69.768 ;
     RECT  38.257 3.744 38.365 69.768 ;
     RECT  37.109 70.752 38.365 74.712 ;
     RECT  37.289 2.496 38.401 2.568 ;
     RECT  38.365 3.744 38.401 74.712 ;
     RECT  38.401 2.496 38.473 74.76 ;
     RECT  38.473 2.256 38.725 74.76 ;
     RECT  38.725 2.256 38.945 75.144 ;
     RECT  38.945 2.256 39.913 69.336 ;
     RECT  38.945 70.608 39.913 75.144 ;
     RECT  39.913 2.256 40.208 75.144 ;
     RECT  40.208 2.148 40.312 75.612 ;
     RECT  40.312 2.256 40.504 75.342 ;
     RECT  40.504 2.256 40.997 75.144 ;
     RECT  40.997 6.816 41.105 75.144 ;
     RECT  40.997 2.256 41.573 5.784 ;
     RECT  41.573 2.784 41.645 5.784 ;
     RECT  41.105 6.864 41.825 75.144 ;
     RECT  41.645 2.784 41.969 5.208 ;
     RECT  41.969 3.696 42.005 5.208 ;
     RECT  41.825 6.864 42.041 74.904 ;
     RECT  42.005 5.184 42.077 5.208 ;
     RECT  42.005 3.696 42.221 3.96 ;
     RECT  42.041 7.2 42.221 74.904 ;
     RECT  42.221 3.696 42.329 3.768 ;
     RECT  42.221 7.2 42.329 72.792 ;
     RECT  42.329 3.744 42.725 3.768 ;
     RECT  42.329 7.2 42.797 7.944 ;
     RECT  42.797 7.2 43.085 7.512 ;
     RECT  42.329 9.072 43.621 72.792 ;
     RECT  42.221 73.776 43.621 74.904 ;
     RECT  43.729 3.936 44.197 3.96 ;
     RECT  44.197 3.312 44.237 3.96 ;
     RECT  44.269 5.616 44.305 5.64 ;
     RECT  44.237 3.312 44.339 3.336 ;
     RECT  44.305 5.616 44.665 6.024 ;
     RECT  43.085 7.2 44.665 7.416 ;
     RECT  43.621 9.072 45.025 74.904 ;
     RECT  44.665 5.616 45.061 7.416 ;
     RECT  43.837 2.256 45.608 2.28 ;
     RECT  45.061 5.28 45.608 7.416 ;
     RECT  45.025 8.976 45.608 74.904 ;
     RECT  45.608 2.148 45.712 75.612 ;
     RECT  45.712 2.418 45.904 75.342 ;
     RECT  45.904 5.472 46.403 75.24 ;
     RECT  46.403 8.544 46.865 75.24 ;
     RECT  46.865 8.592 46.901 75.24 ;
     RECT  45.904 3.312 47.797 4.44 ;
     RECT  46.403 5.472 47.797 7.416 ;
     RECT  47.797 3.312 48.697 7.416 ;
     RECT  46.901 8.592 48.697 74.904 ;
     RECT  48.697 3.312 48.737 74.904 ;
     RECT  48.841 2.544 49.277 2.568 ;
     RECT  48.737 3.888 49.349 74.904 ;
     RECT  49.349 3.888 49.813 4.776 ;
     RECT  49.813 3.312 50.245 4.776 ;
     RECT  50.245 2.784 50.353 4.776 ;
     RECT  49.349 5.952 50.353 74.904 ;
     RECT  50.353 2.784 50.569 74.904 ;
     RECT  50.569 2.544 51.008 74.904 ;
     RECT  51.008 2.148 51.112 75.612 ;
     RECT  51.112 2.418 51.304 75.342 ;
     RECT  51.304 2.544 52.405 7.992 ;
     RECT  51.304 8.976 52.405 74.328 ;
     RECT  52.405 2.544 52.481 75 ;
     RECT  52.481 2.88 53.411 75 ;
     RECT  53.411 74.256 53.489 75 ;
     RECT  53.411 2.88 53.603 72.936 ;
     RECT  53.603 2.88 53.633 72.888 ;
     RECT  53.633 2.88 53.705 68.136 ;
     RECT  53.705 2.88 54.373 67.992 ;
     RECT  54.373 2.256 54.713 67.992 ;
     RECT  54.713 2.88 54.745 67.992 ;
     RECT  53.633 69.216 54.745 72.888 ;
     RECT  54.745 2.88 54.817 72.888 ;
     RECT  53.489 74.304 54.817 75 ;
     RECT  54.817 2.88 55.001 75.24 ;
     RECT  55.001 3.408 55.037 75.24 ;
     RECT  55.037 3.408 55.325 4.008 ;
     RECT  55.037 5.088 56.041 75.24 ;
     RECT  55.325 3.408 56.408 3.432 ;
     RECT  56.041 4.416 56.408 75.24 ;
     RECT  56.408 2.148 56.512 75.612 ;
     RECT  56.512 2.418 56.704 75.342 ;
     RECT  56.704 3.312 57.089 75.288 ;
     RECT  57.089 9.072 57.521 75.288 ;
     RECT  57.521 9.072 57.665 73.752 ;
     RECT  57.089 3.312 57.949 7.752 ;
     RECT  57.949 3.168 58.021 7.752 ;
     RECT  57.521 75.072 58.169 75.288 ;
     RECT  58.021 2.544 58.381 7.752 ;
     RECT  57.665 9.072 58.381 72.936 ;
     RECT  58.381 2.544 58.849 72.936 ;
     RECT  58.849 2.544 58.993 72.984 ;
     RECT  58.993 2.544 59.221 74.088 ;
     RECT  59.221 2.304 59.257 74.088 ;
     RECT  59.257 2.304 59.321 4.296 ;
     RECT  59.257 5.28 59.465 74.088 ;
     RECT  58.169 75.072 59.537 75.192 ;
     RECT  59.537 75.072 59.645 75.096 ;
     RECT  59.321 2.304 60.325 4.008 ;
     RECT  59.465 5.28 60.325 7.752 ;
     RECT  60.325 2.304 60.365 7.752 ;
     RECT  59.465 8.736 60.509 74.088 ;
     RECT  60.365 2.544 60.997 7.752 ;
     RECT  60.509 8.736 60.997 29.352 ;
     RECT  60.505 75.312 61.153 75.336 ;
     RECT  60.509 30.336 61.189 74.088 ;
     RECT  60.997 2.544 61.513 29.352 ;
     RECT  61.189 30.336 61.513 74.136 ;
     RECT  61.513 2.544 61.808 74.136 ;
     RECT  61.153 75.216 61.808 75.336 ;
     RECT  61.808 2.148 61.912 75.612 ;
     RECT  61.912 2.418 62.104 75.342 ;
     RECT  62.104 2.544 62.165 3.864 ;
     RECT  62.104 5.472 62.597 74.136 ;
     RECT  62.597 58.416 62.741 74.136 ;
     RECT  62.741 72.528 62.885 74.136 ;
     RECT  62.165 3.072 63.169 3.864 ;
     RECT  63.169 2.448 63.241 3.864 ;
     RECT  62.741 58.416 63.453 71.496 ;
     RECT  62.597 5.472 63.497 57.144 ;
     RECT  63.241 2.448 63.857 4.44 ;
     RECT  62.885 72.528 63.893 73.272 ;
     RECT  63.893 72.528 64.001 73.128 ;
     RECT  63.857 2.448 64.037 3.864 ;
     RECT  63.313 74.736 64.141 74.76 ;
     RECT  64.141 74.4 64.177 74.76 ;
     RECT  63.453 58.944 64.541 71.496 ;
     RECT  64.541 58.992 64.825 71.496 ;
     RECT  64.037 2.64 64.844 3.864 ;
     RECT  64.001 72.624 64.861 73.128 ;
     RECT  64.177 74.304 64.861 75.144 ;
     RECT  64.844 2.64 64.931 4.728 ;
     RECT  63.497 5.76 65.149 57.144 ;
     RECT  65.149 5.76 65.413 57.864 ;
     RECT  64.825 58.992 65.437 71.64 ;
     RECT  64.861 72.624 65.437 75.144 ;
     RECT  65.437 58.992 65.585 75.144 ;
     RECT  65.413 5.616 65.729 57.864 ;
     RECT  64.931 2.64 65.905 4.488 ;
     RECT  65.729 5.712 65.905 57.864 ;
     RECT  65.585 58.992 65.905 71.64 ;
     RECT  65.905 5.712 65.909 71.64 ;
     RECT  65.909 22.8 66.661 71.64 ;
     RECT  65.585 72.624 66.661 75.144 ;
     RECT  65.909 5.712 67.093 21.816 ;
     RECT  66.661 22.8 67.093 75.144 ;
     RECT  65.905 2.256 67.201 4.488 ;
     RECT  67.093 5.712 67.201 75.144 ;
     RECT  67.201 2.256 67.208 75.144 ;
     RECT  67.208 2.148 67.312 75.612 ;
     RECT  67.312 2.256 67.385 75.342 ;
     RECT  67.385 2.418 67.504 75.342 ;
     RECT  67.504 4.416 67.529 29.352 ;
     RECT  67.529 8.208 67.565 29.352 ;
     RECT  67.504 30.384 67.66 72.984 ;
     RECT  67.504 2.88 67.709 3.048 ;
     RECT  67.66 30.384 67.709 69.336 ;
     RECT  67.66 70.368 67.811 72.984 ;
     RECT  67.811 70.56 67.853 72.984 ;
     RECT  67.529 4.416 67.925 7.224 ;
     RECT  67.565 8.784 67.925 29.352 ;
     RECT  67.709 30.384 67.997 69.096 ;
     RECT  67.504 74.832 68.285 75.24 ;
     RECT  67.925 6.336 68.321 7.224 ;
     RECT  67.925 8.784 68.321 14.52 ;
     RECT  68.321 11.52 68.501 14.52 ;
     RECT  67.997 30.48 68.501 69.096 ;
     RECT  67.853 70.752 68.573 72.984 ;
     RECT  67.709 3.024 68.605 3.048 ;
     RECT  67.925 4.416 68.605 5.16 ;
     RECT  68.501 48.864 68.684 69.096 ;
     RECT  68.573 70.848 68.725 72.984 ;
     RECT  67.925 15.504 68.821 29.352 ;
     RECT  68.285 74.832 68.857 75.192 ;
     RECT  68.321 8.784 68.929 10.344 ;
     RECT  68.605 3.024 68.965 5.16 ;
     RECT  68.321 7.104 68.965 7.224 ;
     RECT  68.857 74.688 69.005 75.192 ;
     RECT  69.005 74.688 69.073 74.856 ;
     RECT  68.929 8.448 69.077 10.344 ;
     RECT  68.821 15.504 69.145 29.4 ;
     RECT  68.501 30.48 69.145 47.784 ;
     RECT  69.145 15.504 69.185 47.784 ;
     RECT  68.684 48.864 69.217 69.192 ;
     RECT  69.185 15.504 69.365 18.936 ;
     RECT  69.185 20.112 69.401 47.784 ;
     RECT  69.073 74.544 69.401 74.856 ;
     RECT  68.501 11.568 69.613 14.52 ;
     RECT  69.365 15.504 69.613 16.92 ;
     RECT  69.401 27.456 69.757 47.784 ;
     RECT  69.217 48.864 69.757 69.528 ;
     RECT  68.725 70.848 69.757 73.272 ;
     RECT  69.401 74.544 69.757 74.568 ;
     RECT  68.965 7.104 69.829 7.416 ;
     RECT  69.077 9.84 69.901 10.344 ;
     RECT  69.613 11.568 69.901 16.92 ;
     RECT  69.829 6.24 69.973 7.416 ;
     RECT  69.077 8.448 69.973 8.856 ;
     RECT  69.973 6.24 70.076 8.856 ;
     RECT  69.901 9.84 70.076 16.92 ;
     RECT  70.076 6.24 70.157 16.92 ;
     RECT  68.965 2.256 70.261 5.16 ;
     RECT  70.261 2.256 70.265 5.544 ;
     RECT  69.757 27.456 70.301 69.528 ;
     RECT  70.157 6.624 70.333 16.92 ;
     RECT  69.365 18 70.333 18.936 ;
     RECT  70.301 27.456 70.337 29.256 ;
     RECT  69.757 70.848 70.369 74.568 ;
     RECT  70.301 30.288 70.441 69.528 ;
     RECT  70.369 70.848 70.441 74.712 ;
     RECT  69.401 20.112 70.549 26.136 ;
     RECT  70.265 3.024 70.553 5.544 ;
     RECT  70.337 27.456 70.553 29.16 ;
     RECT  70.553 3.024 70.589 3.384 ;
     RECT  70.333 6.624 70.739 18.936 ;
     RECT  70.589 3.312 70.805 3.384 ;
     RECT  70.549 20.112 70.805 26.232 ;
     RECT  70.739 6.624 70.841 7.896 ;
     RECT  70.441 30.288 70.913 74.712 ;
     RECT  70.553 27.456 70.949 29.112 ;
     RECT  70.805 3.312 71.057 3.336 ;
     RECT  70.841 6.624 71.093 7.8 ;
     RECT  70.553 4.368 71.125 5.544 ;
     RECT  71.093 6.624 71.125 7.56 ;
     RECT  70.805 23.328 71.161 26.232 ;
     RECT  70.805 20.112 71.237 22.248 ;
     RECT  70.949 27.456 71.273 28.728 ;
     RECT  71.273 27.456 71.345 28.536 ;
     RECT  70.739 9.072 71.377 18.936 ;
     RECT  71.237 20.112 71.377 20.136 ;
     RECT  70.913 30.48 71.453 74.712 ;
     RECT  71.125 4.368 71.561 7.56 ;
     RECT  71.161 23.328 71.593 26.376 ;
     RECT  71.345 27.456 71.593 28.488 ;
     RECT  71.561 4.368 71.633 7.464 ;
     RECT  71.633 4.368 71.773 4.392 ;
     RECT  71.773 2.88 71.809 2.904 ;
     RECT  71.809 2.208 72.037 2.904 ;
     RECT  71.773 4.32 72.037 4.392 ;
     RECT  71.453 30.48 72.061 53.64 ;
     RECT  72.061 30.384 72.133 53.64 ;
     RECT  71.237 21.12 72.169 22.248 ;
     RECT  71.593 23.328 72.169 28.488 ;
     RECT  71.377 9.072 72.493 20.136 ;
     RECT  72.169 21.12 72.493 28.488 ;
     RECT  72.037 2.208 72.608 4.392 ;
     RECT  71.633 5.472 72.608 7.464 ;
     RECT  72.493 8.448 72.608 28.488 ;
     RECT  72.133 30.144 72.608 53.64 ;
     RECT  71.453 55.536 72.608 74.712 ;
     RECT  72.608 2.148 72.712 75.612 ;
     RECT  72.712 2.418 72.904 75.342 ;
     RECT  72.904 69.984 73.187 73.368 ;
     RECT  72.904 39.264 73.433 54.168 ;
     RECT  72.904 57.888 73.475 69 ;
     RECT  72.904 8.016 73.541 10.44 ;
     RECT  72.904 23.568 73.613 31.176 ;
     RECT  73.541 8.016 73.685 9.912 ;
     RECT  73.685 8.016 73.757 8.712 ;
     RECT  73.433 39.264 73.757 48.408 ;
     RECT  73.613 23.568 73.901 26.664 ;
     RECT  72.904 3.936 73.937 3.96 ;
     RECT  72.904 74.688 73.969 74.712 ;
     RECT  73.757 39.264 73.973 47.208 ;
     RECT  72.904 18 74.005 22.584 ;
     RECT  73.901 23.568 74.005 26.376 ;
     RECT  73.475 57.888 74.009 67.176 ;
     RECT  73.433 49.536 74.041 54.168 ;
     RECT  72.904 55.392 74.041 56.328 ;
     RECT  73.613 28.128 74.077 31.176 ;
     RECT  72.904 32.208 74.077 33.144 ;
     RECT  74.041 49.536 74.081 56.328 ;
     RECT  72.904 5.472 74.101 6.888 ;
     RECT  73.187 70.272 74.117 73.368 ;
     RECT  74.077 28.128 74.157 33.144 ;
     RECT  72.904 34.176 74.157 38.28 ;
     RECT  74.101 4.416 74.185 6.888 ;
     RECT  72.904 12 74.329 16.968 ;
     RECT  74.157 28.128 74.329 38.28 ;
     RECT  73.973 39.264 74.329 44.472 ;
     RECT  74.005 18 74.369 26.376 ;
     RECT  74.081 49.536 74.405 53.832 ;
     RECT  73.757 48.384 74.473 48.408 ;
     RECT  74.009 63.888 74.473 67.176 ;
     RECT  73.475 68.448 74.473 69 ;
     RECT  73.685 9.696 74.509 9.912 ;
     RECT  73.757 8.448 74.585 8.712 ;
     RECT  74.509 9.696 74.657 10.056 ;
     RECT  74.329 28.128 74.693 44.472 ;
     RECT  74.009 57.888 74.725 62.712 ;
     RECT  74.473 48.384 74.729 49.464 ;
     RECT  74.693 28.176 74.765 44.472 ;
     RECT  74.081 54.864 74.801 56.328 ;
     RECT  74.473 63.888 74.833 69 ;
     RECT  74.117 70.272 74.833 71.352 ;
     RECT  74.657 9.744 74.873 10.056 ;
     RECT  73.969 74.688 74.873 75.24 ;
     RECT  73.973 45.552 74.945 47.208 ;
     RECT  74.117 72.432 74.945 73.368 ;
     RECT  74.329 11.424 74.977 16.968 ;
     RECT  74.369 18 74.977 18.024 ;
     RECT  74.833 63.888 75.011 71.352 ;
     RECT  74.945 45.744 75.013 47.208 ;
     RECT  74.185 4.416 75.049 7.272 ;
     RECT  74.977 11.424 75.049 18.024 ;
     RECT  74.945 73.248 75.049 73.368 ;
     RECT  74.873 75.216 75.053 75.24 ;
     RECT  75.049 4.416 75.121 7.512 ;
     RECT  74.873 9.84 75.121 10.056 ;
     RECT  75.049 11.28 75.121 18.024 ;
     RECT  75.011 70.272 75.157 71.352 ;
     RECT  74.369 19.344 75.205 26.376 ;
     RECT  75.121 9.84 75.305 18.024 ;
     RECT  74.405 50.592 75.337 53.832 ;
     RECT  75.049 73.248 75.341 73.512 ;
     RECT  72.904 2.832 75.349 2.856 ;
     RECT  75.121 4.368 75.349 7.512 ;
     RECT  74.725 57.552 75.397 62.712 ;
     RECT  75.011 63.888 75.397 68.664 ;
     RECT  75.349 2.832 75.436 7.512 ;
     RECT  75.397 57.552 75.443 68.664 ;
     RECT  74.729 48.432 75.491 49.464 ;
     RECT  75.436 4.368 75.553 7.512 ;
     RECT  74.585 8.544 75.553 8.712 ;
     RECT  75.305 10.032 75.553 18.024 ;
     RECT  75.205 19.344 75.553 26.664 ;
     RECT  75.443 63.504 75.629 68.664 ;
     RECT  75.491 48.96 75.661 49.464 ;
     RECT  75.337 50.592 75.661 53.928 ;
     RECT  75.553 4.368 75.737 8.712 ;
     RECT  74.765 29.04 75.805 44.472 ;
     RECT  75.737 4.368 75.809 6.264 ;
     RECT  75.013 45.744 75.829 47.304 ;
     RECT  75.805 28.368 75.913 44.472 ;
     RECT  75.661 48.96 75.913 53.928 ;
     RECT  74.801 55.392 75.913 56.328 ;
     RECT  75.553 10.032 75.949 26.664 ;
     RECT  75.737 7.248 75.953 8.712 ;
     RECT  75.949 10.032 75.985 26.808 ;
     RECT  75.913 28.176 75.985 44.472 ;
     RECT  75.953 7.248 75.989 8.04 ;
     RECT  75.985 10.032 76.06 44.472 ;
     RECT  76.06 14.928 76.061 44.472 ;
     RECT  76.061 14.928 76.067 44.424 ;
     RECT  75.157 70.272 76.097 71.736 ;
     RECT  76.067 15.36 76.133 44.424 ;
     RECT  75.809 4.656 76.169 6.264 ;
     RECT  75.989 7.248 76.205 7.656 ;
     RECT  76.097 70.608 76.237 71.736 ;
     RECT  76.133 15.36 76.241 44.328 ;
     RECT  76.241 21.12 76.313 25.08 ;
     RECT  75.629 63.504 76.349 67.272 ;
     RECT  76.06 10.032 76.381 13.704 ;
     RECT  76.241 15.36 76.403 19.944 ;
     RECT  75.629 68.4 76.421 68.664 ;
     RECT  76.421 68.544 76.453 68.664 ;
     RECT  76.169 4.656 76.457 5.88 ;
     RECT  76.237 70.608 76.493 71.928 ;
     RECT  76.403 17.568 76.529 19.944 ;
     RECT  75.443 57.552 76.561 62.52 ;
     RECT  76.349 63.504 76.561 65.256 ;
     RECT  76.381 9.36 76.565 13.704 ;
     RECT  76.453 68.544 76.601 69.24 ;
     RECT  76.403 15.36 76.637 16.296 ;
     RECT  76.601 68.64 76.709 69.24 ;
     RECT  76.241 26.16 76.817 44.328 ;
     RECT  75.913 48.96 76.817 56.328 ;
     RECT  75.829 45.744 76.885 47.544 ;
     RECT  76.493 70.608 76.889 71.16 ;
     RECT  76.205 7.248 76.925 7.512 ;
     RECT  76.637 15.36 76.961 16.008 ;
     RECT  76.349 66.24 76.961 67.272 ;
     RECT  76.565 9.36 76.997 10.968 ;
     RECT  76.313 21.168 76.997 25.08 ;
     RECT  76.565 11.952 77.033 13.704 ;
     RECT  76.529 17.568 77.033 19.752 ;
     RECT  76.817 55.968 77.065 56.328 ;
     RECT  76.561 57.552 77.065 65.256 ;
     RECT  76.885 45.648 77.137 47.544 ;
     RECT  76.817 48.96 77.137 54.744 ;
     RECT  76.997 9.36 77.209 10.92 ;
     RECT  76.925 7.44 77.281 7.512 ;
     RECT  77.209 8.928 77.281 10.92 ;
     RECT  77.065 55.968 77.425 65.256 ;
     RECT  76.961 66.24 77.425 67.128 ;
     RECT  76.817 32.208 77.497 44.328 ;
     RECT  77.137 45.648 77.497 54.744 ;
     RECT  75.341 73.344 77.557 73.512 ;
     RECT  76.889 70.656 77.641 71.16 ;
     RECT  76.961 15.984 77.713 16.008 ;
     RECT  77.033 17.568 77.713 19.56 ;
     RECT  76.817 26.16 77.749 30.744 ;
     RECT  76.457 5.472 77.785 5.88 ;
     RECT  76.997 21.168 77.845 24.504 ;
     RECT  77.749 25.536 77.857 30.744 ;
     RECT  77.497 32.208 77.857 54.744 ;
     RECT  76.709 68.64 77.857 69 ;
     RECT  77.713 15.984 78.001 19.56 ;
     RECT  75.436 2.832 78.008 2.856 ;
     RECT  77.785 5.472 78.008 6.312 ;
     RECT  77.281 7.44 78.008 10.92 ;
     RECT  77.033 11.952 78.008 13.656 ;
     RECT  77.173 14.832 78.008 14.856 ;
     RECT  78.001 15.984 78.008 19.608 ;
     RECT  77.845 20.736 78.008 24.504 ;
     RECT  77.857 25.536 78.008 54.744 ;
     RECT  77.425 55.968 78.008 67.128 ;
     RECT  77.857 68.208 78.008 69 ;
     RECT  77.641 70.656 78.008 71.736 ;
     RECT  77.557 73.344 78.008 74.328 ;
     RECT  78.008 2.148 78.112 75.612 ;
     RECT  78.112 2.418 78.304 75.342 ;
     RECT  78.304 16.224 78.329 38.184 ;
     RECT  78.304 43.824 78.365 53.544 ;
     RECT  78.304 4.896 78.473 15.096 ;
     RECT  78.304 73.344 78.473 73.368 ;
     RECT  78.304 55.872 78.545 55.992 ;
     RECT  78.329 22.224 78.725 37.08 ;
     RECT  78.304 39.6 78.797 42.792 ;
     RECT  78.725 22.224 78.833 23.976 ;
     RECT  78.304 70.032 78.899 71.736 ;
     RECT  78.899 70.032 78.941 70.872 ;
     RECT  78.797 39.6 79.049 42.504 ;
     RECT  78.304 68.928 79.085 68.952 ;
     RECT  78.725 25.008 79.157 37.08 ;
     RECT  78.365 44.976 79.235 53.544 ;
     RECT  78.304 57.6 79.361 62.04 ;
     RECT  79.361 57.024 79.369 62.04 ;
     RECT  78.304 63.312 79.369 65.256 ;
     RECT  79.369 57.024 79.409 65.256 ;
     RECT  79.409 57.024 79.445 59.256 ;
     RECT  78.941 70.032 79.445 70.296 ;
     RECT  78.329 16.224 79.517 21.24 ;
     RECT  79.157 25.008 79.517 28.872 ;
     RECT  79.517 18.672 79.549 21.24 ;
     RECT  78.833 22.224 79.549 23.832 ;
     RECT  78.304 66.24 79.585 67.8 ;
     RECT  78.473 8.736 79.589 15.096 ;
     RECT  79.235 44.976 79.625 48.984 ;
     RECT  79.589 8.736 79.661 13.464 ;
     RECT  79.549 18.672 79.769 23.832 ;
     RECT  79.157 30.24 79.813 37.08 ;
     RECT  78.329 38.16 79.813 38.184 ;
     RECT  79.409 60.24 79.837 65.256 ;
     RECT  79.585 66.24 79.837 67.944 ;
     RECT  79.445 57.648 79.841 59.256 ;
     RECT  79.517 25.296 79.949 28.872 ;
     RECT  78.473 4.896 79.981 7.656 ;
     RECT  79.235 51.888 80.017 53.544 ;
     RECT  79.813 30.24 80.099 38.184 ;
     RECT  79.981 4.704 80.161 7.656 ;
     RECT  79.661 8.736 80.161 12.888 ;
     RECT  78.365 43.824 80.161 43.848 ;
     RECT  79.589 14.496 80.245 15.096 ;
     RECT  80.099 32.832 80.309 38.184 ;
     RECT  80.245 14.496 80.332 15.24 ;
     RECT  79.049 39.6 80.341 42.12 ;
     RECT  79.235 50.256 80.341 50.664 ;
     RECT  79.909 69.552 80.341 69.576 ;
     RECT  80.309 32.832 80.345 37.656 ;
     RECT  79.625 44.976 80.345 47.448 ;
     RECT  79.837 60.24 80.345 67.944 ;
     RECT  80.161 43.824 80.389 43.896 ;
     RECT  80.161 4.704 80.417 12.888 ;
     RECT  80.099 30.24 80.449 31.512 ;
     RECT  80.345 60.24 80.453 63.288 ;
     RECT  79.769 19.056 80.485 23.832 ;
     RECT  80.345 64.368 80.521 67.944 ;
     RECT  80.341 68.928 80.521 69.576 ;
     RECT  80.485 19.056 80.557 23.976 ;
     RECT  79.949 25.296 80.557 28.008 ;
     RECT  80.345 46.224 80.593 47.448 ;
     RECT  79.625 48.96 80.593 48.984 ;
     RECT  80.521 64.368 80.597 69.576 ;
     RECT  78.545 55.872 80.633 55.896 ;
     RECT  80.453 63.264 80.633 63.288 ;
     RECT  80.341 39.6 80.669 42.168 ;
     RECT  80.449 30.048 80.705 31.512 ;
     RECT  80.557 19.056 80.741 28.008 ;
     RECT  80.705 30.048 80.741 30.792 ;
     RECT  80.741 23.952 80.764 28.008 ;
     RECT  80.389 43.776 80.777 44.952 ;
     RECT  80.741 30.048 80.809 30.696 ;
     RECT  80.741 19.056 80.813 22.776 ;
     RECT  80.813 20.208 80.86 22.776 ;
     RECT  80.813 19.056 80.885 19.08 ;
     RECT  80.809 29.424 80.885 30.696 ;
     RECT  80.332 14.496 80.917 15.096 ;
     RECT  79.841 57.648 80.917 58.776 ;
     RECT  80.593 46.224 80.921 48.984 ;
     RECT  80.777 43.776 80.924 43.848 ;
     RECT  78.304 3.312 80.957 3.336 ;
     RECT  80.345 32.832 80.957 37.08 ;
     RECT  80.921 47.04 80.989 48.984 ;
     RECT  80.341 50.256 80.989 50.712 ;
     RECT  80.597 64.368 80.993 69.432 ;
     RECT  80.669 39.84 81.011 42.168 ;
     RECT  80.924 43.248 81.011 43.848 ;
     RECT  79.517 16.224 81.013 17.304 ;
     RECT  80.764 23.952 81.029 24.648 ;
     RECT  80.885 29.424 81.029 30.312 ;
     RECT  80.017 51.888 81.061 53.592 ;
     RECT  80.453 60.24 81.133 62.184 ;
     RECT  80.989 47.04 81.137 50.712 ;
     RECT  80.957 32.832 81.209 36.936 ;
     RECT  80.417 8.496 81.212 12.888 ;
     RECT  80.917 14.208 81.212 15.096 ;
     RECT  81.013 16.224 81.245 18.696 ;
     RECT  81.212 8.496 81.281 15.096 ;
     RECT  81.281 8.496 81.299 13.272 ;
     RECT  80.417 4.704 81.389 7.512 ;
     RECT  81.061 51.888 81.421 53.928 ;
     RECT  81.205 55.968 81.421 55.992 ;
     RECT  80.917 57.072 81.421 58.776 ;
     RECT  80.764 25.728 81.452 28.008 ;
     RECT  81.389 4.704 81.457 5.112 ;
     RECT  81.209 32.832 81.457 34.776 ;
     RECT  81.452 25.728 81.493 28.248 ;
     RECT  81.029 29.424 81.493 30.216 ;
     RECT  81.421 55.968 81.493 58.776 ;
     RECT  81.133 59.76 81.493 62.184 ;
     RECT  81.493 25.728 81.497 30.216 ;
     RECT  81.493 55.968 81.497 62.184 ;
     RECT  81.245 16.56 81.533 18.696 ;
     RECT  81.457 31.824 81.533 34.776 ;
     RECT  81.497 55.968 81.533 61.032 ;
     RECT  80.993 64.368 81.533 66.6 ;
     RECT  81.497 27.312 81.539 30.216 ;
     RECT  81.299 8.496 81.605 12.36 ;
     RECT  81.533 34.176 81.605 34.776 ;
     RECT  81.011 43.776 81.605 43.848 ;
     RECT  81.137 48.336 81.605 50.712 ;
     RECT  81.533 56.16 81.605 61.032 ;
     RECT  81.497 62.064 81.635 62.184 ;
     RECT  81.457 4.56 81.637 5.112 ;
     RECT  81.605 58.656 81.641 61.032 ;
     RECT  81.011 39.84 81.713 41.784 ;
     RECT  80.86 21.216 81.749 22.776 ;
     RECT  81.389 6.336 81.785 7.512 ;
     RECT  81.539 29.04 81.785 30.216 ;
     RECT  81.605 43.776 81.785 43.8 ;
     RECT  81.209 35.856 81.821 36.936 ;
     RECT  81.605 48.336 81.857 50.52 ;
     RECT  80.86 20.208 81.884 20.232 ;
     RECT  81.749 21.216 81.884 22.104 ;
     RECT  81.137 47.04 81.893 47.304 ;
     RECT  81.857 50.256 81.929 50.52 ;
     RECT  81.605 56.16 81.965 57.672 ;
     RECT  81.884 20.208 81.971 22.104 ;
     RECT  81.713 40.032 81.997 41.784 ;
     RECT  81.857 48.336 82.001 48.456 ;
     RECT  81.539 27.312 82.037 28.008 ;
     RECT  81.605 34.176 82.037 34.584 ;
     RECT  81.421 51.888 82.037 54.744 ;
     RECT  81.641 58.656 82.037 60.408 ;
     RECT  80.993 67.68 82.037 69.432 ;
     RECT  81.965 56.16 82.067 56.472 ;
     RECT  82.037 34.224 82.073 34.584 ;
     RECT  81.281 14.736 82.109 15.096 ;
     RECT  81.971 20.208 82.109 20.232 ;
     RECT  81.971 21.216 82.109 22.104 ;
     RECT  81.533 31.824 82.109 32.856 ;
     RECT  80.777 44.928 82.109 44.952 ;
     RECT  81.929 50.256 82.109 50.328 ;
     RECT  82.067 56.16 82.109 56.184 ;
     RECT  82.073 34.224 82.115 34.344 ;
     RECT  81.605 12.336 82.145 12.36 ;
     RECT  81.533 16.56 82.145 16.92 ;
     RECT  81.821 36.48 82.145 36.936 ;
     RECT  81.997 40.032 82.177 42.216 ;
     RECT  81.637 3.984 82.181 5.112 ;
     RECT  82.177 40.032 82.213 42.744 ;
     RECT  82.145 36.672 82.217 36.936 ;
     RECT  82.001 48.432 82.217 48.456 ;
     RECT  81.029 23.952 82.249 24.216 ;
     RECT  81.785 6.816 82.285 7.512 ;
     RECT  81.605 8.496 82.285 10.728 ;
     RECT  81.533 17.904 82.285 18.696 ;
     RECT  82.213 40.032 82.297 42.84 ;
     RECT  81.533 64.848 82.309 66.6 ;
     RECT  82.037 67.68 82.309 69 ;
     RECT  82.109 14.736 82.325 14.76 ;
     RECT  82.109 21.216 82.325 21.672 ;
     RECT  82.309 64.848 82.325 69 ;
     RECT  82.325 64.848 82.355 68.328 ;
     RECT  82.217 36.912 82.361 36.936 ;
     RECT  82.297 40.032 82.361 42.744 ;
     RECT  82.037 53.568 82.361 54.744 ;
     RECT  82.361 40.032 82.433 42.216 ;
     RECT  81.785 30.192 82.573 30.216 ;
     RECT  82.181 3.984 82.597 5.064 ;
     RECT  82.285 6.816 82.645 10.728 ;
     RECT  82.285 17.904 82.645 19.224 ;
     RECT  82.037 51.888 83.084 52.44 ;
     RECT  82.109 50.256 83.125 50.28 ;
     RECT  81.497 25.728 83.149 26.328 ;
     RECT  82.037 27.312 83.149 27.336 ;
     RECT  83.228 12.528 83.249 12.552 ;
     RECT  82.597 3.888 83.408 5.064 ;
     RECT  82.645 6.816 83.408 11.016 ;
     RECT  83.249 12.528 83.408 13.368 ;
     RECT  82.145 16.656 83.408 16.92 ;
     RECT  82.645 17.904 83.408 19.992 ;
     RECT  82.325 21.648 83.408 21.672 ;
     RECT  82.249 23.712 83.408 24.216 ;
     RECT  83.149 25.728 83.408 27.336 ;
     RECT  81.785 29.04 83.408 29.064 ;
     RECT  82.573 30.192 83.408 30.792 ;
     RECT  82.109 31.824 83.408 31.848 ;
     RECT  82.109 32.832 83.408 32.856 ;
     RECT  82.115 34.224 83.408 34.248 ;
     RECT  82.433 40.032 83.408 40.056 ;
     RECT  82.433 41.616 83.408 42.216 ;
     RECT  81.893 47.28 83.408 47.304 ;
     RECT  83.041 48.816 83.408 48.84 ;
     RECT  83.125 49.92 83.408 50.28 ;
     RECT  83.084 51.6 83.408 52.44 ;
     RECT  82.361 53.808 83.408 54.744 ;
     RECT  81.965 57.648 83.408 57.672 ;
     RECT  82.037 58.896 83.408 60.408 ;
     RECT  81.635 62.064 83.408 62.088 ;
     RECT  81.853 63.216 83.408 63.24 ;
     RECT  82.355 64.848 83.408 67.896 ;
     RECT  83.408 2.148 83.512 75.612 ;
     RECT  83.512 2.418 83.704 75.342 ;
     RECT  83.704 37.68 84.841 37.704 ;
     RECT  84.841 37.392 84.877 37.704 ;
     RECT  84.877 36.432 85.453 37.704 ;
     RECT  85.453 36.24 86.316 36.264 ;
     RECT  85.453 36.264 86.364 36.336 ;
     RECT  85.453 36.336 86.316 36.36 ;
     RECT  85.453 36.36 86.364 36.432 ;
     RECT  85.453 36.432 86.316 36.456 ;
     RECT  85.453 36.456 86.364 36.528 ;
     RECT  85.453 36.528 86.316 36.552 ;
     RECT  85.453 36.552 86.364 36.624 ;
     RECT  85.453 36.624 86.316 36.648 ;
     RECT  85.453 36.648 86.364 36.72 ;
     RECT  85.453 36.72 86.316 36.744 ;
     RECT  85.453 36.744 86.364 36.816 ;
     RECT  85.453 36.816 86.316 36.84 ;
     RECT  85.453 36.84 86.364 36.912 ;
     RECT  85.453 36.912 86.316 36.936 ;
     RECT  85.453 36.936 86.364 37.008 ;
     RECT  85.453 37.008 86.316 37.032 ;
     RECT  85.453 37.032 86.364 37.104 ;
     RECT  85.453 37.104 86.316 37.128 ;
     RECT  85.453 37.128 86.364 37.2 ;
     RECT  85.453 37.2 86.316 37.224 ;
     RECT  85.453 37.224 86.364 37.296 ;
     RECT  85.453 37.296 86.316 37.32 ;
     RECT  85.453 37.32 86.364 37.392 ;
     RECT  85.453 37.392 86.316 37.416 ;
     RECT  85.453 37.416 86.364 37.488 ;
     RECT  85.453 37.488 86.316 37.512 ;
     RECT  85.453 37.512 86.364 37.584 ;
     RECT  85.453 37.584 86.316 37.608 ;
     RECT  85.453 37.608 86.364 37.68 ;
     RECT  85.453 37.68 86.316 37.704 ;
     RECT  85.453 37.704 86.364 37.776 ;
     RECT  85.453 37.776 86.316 37.8 ;
    LAYER M5 ;
     RECT  2.4 2.137 2.52 2.151 ;
     RECT  7.8 2.137 7.92 2.151 ;
     RECT  13.2 2.137 13.32 2.151 ;
     RECT  18.6 2.137 18.72 2.151 ;
     RECT  24 2.137 24.12 2.151 ;
     RECT  29.4 2.137 29.52 2.151 ;
     RECT  34.8 2.137 34.92 2.151 ;
     RECT  40.2 2.137 40.32 2.151 ;
     RECT  45.6 2.137 45.72 2.151 ;
     RECT  51 2.137 51.12 2.151 ;
     RECT  56.4 2.137 56.52 2.151 ;
     RECT  61.8 2.137 61.92 2.151 ;
     RECT  67.2 2.137 67.32 2.151 ;
     RECT  72.6 2.137 72.72 2.151 ;
     RECT  78 2.137 78.12 2.151 ;
     RECT  83.4 2.137 83.52 2.151 ;
     RECT  72.6 2.151 72.912 2.197 ;
     RECT  13.2 2.151 13.512 2.245 ;
     RECT  34.8 2.151 35.112 2.245 ;
     RECT  7.8 2.151 8.112 2.581 ;
     RECT  61.8 2.151 62.112 2.629 ;
     RECT  29.4 2.151 29.712 2.821 ;
     RECT  34.8 2.245 35.928 2.821 ;
     RECT  59.232 2.293 59.256 3.203 ;
     RECT  34.704 2.821 35.928 3.299 ;
     RECT  13.2 2.245 13.608 3.301 ;
     RECT  28.464 2.821 29.712 3.301 ;
     RECT  44.304 2.245 44.328 3.347 ;
     RECT  38.496 2.485 38.52 3.397 ;
     RECT  51 2.151 51.312 3.397 ;
     RECT  28.464 3.301 29.976 3.539 ;
     RECT  34.704 3.299 35.208 3.875 ;
     RECT  83.4 2.151 83.712 3.877 ;
     RECT  45.6 2.151 45.912 3.973 ;
     RECT  14.832 3.397 14.856 4.019 ;
     RECT  82.608 3.877 83.712 4.019 ;
     RECT  34.704 3.875 35.112 4.067 ;
     RECT  7.632 2.581 8.112 4.115 ;
     RECT  58.128 3.301 58.152 4.355 ;
     RECT  72.048 2.197 72.912 4.357 ;
     RECT  54.384 2.245 54.408 4.403 ;
     RECT  45.6 3.973 46.056 4.405 ;
     RECT  49.68 3.877 49.704 4.453 ;
     RECT  18.6 2.151 18.912 4.501 ;
     RECT  13.2 3.301 13.656 4.547 ;
     RECT  38.448 3.397 38.52 4.547 ;
     RECT  51 3.397 51.912 4.547 ;
     RECT  17.136 3.925 17.16 4.597 ;
     RECT  17.136 4.597 17.256 4.643 ;
     RECT  75.36 2.821 75.384 4.691 ;
     RECT  48.72 4.453 49.704 4.693 ;
     RECT  51 4.547 51.72 4.693 ;
     RECT  48.72 4.693 51.72 4.787 ;
     RECT  61.056 2.629 62.112 4.931 ;
     RECT  26.736 3.205 26.76 4.933 ;
     RECT  26.736 4.933 27.336 4.979 ;
     RECT  24 2.151 24.312 5.029 ;
     RECT  71.856 4.357 72.912 5.029 ;
     RECT  30.96 5.029 30.984 5.077 ;
     RECT  34.8 4.067 35.112 5.077 ;
     RECT  27.312 4.979 27.336 5.171 ;
     RECT  59.184 3.925 59.208 5.171 ;
     RECT  24 5.029 24.408 5.219 ;
     RECT  34.224 5.077 35.112 5.365 ;
     RECT  4.08 4.117 4.104 5.413 ;
     RECT  17.232 4.643 17.256 5.413 ;
     RECT  4.08 5.413 4.536 5.459 ;
     RECT  17.232 5.413 17.544 5.459 ;
     RECT  64.896 4.693 64.92 5.605 ;
     RECT  56.4 2.151 56.712 5.653 ;
     RECT  67.2 2.151 67.512 5.701 ;
     RECT  21.744 2.245 21.768 5.747 ;
     RECT  30.96 5.077 31.08 5.747 ;
     RECT  34.224 5.365 35.64 5.747 ;
     RECT  40.2 2.151 40.512 5.749 ;
     RECT  45.6 4.405 46.152 5.845 ;
     RECT  38.448 4.547 38.472 5.989 ;
     RECT  17.52 5.459 17.544 6.035 ;
     RECT  38.208 5.989 38.472 6.035 ;
     RECT  66.768 5.701 67.512 6.131 ;
     RECT  80.352 5.365 80.376 6.229 ;
     RECT  48.72 4.787 48.744 6.277 ;
     RECT  11.664 5.509 11.688 6.323 ;
     RECT  29.4 3.539 29.976 6.323 ;
     RECT  34.8 5.747 35.64 6.323 ;
     RECT  50.352 4.787 51.72 6.373 ;
     RECT  52.992 4.741 53.016 6.373 ;
     RECT  50.352 6.373 53.016 6.419 ;
     RECT  56.4 5.653 56.904 6.613 ;
     RECT  60.432 6.133 60.456 6.613 ;
     RECT  71.232 5.029 72.912 6.613 ;
     RECT  70.704 6.613 72.912 6.659 ;
     RECT  51 6.419 53.016 6.707 ;
     RECT  15.168 4.645 15.192 6.805 ;
     RECT  60.432 6.613 60.696 6.805 ;
     RECT  64.896 5.605 65.448 6.805 ;
     RECT  70.704 6.659 70.728 6.805 ;
     RECT  47.472 4.117 47.496 6.851 ;
     RECT  58.272 5.845 58.296 6.851 ;
     RECT  74.112 4.789 74.136 6.851 ;
     RECT  38.208 6.035 38.232 6.853 ;
     RECT  38.112 6.853 38.232 6.899 ;
     RECT  79.488 6.229 80.376 6.947 ;
     RECT  55.824 6.613 56.904 6.949 ;
     RECT  55.344 6.949 56.904 7.139 ;
     RECT  12 6.805 12.024 7.237 ;
     RECT  13.2 4.547 13.512 7.237 ;
     RECT  0.144 7.141 0.168 7.331 ;
     RECT  51 6.707 52.44 7.379 ;
     RECT  83.4 4.019 83.712 7.381 ;
     RECT  78 2.151 78.312 7.429 ;
     RECT  9.408 6.085 9.432 7.475 ;
     RECT  40.2 5.749 41.016 7.475 ;
     RECT  71.856 6.659 72.912 7.475 ;
     RECT  69.984 6.805 70.728 7.571 ;
     RECT  12 7.237 13.512 7.667 ;
     RECT  48.72 6.277 48.984 7.667 ;
     RECT  78 7.429 78.408 7.667 ;
     RECT  45.6 5.845 46.392 7.715 ;
     RECT  54.048 6.661 54.072 7.909 ;
     RECT  63.36 6.805 63.384 7.955 ;
     RECT  29.4 6.323 29.712 7.957 ;
     RECT  30.96 5.747 30.984 7.957 ;
     RECT  54.048 7.909 54.312 7.957 ;
     RECT  55.344 7.139 56.712 7.957 ;
     RECT  59.472 6.805 60.696 7.957 ;
     RECT  61.8 4.931 62.112 7.957 ;
     RECT  67.2 6.131 67.512 7.957 ;
     RECT  17.184 7.381 17.208 8.003 ;
     RECT  64.512 6.805 65.448 8.051 ;
     RECT  64.512 8.051 65.208 8.099 ;
     RECT  52.416 7.379 52.44 8.195 ;
     RECT  51 7.379 51.312 8.197 ;
     RECT  24 5.219 24.312 8.245 ;
     RECT  25.536 6.229 25.56 8.245 ;
     RECT  2.4 2.151 2.712 8.293 ;
     RECT  38.112 6.899 38.136 8.293 ;
     RECT  54.048 7.957 56.712 8.437 ;
     RECT  80.352 6.947 80.376 8.485 ;
     RECT  0.144 8.341 0.168 8.531 ;
     RECT  80.352 8.485 81.288 8.531 ;
     RECT  82.608 7.381 83.712 8.531 ;
     RECT  45.6 7.715 46.152 8.579 ;
     RECT  54.048 8.437 57 8.579 ;
     RECT  40.2 7.475 40.512 8.821 ;
     RECT  18.6 4.501 19.704 8.867 ;
     RECT  70.032 7.571 70.728 8.867 ;
     RECT  78 7.667 78.312 8.917 ;
     RECT  70.032 8.867 70.632 8.963 ;
     RECT  59.472 7.957 62.112 9.011 ;
     RECT  66.72 7.957 67.512 9.013 ;
     RECT  64.512 8.099 64.92 9.059 ;
     RECT  13.2 7.667 13.512 9.061 ;
     RECT  14.832 6.805 15.192 9.061 ;
     RECT  18.6 8.867 18.912 9.061 ;
     RECT  50.88 8.197 51.312 9.061 ;
     RECT  54.048 8.579 56.712 9.109 ;
     RECT  72.6 7.475 72.912 9.109 ;
     RECT  33.6 7.381 33.624 9.155 ;
     RECT  48.72 7.667 48.744 9.155 ;
     RECT  60.432 9.011 62.112 9.155 ;
     RECT  66.144 9.013 67.512 9.155 ;
     RECT  70.032 8.963 70.152 9.299 ;
     RECT  34.8 6.323 35.112 9.397 ;
     RECT  2.4 8.293 3.432 9.683 ;
     RECT  21.12 7.861 21.144 9.683 ;
     RECT  78 8.917 79.272 9.683 ;
     RECT  66.144 9.155 66.168 9.731 ;
     RECT  38.112 8.293 38.808 9.779 ;
     RECT  53.904 9.109 56.712 9.779 ;
     RECT  40.2 8.821 40.872 10.069 ;
     RECT  61.584 9.155 62.112 10.211 ;
     RECT  17.808 9.061 18.912 10.307 ;
     RECT  38.112 9.779 38.136 10.307 ;
     RECT  32.496 9.589 32.52 10.355 ;
     RECT  7.8 4.115 8.112 10.357 ;
     RECT  64.512 9.059 64.536 10.595 ;
     RECT  13.2 9.061 15.192 10.693 ;
     RECT  40.2 10.069 40.968 10.693 ;
     RECT  34.8 9.397 35.64 10.739 ;
     RECT  47.856 9.637 47.88 10.739 ;
     RECT  43.248 10.693 43.272 10.789 ;
     RECT  78 9.683 78.312 10.789 ;
     RECT  2.4 9.683 2.952 10.835 ;
     RECT  6.864 10.357 8.112 10.883 ;
     RECT  59.088 10.261 59.112 10.883 ;
     RECT  72.48 9.109 72.912 10.883 ;
     RECT  70.032 9.299 70.056 10.931 ;
     RECT  50.736 9.061 51.312 10.981 ;
     RECT  54.72 9.779 56.712 11.027 ;
     RECT  42.816 10.789 43.272 11.077 ;
     RECT  45.6 8.579 45.912 11.077 ;
     RECT  34.8 10.739 35.112 11.173 ;
     RECT  45.6 11.077 46.008 11.219 ;
     RECT  24 8.245 25.56 11.365 ;
     RECT  42.432 11.077 43.272 11.365 ;
     RECT  54.72 11.027 54.744 11.365 ;
     RECT  9.456 10.213 9.48 11.411 ;
     RECT  76.176 10.837 76.2 11.411 ;
     RECT  55.776 11.027 56.712 11.413 ;
     RECT  55.776 11.413 56.856 11.459 ;
     RECT  50.112 10.981 51.312 11.509 ;
     RECT  52.656 11.365 53.16 11.509 ;
     RECT  44.256 11.413 44.28 11.555 ;
     RECT  45.6 11.219 45.912 11.557 ;
     RECT  47.328 11.221 47.352 11.747 ;
     RECT  55.92 11.459 56.856 11.795 ;
     RECT  5.856 10.165 5.88 11.845 ;
     RECT  13.2 10.693 16.008 11.939 ;
     RECT  4.512 5.459 4.536 11.941 ;
     RECT  5.856 11.845 6.408 11.941 ;
     RECT  13.2 11.939 15.96 11.941 ;
     RECT  34.176 11.173 35.112 12.035 ;
     RECT  45.504 11.557 45.912 12.421 ;
     RECT  29.4 7.957 30.984 12.469 ;
     RECT  50.112 11.509 53.16 12.517 ;
     RECT  78 10.789 78.888 12.517 ;
     RECT  83.4 8.531 83.712 12.517 ;
     RECT  4.512 11.941 6.408 12.563 ;
     RECT  12.528 11.941 15.96 12.563 ;
     RECT  21.648 11.509 21.672 12.563 ;
     RECT  65.568 11.365 65.592 12.563 ;
     RECT  42.096 11.365 43.272 12.565 ;
     RECT  50.112 12.517 53.496 12.565 ;
     RECT  49.968 12.565 53.496 12.707 ;
     RECT  23.376 11.365 25.56 12.803 ;
     RECT  23.376 12.803 25.416 12.851 ;
     RECT  63.792 11.941 63.816 12.901 ;
     RECT  63.552 12.901 63.816 12.947 ;
     RECT  4.512 12.563 5.88 12.995 ;
     RECT  4.512 12.995 4.536 12.997 ;
     RECT  4.032 12.997 4.536 13.043 ;
     RECT  9.408 12.709 9.432 13.045 ;
     RECT  37.008 12.325 37.032 13.045 ;
     RECT  39.984 10.693 40.968 13.045 ;
     RECT  45.504 12.421 46.104 13.091 ;
     RECT  42.096 12.565 44.328 13.093 ;
     RECT  39.744 13.045 40.968 13.189 ;
     RECT  42.096 13.093 44.472 13.189 ;
     RECT  23.376 12.851 24.312 13.237 ;
     RECT  38.304 11.893 38.328 13.237 ;
     RECT  32.448 13.045 32.472 13.283 ;
     RECT  60.432 9.155 60.456 13.285 ;
     RECT  60.432 13.285 60.648 13.331 ;
     RECT  83.28 12.517 83.712 13.379 ;
     RECT  68.928 13.141 68.952 13.427 ;
     RECT  60.624 13.331 60.648 13.429 ;
     RECT  23.28 13.237 24.312 13.475 ;
     RECT  38.256 13.237 38.328 13.475 ;
     RECT  12.528 12.563 13.512 13.477 ;
     RECT  9.12 13.045 9.432 13.523 ;
     RECT  34.8 12.035 35.112 13.525 ;
     RECT  36.192 13.045 37.032 13.525 ;
     RECT  72.6 10.883 72.912 13.573 ;
     RECT  15.168 12.563 15.96 13.621 ;
     RECT  77.472 12.517 78.888 13.621 ;
     RECT  15.168 13.621 16.584 13.667 ;
     RECT  38.304 13.475 38.328 13.717 ;
     RECT  39.744 13.189 44.472 13.763 ;
     RECT  44.448 13.763 44.472 13.859 ;
     RECT  38.304 13.717 38.376 14.005 ;
     RECT  39.744 13.763 43.272 14.005 ;
     RECT  77.184 13.621 78.888 14.005 ;
     RECT  45.504 13.091 45.912 14.053 ;
     RECT  11.76 13.477 13.512 14.099 ;
     RECT  63.552 12.947 63.576 14.101 ;
     RECT  60.624 13.429 60.744 14.147 ;
     RECT  50.112 12.707 53.496 14.149 ;
     RECT  76.032 11.845 76.056 14.197 ;
     RECT  29.28 12.469 30.984 14.245 ;
     RECT  54.528 11.365 54.744 14.245 ;
     RECT  55.92 11.795 56.712 14.245 ;
     RECT  72.48 13.573 72.912 14.387 ;
     RECT  58.848 14.341 58.872 14.389 ;
     RECT  45.12 14.053 45.912 14.483 ;
     RECT  58.848 14.389 59.256 14.485 ;
     RECT  34.8 13.525 37.032 14.531 ;
     RECT  77.184 14.005 79.176 14.531 ;
     RECT  49.824 14.149 53.496 14.533 ;
     RECT  54.528 14.245 56.712 14.533 ;
     RECT  49.824 14.533 56.712 14.629 ;
     RECT  49.584 14.629 56.712 14.773 ;
     RECT  77.184 14.531 78.888 14.867 ;
     RECT  38.304 14.005 43.272 14.869 ;
     RECT  17.568 13.861 17.592 14.915 ;
     RECT  18.6 10.307 18.912 14.917 ;
     RECT  69.936 11.941 69.96 14.917 ;
     RECT  63.552 14.101 63.672 14.963 ;
     RECT  49.392 14.773 56.712 14.965 ;
     RECT  2.4 10.835 2.712 15.061 ;
     RECT  9.12 13.523 9.144 15.061 ;
     RECT  58.848 14.485 59.64 15.107 ;
     RECT  29.28 14.245 31.368 15.157 ;
     RECT  33.072 14.101 33.096 15.157 ;
     RECT  38.256 14.869 43.272 15.299 ;
     RECT  49.392 14.965 57.096 15.301 ;
     RECT  15.408 13.667 16.584 15.443 ;
     RECT  20.64 14.245 20.664 15.443 ;
     RECT  29.28 15.157 33.096 15.443 ;
     RECT  45.264 14.483 45.912 15.443 ;
     RECT  60.72 14.147 60.744 15.443 ;
     RECT  72.6 14.387 72.912 15.445 ;
     RECT  38.304 15.299 43.272 15.491 ;
     RECT  75.984 14.197 76.056 15.491 ;
     RECT  67.2 9.155 67.512 15.493 ;
     RECT  69.936 14.917 70.104 15.589 ;
     RECT  67.104 15.493 67.512 15.635 ;
     RECT  29.28 15.443 32.28 15.683 ;
     RECT  24 13.475 24.312 15.685 ;
     RECT  25.392 12.851 25.416 15.685 ;
     RECT  34.8 14.531 36.36 15.781 ;
     RECT  38.304 15.491 43.128 15.923 ;
     RECT  5.856 12.995 5.88 15.973 ;
     RECT  9.12 15.061 9.96 16.019 ;
     RECT  18.48 14.917 18.912 16.019 ;
     RECT  32.256 15.683 32.28 16.019 ;
     RECT  49.392 15.301 57.384 16.021 ;
     RECT  34.8 15.781 37.08 16.211 ;
     RECT  69.504 15.589 70.104 16.213 ;
     RECT  71.184 14.773 71.208 16.213 ;
     RECT  80.256 15.205 80.28 16.213 ;
     RECT  81.264 8.531 81.288 16.213 ;
     RECT  24 15.685 25.416 16.259 ;
     RECT  69.504 16.213 71.208 16.259 ;
     RECT  80.256 16.213 81.288 16.259 ;
     RECT  34.8 16.211 36.408 16.357 ;
     RECT  2.4 15.061 3 16.403 ;
     RECT  38.304 15.923 42.84 16.405 ;
     RECT  38.064 16.405 42.84 16.451 ;
     RECT  34.656 16.357 36.408 16.499 ;
     RECT  15.408 15.443 15.96 16.501 ;
     RECT  29.28 15.683 31.08 16.501 ;
     RECT  59.232 15.107 59.64 16.501 ;
     RECT  9.12 16.019 9.144 16.595 ;
     RECT  24 16.259 25.176 16.595 ;
     RECT  70.08 16.259 70.728 16.595 ;
     RECT  45.6 15.443 45.912 16.597 ;
     RECT  45.024 16.597 45.912 16.693 ;
     RECT  47.376 15.349 47.4 16.693 ;
     RECT  5.04 15.973 5.88 16.835 ;
     RECT  45.024 16.693 47.4 16.835 ;
     RECT  13.2 14.099 13.512 16.885 ;
     RECT  45.12 16.835 47.4 16.931 ;
     RECT  49.056 16.021 57.384 17.029 ;
     RECT  13.056 16.885 13.512 17.075 ;
     RECT  33.648 16.501 33.672 17.075 ;
     RECT  80.448 16.259 81.288 17.075 ;
     RECT  38.064 16.451 42.6 17.077 ;
     RECT  61.8 10.211 62.112 17.077 ;
     RECT  67.2 15.635 67.512 17.077 ;
     RECT  45.216 16.931 47.4 17.123 ;
     RECT  22.944 16.261 22.968 17.171 ;
     RECT  29.232 16.501 31.08 17.173 ;
     RECT  45.6 17.123 47.4 17.219 ;
     RECT  60.96 17.077 62.112 17.219 ;
     RECT  29.088 17.173 31.08 17.267 ;
     RECT  78 14.867 78.888 17.269 ;
     RECT  70.704 16.595 70.728 17.315 ;
     RECT  81.024 17.075 81.288 17.315 ;
     RECT  29.088 17.267 29.712 17.459 ;
     RECT  37.632 17.077 42.6 17.557 ;
     RECT  47.376 17.219 47.4 17.605 ;
     RECT  59.232 16.501 59.832 17.605 ;
     RECT  63.648 14.963 63.672 17.699 ;
     RECT  37.632 17.557 43.224 17.749 ;
     RECT  32.16 17.077 32.184 17.891 ;
     RECT  34.656 16.499 36.36 17.989 ;
     RECT  72.6 15.445 73.8 17.989 ;
     RECT  48.864 17.029 57.384 18.035 ;
     RECT  58.752 17.605 59.832 18.037 ;
     RECT  34.656 17.989 36.456 18.085 ;
     RECT  37.632 17.749 43.512 18.085 ;
     RECT  67.2 17.077 68.28 18.179 ;
     RECT  81.024 17.315 81.048 18.179 ;
     RECT  5.856 16.835 5.88 18.181 ;
     RECT  34.656 18.085 43.512 18.325 ;
     RECT  34.656 18.325 43.704 18.419 ;
     RECT  31.056 17.267 31.08 18.421 ;
     RECT  58.752 18.037 60.744 18.421 ;
     RECT  61.8 17.219 62.112 18.421 ;
     RECT  31.056 18.421 31.32 18.467 ;
     RECT  45.6 17.219 45.912 18.469 ;
     RECT  47.376 17.605 47.592 18.469 ;
     RECT  5.856 18.181 5.976 18.565 ;
     RECT  83.4 13.379 83.712 18.565 ;
     RECT  5.376 18.565 5.976 18.611 ;
     RECT  37.824 18.419 43.704 18.611 ;
     RECT  45.6 18.469 47.592 18.659 ;
     RECT  37.872 18.611 43.704 18.661 ;
     RECT  58.752 18.421 62.112 18.707 ;
     RECT  76.368 15.637 76.392 18.755 ;
     RECT  45.6 18.659 47.4 18.899 ;
     RECT  27.792 18.181 27.816 18.995 ;
     RECT  83.184 18.565 83.712 19.189 ;
     RECT  18.6 16.019 18.912 19.237 ;
     RECT  24 16.595 24.312 19.237 ;
     RECT  49.056 18.035 57.384 19.285 ;
     RECT  18.6 19.237 19.032 19.333 ;
     RECT  5.376 18.611 5.88 19.379 ;
     RECT  72.6 17.989 73.848 19.379 ;
     RECT  37.872 18.661 43.8 19.429 ;
     RECT  7.8 10.883 8.112 19.477 ;
     RECT  9.36 18.229 9.384 19.477 ;
     RECT  31.296 18.467 31.32 19.619 ;
     RECT  5.664 19.379 5.88 19.669 ;
     RECT  34.656 18.419 36.456 19.715 ;
     RECT  45.6 18.899 46.44 19.715 ;
     RECT  37.872 19.429 44.328 19.717 ;
     RECT  45.6 19.715 45.912 19.717 ;
     RECT  18.6 19.333 19.128 19.811 ;
     RECT  13.2 17.075 13.512 19.813 ;
     RECT  37.872 19.717 45.912 19.859 ;
     RECT  61.68 18.707 62.112 19.909 ;
     RECT  13.104 19.813 13.608 19.955 ;
     RECT  4.032 13.043 4.056 20.003 ;
     RECT  7.8 19.477 9.384 20.003 ;
     RECT  82.656 19.189 83.712 20.003 ;
     RECT  33.024 18.565 33.048 20.051 ;
     RECT  48.864 19.285 57.384 20.053 ;
     RECT  5.664 19.669 6.408 20.147 ;
     RECT  46.896 20.005 46.92 20.149 ;
     RECT  5.856 20.147 6.408 20.195 ;
     RECT  22.8 19.813 22.824 20.291 ;
     RECT  46.896 20.149 47.736 20.291 ;
     RECT  15.408 16.501 16.2 20.339 ;
     RECT  24 19.237 24.504 20.339 ;
     RECT  48.864 20.053 57.432 20.339 ;
     RECT  34.8 19.715 36.456 20.533 ;
     RECT  58.752 18.707 60.504 20.629 ;
     RECT  78 17.269 79.608 20.725 ;
     RECT  80.784 20.197 80.808 20.725 ;
     RECT  77.856 20.725 80.808 20.867 ;
     RECT  18.6 19.811 18.912 20.965 ;
     RECT  67.2 18.179 67.512 20.965 ;
     RECT  18.432 20.965 18.912 21.061 ;
     RECT  45.6 19.859 45.912 21.061 ;
     RECT  46.896 20.291 47.544 21.061 ;
     RECT  49.008 20.339 57.432 21.061 ;
     RECT  34.8 20.533 37.08 21.107 ;
     RECT  7.8 20.003 8.952 21.109 ;
     RECT  49.008 21.061 57.576 21.157 ;
     RECT  58.656 20.629 60.504 21.157 ;
     RECT  38.544 19.859 44.616 21.205 ;
     RECT  45.6 21.061 47.544 21.205 ;
     RECT  7.8 21.109 9.432 21.251 ;
     RECT  38.544 21.205 47.544 21.347 ;
     RECT  64.992 20.437 65.016 21.395 ;
     RECT  49.008 21.157 60.504 21.397 ;
     RECT  11.76 14.099 11.784 21.493 ;
     RECT  13.2 19.955 13.608 21.493 ;
     RECT  77.856 20.867 80.184 21.539 ;
     RECT  34.8 21.107 36.456 21.635 ;
     RECT  45.6 21.347 47.544 21.637 ;
     RECT  75.168 20.725 75.192 21.683 ;
     RECT  78 21.539 80.184 21.683 ;
     RECT  81.936 20.965 81.96 21.683 ;
     RECT  38.544 21.347 44.232 21.731 ;
     RECT  34.8 21.635 36.36 21.781 ;
     RECT  5.856 20.195 5.88 21.973 ;
     RECT  17.616 21.061 18.912 22.163 ;
     RECT  67.2 20.965 68.184 22.165 ;
     RECT  80.16 21.683 80.184 22.211 ;
     RECT  48.96 21.397 60.504 22.405 ;
     RECT  37.536 21.877 37.56 22.597 ;
     RECT  38.544 21.731 43.8 22.597 ;
     RECT  37.536 22.597 43.8 22.739 ;
     RECT  7.8 21.251 8.952 22.741 ;
     RECT  24 20.339 24.312 22.933 ;
     RECT  38.496 22.739 43.8 22.933 ;
     RECT  45.6 21.637 47.784 22.979 ;
     RECT  24 22.933 25.128 23.075 ;
     RECT  48.768 22.405 60.504 23.123 ;
     RECT  38.496 22.933 43.992 23.171 ;
     RECT  47.328 22.979 47.784 23.171 ;
     RECT  29.232 17.459 29.712 23.269 ;
     RECT  30.768 22.741 30.792 23.269 ;
     RECT  47.568 23.171 47.784 23.269 ;
     RECT  7.68 22.741 9.672 23.315 ;
     RECT  29.232 23.269 30.792 23.315 ;
     RECT  18.192 22.163 18.912 23.317 ;
     RECT  72.6 19.379 73.8 23.317 ;
     RECT  34.176 21.781 36.36 23.363 ;
     RECT  7.8 23.315 9.672 23.411 ;
     RECT  14.832 23.413 14.856 23.795 ;
     RECT  7.8 23.411 8.952 23.843 ;
     RECT  5.376 21.973 5.88 23.845 ;
     RECT  74.928 23.701 74.952 23.893 ;
     RECT  4.704 23.845 5.88 24.083 ;
     RECT  61.68 19.909 62.664 24.085 ;
     RECT  67.2 22.165 68.232 24.085 ;
     RECT  69.216 22.741 69.24 24.085 ;
     RECT  27.648 22.357 27.672 24.131 ;
     RECT  47.568 23.269 47.976 24.131 ;
     RECT  33.504 23.845 33.528 24.323 ;
     RECT  34.56 23.363 36.36 24.325 ;
     RECT  17.664 23.317 18.912 24.371 ;
     RECT  31.872 23.605 31.896 24.419 ;
     RECT  61.68 24.085 62.76 24.467 ;
     RECT  21.072 23.317 21.096 24.515 ;
     RECT  72.24 23.317 73.8 24.515 ;
     RECT  49.104 23.123 60.504 24.611 ;
     RECT  65.088 23.989 65.112 24.659 ;
     RECT  67.2 24.085 69.24 24.659 ;
     RECT  24 23.075 24.312 24.661 ;
     RECT  23.904 24.661 24.312 24.851 ;
     RECT  14.736 23.893 14.76 24.899 ;
     RECT  74.832 23.893 74.952 24.899 ;
     RECT  45.6 22.979 45.912 25.045 ;
     RECT  47.568 24.131 47.688 25.139 ;
     RECT  34.56 24.325 37.032 25.141 ;
     RECT  29.232 23.315 30.6 25.189 ;
     RECT  7.8 23.843 8.904 25.235 ;
     RECT  34.56 25.141 37.08 25.237 ;
     RECT  34.56 25.237 37.176 25.283 ;
     RECT  18.24 24.371 18.912 25.331 ;
     RECT  24 24.851 24.312 25.429 ;
     RECT  29.184 25.189 30.6 25.523 ;
     RECT  78 21.683 78.888 25.525 ;
     RECT  49.104 24.611 59.304 25.571 ;
     RECT  60.48 24.611 60.504 25.573 ;
     RECT  36.336 25.283 37.176 25.621 ;
     RECT  38.496 23.171 43.896 25.621 ;
     RECT  45.312 25.045 45.912 25.621 ;
     RECT  27.36 25.045 27.384 25.715 ;
     RECT  38.496 25.621 45.912 25.715 ;
     RECT  61.68 24.467 62.664 25.715 ;
     RECT  36.336 25.621 37.272 25.763 ;
     RECT  69.216 24.659 69.24 25.765 ;
     RECT  0.144 25.765 0.168 25.955 ;
     RECT  80.688 23.941 80.712 26.003 ;
     RECT  5.376 24.083 5.88 26.005 ;
     RECT  34.56 25.283 35.256 26.053 ;
     RECT  74.928 24.899 74.952 26.053 ;
     RECT  74.928 26.053 75.24 26.099 ;
     RECT  32.4 25.333 32.424 26.243 ;
     RECT  38.496 25.715 44.52 26.243 ;
     RECT  70.656 25.669 70.68 26.243 ;
     RECT  49.104 25.571 58.68 26.245 ;
     RECT  11.76 21.493 13.608 26.291 ;
     RECT  64.944 25.573 64.968 26.291 ;
     RECT  77.904 25.525 78.888 26.291 ;
     RECT  38.496 26.243 44.04 26.389 ;
     RECT  45.6 25.715 45.912 26.437 ;
     RECT  72.6 24.515 73.8 26.629 ;
     RECT  7.8 25.235 8.112 26.677 ;
     RECT  14.784 26.101 14.808 26.677 ;
     RECT  29.232 25.523 30.6 26.725 ;
     RECT  29.232 26.725 30.792 26.771 ;
     RECT  16.176 20.339 16.2 26.773 ;
     RECT  38.352 26.389 44.04 26.773 ;
     RECT  67.2 24.659 67.512 26.773 ;
     RECT  27.072 26.197 27.096 26.819 ;
     RECT  34.224 26.053 35.256 26.819 ;
     RECT  36.336 25.763 36.456 26.917 ;
     RECT  37.68 26.773 44.04 26.917 ;
     RECT  48.624 26.245 58.68 26.965 ;
     RECT  59.856 25.573 60.504 26.965 ;
     RECT  14.784 26.677 15.144 27.059 ;
     RECT  34.224 26.819 35.112 27.059 ;
     RECT  11.76 26.291 13.512 27.107 ;
     RECT  7.632 26.677 8.112 27.205 ;
     RECT  18.432 25.331 18.912 27.205 ;
     RECT  21.12 27.109 21.144 27.205 ;
     RECT  11.808 27.107 13.512 27.251 ;
     RECT  36.336 26.917 44.04 27.251 ;
     RECT  13.2 27.251 13.512 27.301 ;
     RECT  48.624 26.965 60.504 27.347 ;
     RECT  47.568 25.139 47.592 27.349 ;
     RECT  48.624 27.347 60.456 27.349 ;
     RECT  33.024 27.301 33.048 27.397 ;
     RECT  32.928 27.397 33.048 27.445 ;
     RECT  21.12 27.205 21.432 27.491 ;
     RECT  38.496 27.251 44.04 27.541 ;
     RECT  45.6 26.437 46.392 27.541 ;
     RECT  34.272 27.059 35.112 27.587 ;
     RECT  5.136 26.005 5.88 27.779 ;
     RECT  32.208 27.445 33.048 27.779 ;
     RECT  16.176 26.773 16.392 27.827 ;
     RECT  29.232 26.771 29.712 27.877 ;
     RECT  30.768 26.771 30.792 27.877 ;
     RECT  0.144 27.637 0.168 27.923 ;
     RECT  29.232 27.877 30.792 27.923 ;
     RECT  19.968 27.109 19.992 27.971 ;
     RECT  29.232 27.923 30.696 28.165 ;
     RECT  61.8 25.715 62.664 28.213 ;
     RECT  72.192 26.629 73.8 28.259 ;
     RECT  32.928 27.779 33.048 28.307 ;
     RECT  61.8 28.213 63 28.355 ;
     RECT  38.496 27.541 46.392 28.357 ;
     RECT  47.568 27.349 60.456 28.357 ;
     RECT  15.12 27.059 15.144 28.403 ;
     RECT  24 25.429 24.936 28.405 ;
     RECT  38.496 28.357 60.456 28.451 ;
     RECT  13.2 27.301 13.656 28.453 ;
     RECT  16.176 27.827 16.2 28.453 ;
     RECT  17.616 27.205 18.912 28.547 ;
     RECT  68.64 25.765 69.24 28.547 ;
     RECT  70.752 27.877 70.776 28.547 ;
     RECT  32.928 28.307 32.952 28.643 ;
     RECT  36.336 27.251 37.128 28.645 ;
     RECT  66.624 26.773 67.512 28.645 ;
     RECT  34.416 27.587 35.112 28.787 ;
     RECT  34.8 28.787 35.112 28.789 ;
     RECT  64.416 27.877 64.44 28.931 ;
     RECT  72.6 28.259 73.8 28.931 ;
     RECT  27.024 27.253 27.048 28.933 ;
     RECT  36.336 28.645 37.176 28.979 ;
     RECT  5.856 27.779 5.88 28.981 ;
     RECT  27.024 28.933 27.912 28.981 ;
     RECT  29.088 28.165 30.696 28.981 ;
     RECT  65.904 28.645 67.512 29.027 ;
     RECT  75.216 26.099 75.24 29.029 ;
     RECT  38.496 28.451 59.976 29.075 ;
     RECT  74.688 29.029 75.24 29.075 ;
     RECT  13.2 28.453 13.992 29.123 ;
     RECT  27.024 28.981 30.696 29.123 ;
     RECT  69.216 28.547 69.24 29.123 ;
     RECT  36.336 28.979 36.552 29.221 ;
     RECT  34.8 28.789 35.208 29.317 ;
     RECT  36.24 29.221 36.552 29.317 ;
     RECT  27.888 29.123 30.696 29.363 ;
     RECT  65.904 29.027 65.928 29.459 ;
     RECT  81.504 27.301 81.528 29.459 ;
     RECT  16.032 28.453 16.2 29.461 ;
     RECT  24 28.405 25.416 29.507 ;
     RECT  27.888 29.363 29.712 29.699 ;
     RECT  15.984 29.461 16.2 29.893 ;
     RECT  18.432 28.547 18.912 30.133 ;
     RECT  11.808 27.251 11.832 30.181 ;
     RECT  13.2 29.123 13.512 30.181 ;
     RECT  15.648 29.893 16.2 30.181 ;
     RECT  61.8 28.355 62.952 30.181 ;
     RECT  67.2 29.027 67.512 30.181 ;
     RECT  78 26.291 78.888 30.229 ;
     RECT  5.088 28.981 5.88 30.275 ;
     RECT  30.768 30.037 30.792 30.275 ;
     RECT  24 29.507 25.176 30.421 ;
     RECT  32.64 29.317 32.664 30.421 ;
     RECT  38.496 29.075 46.392 30.469 ;
     RECT  47.568 29.075 59.928 30.469 ;
     RECT  70.272 30.277 70.296 30.469 ;
     RECT  11.808 30.181 13.512 30.565 ;
     RECT  15.648 30.181 16.584 30.611 ;
     RECT  70.272 30.469 70.728 30.611 ;
     RECT  26.736 30.661 26.76 30.709 ;
     RECT  72.6 28.931 72.912 30.709 ;
     RECT  38.496 30.469 59.928 30.755 ;
     RECT  7.632 27.205 8.856 30.757 ;
     RECT  26.592 30.709 26.76 30.757 ;
     RECT  48.576 30.755 59.928 30.757 ;
     RECT  83.4 20.003 83.712 30.757 ;
     RECT  5.712 30.275 5.88 30.803 ;
     RECT  16.032 30.611 16.584 30.803 ;
     RECT  48.576 30.757 60.168 30.803 ;
     RECT  16.176 30.803 16.584 30.851 ;
     RECT  32.64 30.421 32.76 30.899 ;
     RECT  59.616 30.803 60.168 30.949 ;
     RECT  61.8 30.181 63.864 30.949 ;
     RECT  26.592 30.757 26.856 30.995 ;
     RECT  11.808 30.565 14.424 31.043 ;
     RECT  18.432 30.133 19.08 31.237 ;
     RECT  10.416 30.757 10.44 31.379 ;
     RECT  11.808 31.043 13.512 31.379 ;
     RECT  23.04 30.421 25.176 31.379 ;
     RECT  32.64 30.899 32.664 31.379 ;
     RECT  70.272 30.611 70.296 31.379 ;
     RECT  5.856 30.803 5.88 31.381 ;
     RECT  6.864 30.757 8.856 31.381 ;
     RECT  59.616 30.949 63.864 31.427 ;
     RECT  78 30.229 79.8 31.667 ;
     RECT  66.768 30.181 67.512 31.669 ;
     RECT  48.576 30.803 58.632 31.859 ;
     RECT  82.656 30.757 83.712 31.859 ;
     RECT  26.592 30.995 26.712 31.907 ;
     RECT  72.096 30.709 72.912 31.907 ;
     RECT  38.496 30.755 47.592 31.955 ;
     RECT  75.744 30.709 75.768 31.955 ;
     RECT  48.672 31.859 58.632 32.003 ;
     RECT  26.688 31.907 26.712 32.147 ;
     RECT  16.176 30.851 16.2 32.197 ;
     RECT  74.688 29.075 74.712 32.243 ;
     RECT  16.176 32.197 16.68 32.339 ;
     RECT  33.072 32.197 33.096 32.339 ;
     RECT  23.904 31.379 25.176 32.341 ;
     RECT  66.768 31.669 67.608 32.435 ;
     RECT  11.808 31.379 11.832 32.437 ;
     RECT  18.432 31.237 19.944 32.531 ;
     RECT  48.672 32.003 58.44 32.531 ;
     RECT  48.96 32.531 58.44 32.579 ;
     RECT  31.68 32.341 31.704 32.771 ;
     RECT  49.008 32.579 58.44 32.963 ;
     RECT  2.4 16.403 2.712 33.013 ;
     RECT  18.432 32.531 19.08 33.013 ;
     RECT  23.904 32.341 25.224 33.013 ;
     RECT  5.856 31.381 8.856 33.061 ;
     RECT  16.176 32.339 16.2 33.061 ;
     RECT  38.592 31.955 47.592 33.107 ;
     RECT  2.4 33.013 2.856 33.155 ;
     RECT  67.2 32.435 67.608 33.299 ;
     RECT  59.616 31.427 62.952 33.347 ;
     RECT  33.696 32.389 33.72 33.539 ;
     RECT  38.784 33.107 47.592 33.539 ;
     RECT  4.656 33.013 4.68 33.541 ;
     RECT  5.856 33.061 9.72 33.541 ;
     RECT  4.656 33.541 9.72 33.587 ;
     RECT  15.264 33.061 16.2 33.587 ;
     RECT  13.2 31.379 13.512 33.589 ;
     RECT  18.048 33.013 19.08 33.589 ;
     RECT  11.808 32.437 12.168 33.635 ;
     RECT  23.712 33.013 25.608 33.635 ;
     RECT  70.464 32.869 70.488 33.731 ;
     RECT  27.888 29.699 27.912 33.829 ;
     RECT  29.232 29.699 29.712 33.829 ;
     RECT  74.208 32.437 74.232 33.875 ;
     RECT  27.888 33.829 29.712 33.973 ;
     RECT  5.088 33.587 9.72 34.067 ;
     RECT  39.264 33.539 47.592 34.067 ;
     RECT  34.8 29.317 36.552 34.165 ;
     RECT  66.144 32.437 66.168 34.165 ;
     RECT  67.2 33.299 67.512 34.165 ;
     RECT  12.144 33.635 12.168 34.259 ;
     RECT  39.696 34.067 47.592 34.355 ;
     RECT  82.08 34.213 82.104 34.355 ;
     RECT  66.144 34.165 67.512 34.403 ;
     RECT  39.696 34.355 44.04 34.499 ;
     RECT  13.2 33.589 14.136 34.595 ;
     RECT  45.504 34.355 47.592 34.597 ;
     RECT  5.088 34.067 5.928 34.643 ;
     RECT  45.504 34.597 47.88 34.643 ;
     RECT  24 33.635 25.608 34.693 ;
     RECT  45.504 34.643 46.728 34.739 ;
     RECT  67.2 34.403 67.512 34.741 ;
     RECT  64.416 33.637 64.44 34.883 ;
     RECT  34.032 34.165 36.552 34.931 ;
     RECT  45.6 34.739 46.728 34.931 ;
     RECT  16.176 33.587 16.2 34.933 ;
     RECT  17.856 33.589 19.08 34.933 ;
     RECT  27.888 33.973 29.832 35.077 ;
     RECT  59.616 33.347 60.168 35.123 ;
     RECT  67.2 34.741 68.376 35.123 ;
     RECT  27.888 35.077 30.744 35.219 ;
     RECT  78 31.667 78.888 35.269 ;
     RECT  22.752 34.741 22.776 35.363 ;
     RECT  39.696 34.499 43.992 35.363 ;
     RECT  39.696 35.363 40.728 35.411 ;
     RECT  16.176 34.933 19.08 35.413 ;
     RECT  24 34.693 25.896 35.459 ;
     RECT  24 35.459 25.176 35.461 ;
     RECT  16.176 35.413 19.992 35.555 ;
     RECT  17.856 35.555 19.992 35.891 ;
     RECT  30.72 35.219 30.744 35.893 ;
     RECT  5.856 34.643 5.928 35.939 ;
     RECT  30.72 35.893 30.84 35.939 ;
     RECT  47.856 34.643 47.88 35.939 ;
     RECT  77.472 35.269 78.888 35.939 ;
     RECT  70.896 34.741 70.92 35.987 ;
     RECT  2.4 33.155 2.712 35.989 ;
     RECT  42.096 35.363 43.992 35.989 ;
     RECT  13.2 34.595 13.512 36.133 ;
     RECT  42.096 35.989 44.04 36.227 ;
     RECT  17.856 35.891 19.08 36.275 ;
     RECT  39.84 35.411 40.728 36.275 ;
     RECT  77.472 35.939 78.696 36.323 ;
     RECT  17.856 36.275 18.912 36.371 ;
     RECT  65.04 36.277 65.064 36.419 ;
     RECT  42.096 36.227 43.992 36.515 ;
     RECT  77.472 36.323 78.312 36.515 ;
     RECT  30.816 35.939 30.84 36.563 ;
     RECT  2.4 35.989 3.336 36.659 ;
     RECT  16.176 35.555 16.2 36.661 ;
     RECT  56.4 32.963 58.44 36.755 ;
     RECT  61.8 33.347 62.952 36.853 ;
     RECT  66.144 34.403 66.168 36.899 ;
     RECT  7.632 34.067 9.72 36.997 ;
     RECT  80.064 32.341 80.088 36.997 ;
     RECT  79.824 36.997 80.088 37.043 ;
     RECT  13.2 36.133 13.608 37.091 ;
     RECT  49.056 32.963 55.368 37.091 ;
     RECT  60.144 35.123 60.168 37.091 ;
     RECT  26.784 36.037 26.808 37.093 ;
     RECT  27.888 35.219 29.712 37.093 ;
     RECT  67.2 35.123 67.512 37.093 ;
     RECT  55.104 37.091 55.128 37.187 ;
     RECT  58.416 36.755 58.44 37.189 ;
     RECT  23.856 35.461 25.176 37.619 ;
     RECT  24 37.619 25.176 37.621 ;
     RECT  26.784 37.093 29.712 37.621 ;
     RECT  6.912 36.997 9.72 37.667 ;
     RECT  79.824 37.043 79.848 37.667 ;
     RECT  6.912 37.667 8.856 37.859 ;
     RECT  70.224 36.757 70.248 37.859 ;
     RECT  34.8 34.931 36.552 37.957 ;
     RECT  67.104 37.093 67.512 38.003 ;
     RECT  24 37.621 29.712 38.099 ;
     RECT  42.096 36.515 43.944 38.099 ;
     RECT  24 38.099 26.808 38.147 ;
     RECT  42.336 38.099 43.944 38.195 ;
     RECT  58.416 37.189 58.584 38.195 ;
     RECT  67.2 38.003 67.512 38.341 ;
     RECT  15.552 36.661 16.2 38.387 ;
     RECT  18.432 36.371 18.912 38.389 ;
     RECT  67.2 38.341 68.424 38.483 ;
     RECT  61.488 36.853 62.952 38.531 ;
     RECT  56.4 36.755 56.808 38.581 ;
     RECT  49.056 37.091 53.64 38.723 ;
     RECT  42.48 38.195 43.944 38.771 ;
     RECT  56.4 38.581 56.856 38.771 ;
     RECT  58.416 38.195 58.44 38.819 ;
     RECT  27.888 38.099 29.712 39.061 ;
     RECT  16.176 38.387 16.2 39.107 ;
     RECT  24 38.147 24.312 39.205 ;
     RECT  24 39.205 24.456 39.301 ;
     RECT  58.128 39.109 58.152 39.395 ;
     RECT  39.84 36.275 40.512 39.493 ;
     RECT  39.84 39.493 40.632 39.539 ;
     RECT  53.616 38.723 53.64 39.685 ;
     RECT  25.92 38.147 26.808 39.781 ;
     RECT  27.888 39.061 30.024 39.781 ;
     RECT  45.6 34.931 45.912 39.781 ;
     RECT  39.888 39.539 40.632 39.827 ;
     RECT  4.608 39.061 4.632 39.923 ;
     RECT  25.92 39.781 30.024 40.259 ;
     RECT  49.056 38.723 52.488 40.309 ;
     RECT  53.616 39.685 54.6 40.309 ;
     RECT  49.056 40.309 54.6 40.355 ;
     RECT  42.48 38.771 42.504 40.451 ;
     RECT  45.6 39.781 46.392 40.451 ;
     RECT  43.488 38.771 43.944 40.547 ;
     RECT  69.504 40.405 69.528 40.549 ;
     RECT  23.376 39.301 24.456 40.595 ;
     RECT  38.112 40.453 38.136 40.595 ;
     RECT  49.056 40.355 54.312 40.645 ;
     RECT  39.888 39.827 40.512 40.691 ;
     RECT  56.4 38.771 56.808 40.885 ;
     RECT  40.032 40.691 40.512 40.931 ;
     RECT  2.4 36.659 2.712 40.933 ;
     RECT  5.856 35.939 5.88 40.933 ;
     RECT  7.632 37.859 8.856 40.933 ;
     RECT  56.4 40.885 57.48 41.029 ;
     RECT  43.488 40.547 43.512 41.075 ;
     RECT  45.6 40.451 45.912 41.173 ;
     RECT  13.2 37.091 13.512 41.269 ;
     RECT  72.6 31.907 72.912 41.413 ;
     RECT  24 40.595 24.456 41.459 ;
     RECT  55.728 41.029 57.48 41.459 ;
     RECT  75.168 40.357 75.192 41.459 ;
     RECT  40.2 40.931 40.512 41.557 ;
     RECT  71.856 41.413 72.912 41.557 ;
     RECT  2.4 40.933 2.808 41.699 ;
     RECT  64.992 40.789 65.016 41.699 ;
     RECT  67.2 38.483 67.512 41.749 ;
     RECT  81.456 39.877 81.48 41.749 ;
     RECT  80.976 41.749 81.48 41.795 ;
     RECT  56.4 41.459 57.048 41.843 ;
     RECT  21.408 27.491 21.432 41.893 ;
     RECT  21.408 41.893 21.576 41.939 ;
     RECT  25.92 40.259 29.712 41.939 ;
     RECT  5.856 40.933 8.856 42.035 ;
     RECT  13.2 41.269 13.704 42.179 ;
     RECT  44.976 41.173 45.912 42.181 ;
     RECT  69.312 40.549 69.528 42.277 ;
     RECT  56.4 41.843 57 42.323 ;
     RECT  69.312 42.277 69.672 42.371 ;
     RECT  42.384 40.789 42.408 42.419 ;
     RECT  48.912 40.645 54.312 42.419 ;
     RECT  66.72 41.749 67.512 42.419 ;
     RECT  18.288 38.389 18.912 42.421 ;
     RECT  44.976 42.181 46.2 42.421 ;
     RECT  56.4 42.323 56.856 42.421 ;
     RECT  56.304 42.421 56.856 42.563 ;
     RECT  5.856 42.035 6.408 42.803 ;
     RECT  44.976 42.421 46.68 42.803 ;
     RECT  65.952 42.709 65.976 42.851 ;
     RECT  82.224 42.181 82.248 42.851 ;
     RECT  16.992 39.877 17.016 43.043 ;
     RECT  2.4 41.699 2.712 43.045 ;
     RECT  4.176 40.741 4.2 43.045 ;
     RECT  69.504 42.371 69.672 43.045 ;
     RECT  69.504 43.045 69.96 43.139 ;
     RECT  69.6 43.139 69.96 43.187 ;
     RECT  61.8 38.531 62.952 43.237 ;
     RECT  69.6 43.187 69.624 43.283 ;
     RECT  40.2 41.557 40.92 43.331 ;
     RECT  61.392 43.237 62.952 43.333 ;
     RECT  18.288 42.421 19.848 43.525 ;
     RECT  21.552 41.939 21.576 43.525 ;
     RECT  2.4 43.045 4.2 43.619 ;
     RECT  56.304 42.563 56.808 43.619 ;
     RECT  80.976 41.795 81 43.765 ;
     RECT  5.856 42.803 5.88 43.811 ;
     RECT  80.4 43.765 81 43.811 ;
     RECT  7.392 42.035 8.856 43.861 ;
     RECT  18.288 43.525 21.576 43.907 ;
     RECT  49.008 42.419 54.312 43.907 ;
     RECT  28.704 41.939 29.712 43.955 ;
     RECT  13.2 42.179 13.608 44.053 ;
     RECT  25.92 41.939 27.72 44.245 ;
     RECT  7.248 43.861 8.856 44.339 ;
     RECT  45.6 42.803 46.68 44.437 ;
     RECT  3.84 43.619 4.2 44.483 ;
     RECT  61.392 43.333 63.864 44.483 ;
     RECT  71.856 41.557 73.56 44.483 ;
     RECT  80.4 43.811 80.424 44.483 ;
     RECT  24 41.459 24.312 44.485 ;
     RECT  25.92 44.245 27.816 44.485 ;
     RECT  39.024 41.605 39.048 44.629 ;
     RECT  40.2 43.331 40.512 44.629 ;
     RECT  24 44.485 27.816 44.723 ;
     RECT  49.008 43.907 52.488 44.869 ;
     RECT  21.456 43.907 21.48 44.917 ;
     RECT  67.2 42.419 67.512 44.965 ;
     RECT  25.92 44.723 27.816 45.059 ;
     RECT  34.656 37.957 36.552 45.155 ;
     RECT  11.424 44.053 11.448 45.157 ;
     RECT  21.456 44.917 22.152 45.157 ;
     RECT  29.184 43.955 29.712 45.157 ;
     RECT  38.448 44.629 39.048 45.397 ;
     RECT  53.616 43.907 54.312 45.445 ;
     RECT  10.224 41.989 10.248 45.493 ;
     RECT  11.424 45.157 11.544 45.493 ;
     RECT  40.2 44.629 40.968 45.493 ;
     RECT  38.4 45.397 39.048 45.539 ;
     RECT  48.432 44.869 52.488 45.539 ;
     RECT  71.856 44.483 72.912 45.541 ;
     RECT  21.456 45.157 22.824 45.587 ;
     RECT  21.456 45.587 22.728 45.683 ;
     RECT  71.856 45.541 73.512 45.685 ;
     RECT  10.224 45.493 11.544 45.731 ;
     RECT  53.616 45.445 54.84 45.731 ;
     RECT  40.2 45.493 41.064 45.779 ;
     RECT  71.856 45.685 73.896 45.875 ;
     RECT  24 44.723 24.552 45.923 ;
     RECT  38.448 45.539 39.048 45.973 ;
     RECT  40.2 45.779 40.512 45.973 ;
     RECT  71.856 45.875 73.512 46.019 ;
     RECT  61.8 44.483 63.864 46.163 ;
     RECT  61.8 46.163 63.048 46.165 ;
     RECT  18.288 43.907 19.848 46.261 ;
     RECT  21.456 45.683 21.48 46.261 ;
     RECT  18.288 46.261 21.48 46.309 ;
     RECT  10.224 45.731 10.248 46.355 ;
     RECT  44.448 44.437 46.68 46.405 ;
     RECT  18.24 46.309 21.48 46.547 ;
     RECT  34.8 45.155 36.552 46.549 ;
     RECT  44.016 46.405 46.68 46.595 ;
     RECT  48.576 45.539 52.488 46.597 ;
     RECT  18.288 46.547 21.48 46.693 ;
     RECT  54.672 45.731 54.84 46.693 ;
     RECT  61.68 46.165 63.048 46.787 ;
     RECT  34.56 46.549 36.552 46.789 ;
     RECT  18.288 46.693 22.2 46.837 ;
     RECT  34.224 46.789 36.552 46.837 ;
     RECT  67.2 44.965 67.608 46.883 ;
     RECT  32.4 45.157 32.424 46.931 ;
     RECT  47.76 46.597 52.488 46.931 ;
     RECT  69.072 46.789 69.096 46.931 ;
     RECT  71.856 46.019 73.032 46.931 ;
     RECT  38.448 45.973 40.512 46.933 ;
     RECT  18.288 46.837 22.632 47.027 ;
     RECT  44.928 46.595 46.68 47.029 ;
     RECT  47.76 46.931 47.784 47.029 ;
     RECT  7.392 44.339 8.856 47.077 ;
     RECT  22.176 47.027 22.632 47.123 ;
     RECT  78 36.515 78.312 47.125 ;
     RECT  18.288 47.027 21.096 47.171 ;
     RECT  38.448 46.933 41.064 47.171 ;
     RECT  56.4 43.619 56.808 47.269 ;
     RECT  75.84 46.069 75.864 47.269 ;
     RECT  11.52 45.731 11.544 47.315 ;
     RECT  53.616 45.731 53.64 47.317 ;
     RECT  54.672 46.693 55.272 47.317 ;
     RECT  38.448 47.171 40.512 47.363 ;
     RECT  34.224 46.837 36.936 47.413 ;
     RECT  53.616 47.317 55.272 47.461 ;
     RECT  44.928 47.029 47.784 47.507 ;
     RECT  18.288 47.171 20.76 47.555 ;
     RECT  75.456 47.269 75.864 47.555 ;
     RECT  45.024 47.507 47.736 47.747 ;
     RECT  64.32 46.357 64.344 47.747 ;
     RECT  24 45.923 24.312 47.749 ;
     RECT  25.92 45.059 27.72 47.749 ;
     RECT  48.768 46.931 52.488 47.795 ;
     RECT  45.6 47.747 47.736 47.843 ;
     RECT  59.856 45.685 59.88 47.843 ;
     RECT  34.08 47.413 36.936 47.845 ;
     RECT  38.448 47.363 39.048 47.845 ;
     RECT  53.568 47.461 55.272 47.891 ;
     RECT  61.8 46.787 63.048 47.939 ;
     RECT  31.008 47.701 31.032 48.133 ;
     RECT  32.112 47.125 32.136 48.133 ;
     RECT  55.248 47.891 55.272 48.229 ;
     RECT  56.4 47.269 57.624 48.229 ;
     RECT  77.904 47.125 78.312 48.229 ;
     RECT  77.472 48.229 78.312 48.277 ;
     RECT  31.008 48.133 32.136 48.325 ;
     RECT  13.2 44.053 13.656 48.373 ;
     RECT  22.176 47.123 22.2 48.421 ;
     RECT  29.088 45.157 29.712 48.421 ;
     RECT  31.008 48.325 32.472 48.421 ;
     RECT  49.008 47.795 52.488 48.421 ;
     RECT  53.568 47.891 54.216 48.421 ;
     RECT  64.416 48.325 64.44 48.421 ;
     RECT  7.392 47.077 9.624 48.467 ;
     RECT  49.008 48.421 54.216 48.611 ;
     RECT  61.8 47.939 62.112 48.661 ;
     RECT  83.4 31.859 83.712 48.805 ;
     RECT  18.288 47.555 19.848 48.853 ;
     RECT  24 47.749 27.72 48.899 ;
     RECT  70.272 46.357 70.296 48.899 ;
     RECT  21.888 48.421 22.2 48.901 ;
     RECT  71.856 46.931 72.912 48.947 ;
     RECT  5.328 48.421 5.352 48.995 ;
     RECT  20.928 48.901 22.2 48.995 ;
     RECT  80.928 48.421 80.952 48.995 ;
     RECT  29.088 48.421 32.472 48.997 ;
     RECT  18.288 48.853 19.944 49.043 ;
     RECT  20.928 48.995 20.952 49.043 ;
     RECT  77.472 48.277 79.224 49.091 ;
     RECT  13.2 48.373 14.616 49.139 ;
     RECT  28.992 48.997 32.472 49.139 ;
     RECT  49.008 48.611 53.832 49.139 ;
     RECT  55.248 48.229 57.624 49.187 ;
     RECT  75.456 47.555 75.48 49.235 ;
     RECT  22.176 48.995 22.2 49.331 ;
     RECT  60.864 48.661 62.112 49.333 ;
     RECT  55.248 49.187 55.272 49.381 ;
     RECT  60.144 49.333 62.112 49.429 ;
     RECT  29.136 49.139 32.472 49.475 ;
     RECT  47.712 47.843 47.736 49.477 ;
     RECT  49.008 49.139 52.488 49.477 ;
     RECT  60.144 49.429 63 49.571 ;
     RECT  65.52 48.805 65.544 49.667 ;
     RECT  60.864 49.571 62.112 49.763 ;
     RECT  6.096 48.997 6.12 49.813 ;
     RECT  6.096 49.813 6.36 49.859 ;
     RECT  67.2 46.883 67.512 49.861 ;
     RECT  11.472 48.949 11.496 49.907 ;
     RECT  72.336 48.947 72.912 50.005 ;
     RECT  43.056 48.181 43.08 50.195 ;
     RECT  4.176 44.483 4.2 50.245 ;
     RECT  34.08 47.845 39.048 50.389 ;
     RECT  40.2 47.363 40.512 50.389 ;
     RECT  34.08 50.389 40.512 50.437 ;
     RECT  41.616 49.237 41.64 50.437 ;
     RECT  72.336 50.005 73.512 50.437 ;
     RECT  56.304 49.187 57.624 50.483 ;
     RECT  34.08 50.437 41.64 50.533 ;
     RECT  64.416 48.421 64.488 50.533 ;
     RECT  13.2 49.139 13.656 50.581 ;
     RECT  67.2 49.861 67.848 50.581 ;
     RECT  13.104 50.581 13.656 50.627 ;
     RECT  17.136 48.901 17.16 50.771 ;
     RECT  45.6 47.843 46.728 50.773 ;
     RECT  47.712 49.477 52.488 50.773 ;
     RECT  34.08 50.533 42.024 50.819 ;
     RECT  64.416 50.533 64.968 50.819 ;
     RECT  41.616 50.819 42.024 51.059 ;
     RECT  2.4 43.619 2.712 51.109 ;
     RECT  4.176 50.245 4.296 51.109 ;
     RECT  18.288 49.043 19.848 51.157 ;
     RECT  63.312 50.869 63.336 51.251 ;
     RECT  45.6 50.773 52.488 51.253 ;
     RECT  53.568 49.139 53.832 51.253 ;
     RECT  77.904 49.091 79.224 51.347 ;
     RECT  56.4 50.483 57.624 51.395 ;
     RECT  2.4 51.109 4.296 51.539 ;
     RECT  13.104 50.627 13.608 51.541 ;
     RECT  61.8 49.763 62.112 51.541 ;
     RECT  30.96 49.475 32.472 51.589 ;
     RECT  60.144 51.541 62.112 51.589 ;
     RECT  45.6 51.253 53.832 51.635 ;
     RECT  67.2 50.581 68.232 51.635 ;
     RECT  83.136 48.805 83.712 51.635 ;
     RECT  29.136 49.475 29.712 51.637 ;
     RECT  49.008 51.635 53.832 51.685 ;
     RECT  54.816 49.381 55.272 51.685 ;
     RECT  56.4 51.395 57.384 51.733 ;
     RECT  59.952 51.589 62.112 51.779 ;
     RECT  29.088 51.637 29.712 51.781 ;
     RECT  30.96 51.589 33.192 51.781 ;
     RECT  34.224 50.819 40.512 51.781 ;
     RECT  49.008 51.685 55.272 51.827 ;
     RECT  30.96 51.781 40.512 51.875 ;
     RECT  77.904 51.347 78.312 51.877 ;
     RECT  33.888 51.875 40.512 51.923 ;
     RECT  41.616 51.059 41.64 51.923 ;
     RECT  45.6 51.635 47.928 51.923 ;
     RECT  64.944 50.819 64.968 51.923 ;
     RECT  29.088 51.781 29.832 51.971 ;
     RECT  7.392 48.467 9 52.021 ;
     RECT  11.136 50.149 11.16 52.163 ;
     RECT  6.336 49.859 6.36 52.211 ;
     RECT  77.472 51.877 78.312 52.213 ;
     RECT  12.528 51.541 13.608 52.259 ;
     RECT  24 48.899 25.032 52.309 ;
     RECT  30.96 51.875 32.472 52.451 ;
     RECT  18.288 51.157 19.896 52.549 ;
     RECT  21.024 51.301 21.048 52.549 ;
     RECT  49.056 51.827 55.272 52.549 ;
     RECT  56.256 51.733 57.384 52.549 ;
     RECT  60.432 51.779 62.112 52.643 ;
     RECT  70.704 51.253 70.728 52.643 ;
     RECT  34.224 51.923 40.512 52.645 ;
     RECT  18.288 52.549 21.048 52.691 ;
     RECT  24 52.309 25.272 52.693 ;
     RECT  26.64 48.899 27.72 52.693 ;
     RECT  34.224 52.645 41.112 52.787 ;
     RECT  43.776 51.589 43.8 52.883 ;
     RECT  24 52.693 27.72 52.885 ;
     RECT  29.088 51.971 29.712 52.885 ;
     RECT  64.992 52.789 65.016 52.931 ;
     RECT  45.6 51.923 46.728 53.029 ;
     RECT  47.712 51.923 47.928 53.029 ;
     RECT  7.392 52.021 9.864 53.075 ;
     RECT  42.816 52.933 42.84 53.075 ;
     RECT  30.96 52.451 32.136 53.123 ;
     RECT  34.224 52.787 41.064 53.171 ;
     RECT  67.2 51.635 67.752 53.173 ;
     RECT  12.528 52.259 13.512 53.267 ;
     RECT  45.6 53.029 47.928 53.363 ;
     RECT  49.056 52.549 57.384 53.411 ;
     RECT  18.288 52.691 20.568 53.509 ;
     RECT  24 52.885 29.712 53.603 ;
     RECT  45.6 53.363 46.728 53.603 ;
     RECT  47.712 53.363 47.928 53.603 ;
     RECT  72 50.437 73.512 53.603 ;
     RECT  76.8 52.213 78.312 53.603 ;
     RECT  72 53.603 72.912 53.651 ;
     RECT  17.52 53.509 20.568 53.843 ;
     RECT  34.224 53.171 40.512 53.843 ;
     RECT  64.416 52.981 64.44 54.035 ;
     RECT  24 53.603 25.272 54.085 ;
     RECT  32.112 53.123 32.136 54.085 ;
     RECT  60.432 52.643 60.456 54.085 ;
     RECT  61.8 52.643 62.112 54.085 ;
     RECT  7.392 53.075 8.856 54.133 ;
     RECT  13.104 53.267 13.512 54.133 ;
     RECT  15.072 50.917 15.096 54.179 ;
     RECT  32.112 54.085 32.712 54.179 ;
     RECT  55.2 53.411 57.384 54.227 ;
     RECT  56.4 54.227 57.384 54.275 ;
     RECT  36.288 53.843 40.512 54.277 ;
     RECT  17.52 53.843 19.848 54.323 ;
     RECT  60.432 54.085 62.112 54.323 ;
     RECT  9.84 53.075 9.864 54.371 ;
     RECT  67.2 53.173 67.8 54.371 ;
     RECT  36.288 54.277 41.064 54.419 ;
     RECT  81.696 52.981 81.72 54.563 ;
     RECT  70.992 53.557 71.016 54.613 ;
     RECT  42.048 54.085 42.072 54.659 ;
     RECT  18.288 54.323 19.848 54.707 ;
     RECT  6.624 54.133 8.856 54.755 ;
     RECT  30.96 53.123 31.032 54.755 ;
     RECT  77.472 53.603 78.312 54.755 ;
     RECT  13.104 54.133 13.608 54.899 ;
     RECT  23.568 54.085 25.272 54.899 ;
     RECT  63.648 54.661 63.672 54.899 ;
     RECT  60.72 54.323 62.112 55.139 ;
     RECT  45.6 53.603 45.912 55.189 ;
     RECT  7.68 54.755 8.856 55.237 ;
     RECT  32.688 54.179 32.712 55.237 ;
     RECT  34.224 53.843 35.256 55.237 ;
     RECT  24 54.899 25.272 55.285 ;
     RECT  26.448 53.603 29.712 55.285 ;
     RECT  45.024 55.189 45.912 55.331 ;
     RECT  70.992 54.613 71.256 55.379 ;
     RECT  32.688 55.237 35.256 55.427 ;
     RECT  55.2 54.227 55.272 55.477 ;
     RECT  33.072 55.427 35.256 55.523 ;
     RECT  6.624 54.755 6.648 55.717 ;
     RECT  7.68 55.237 9.72 55.717 ;
     RECT  36.288 54.419 40.512 55.811 ;
     RECT  49.056 53.411 53.784 55.811 ;
     RECT  54.816 55.477 55.272 55.813 ;
     RECT  4.272 51.539 4.296 55.907 ;
     RECT  6.624 55.717 9.72 55.907 ;
     RECT  71.232 55.379 71.256 55.907 ;
     RECT  38.496 55.811 40.512 55.909 ;
     RECT  78 54.755 78.312 55.957 ;
     RECT  47.712 53.603 47.88 56.005 ;
     RECT  18.48 54.707 19.848 56.099 ;
     RECT  59.424 55.957 59.448 56.099 ;
     RECT  53.376 55.811 53.784 56.197 ;
     RECT  54.768 55.813 55.272 56.197 ;
     RECT  65.52 55.813 65.544 56.197 ;
     RECT  33.456 55.523 35.256 56.293 ;
     RECT  36.288 55.811 37.512 56.293 ;
     RECT  47.184 56.005 47.88 56.339 ;
     RECT  49.056 55.811 52.056 56.387 ;
     RECT  61.248 55.139 62.112 56.389 ;
     RECT  67.2 54.371 67.512 56.389 ;
     RECT  24 55.285 29.712 56.483 ;
     RECT  82.032 54.709 82.056 56.483 ;
     RECT  38.496 55.909 40.632 56.533 ;
     RECT  28.896 56.483 29.712 56.723 ;
     RECT  77.28 55.957 78.312 56.723 ;
     RECT  49.056 56.387 51.816 56.819 ;
     RECT  49.056 56.819 51.312 56.821 ;
     RECT  33.456 56.293 37.512 56.867 ;
     RECT  43.872 56.821 43.896 56.869 ;
     RECT  45.6 55.331 45.912 56.869 ;
     RECT  68.928 56.389 68.952 56.869 ;
     RECT  68.688 56.869 68.952 56.915 ;
     RECT  24 56.483 27.72 56.917 ;
     RECT  34.704 56.867 37.512 56.917 ;
     RECT  38.496 56.533 40.872 56.917 ;
     RECT  49.008 56.821 51.312 56.963 ;
     RECT  47.712 56.339 47.88 56.965 ;
     RECT  4.8 55.909 4.824 57.059 ;
     RECT  6.624 55.907 8.856 57.059 ;
     RECT  22.8 56.917 27.72 57.059 ;
     RECT  79.392 55.861 79.416 57.059 ;
     RECT  34.704 56.917 40.872 57.109 ;
     RECT  6.96 57.059 8.856 57.157 ;
     RECT  60.96 56.389 62.112 57.203 ;
     RECT  23.184 57.059 27.72 57.299 ;
     RECT  34.704 57.109 41.208 57.299 ;
     RECT  43.872 56.869 45.912 57.299 ;
     RECT  23.184 57.299 25.272 57.347 ;
     RECT  34.704 57.299 35.304 57.395 ;
     RECT  6.96 57.157 8.904 57.443 ;
     RECT  53.376 56.197 55.272 57.445 ;
     RECT  56.4 54.275 56.712 57.445 ;
     RECT  47.712 56.965 48.504 57.635 ;
     RECT  24 57.347 25.272 57.683 ;
     RECT  26.448 57.299 27.72 57.683 ;
     RECT  29.136 56.723 29.712 57.781 ;
     RECT  67.056 56.389 67.512 57.829 ;
     RECT  49.536 56.963 51.312 57.875 ;
     RECT  65.04 56.197 65.544 57.875 ;
     RECT  28.752 57.781 29.712 57.923 ;
     RECT  58.608 56.197 58.632 58.117 ;
     RECT  53.376 57.445 56.712 58.211 ;
     RECT  34.704 57.395 35.256 58.213 ;
     RECT  48.384 57.635 48.504 58.307 ;
     RECT  36.288 57.299 41.208 58.309 ;
     RECT  68.688 56.915 68.712 58.355 ;
     RECT  34.512 58.213 35.256 58.403 ;
     RECT  33.456 56.867 33.48 58.405 ;
     RECT  36.288 58.309 41.4 58.451 ;
     RECT  36.288 58.451 41.016 58.499 ;
     RECT  34.608 58.403 35.256 58.547 ;
     RECT  21.648 58.117 21.672 58.643 ;
     RECT  66.72 57.829 67.512 58.645 ;
     RECT  33.072 58.405 33.48 58.691 ;
     RECT  13.104 54.899 13.512 58.693 ;
     RECT  26.496 57.683 27.72 58.741 ;
     RECT  38.496 58.499 41.016 58.787 ;
     RECT  34.704 58.547 35.256 58.837 ;
     RECT  36.288 58.499 37.512 58.837 ;
     RECT  6.96 57.443 8.856 59.029 ;
     RECT  2.4 51.539 2.712 59.221 ;
     RECT  5.424 58.405 5.448 59.221 ;
     RECT  16.512 58.549 16.536 59.221 ;
     RECT  53.376 58.211 55.272 59.221 ;
     RECT  56.4 58.211 56.712 59.221 ;
     RECT  81.504 57.637 81.528 59.221 ;
     RECT  10.8 58.645 10.824 59.267 ;
     RECT  81.504 59.221 81.624 59.267 ;
     RECT  26.208 58.741 27.72 59.315 ;
     RECT  61.248 57.203 62.112 59.315 ;
     RECT  66.48 58.645 67.512 59.315 ;
     RECT  13.104 58.693 14.472 59.363 ;
     RECT  63.408 58.405 63.432 59.459 ;
     RECT  16.512 59.221 17.16 59.507 ;
     RECT  42.432 59.509 42.456 59.651 ;
     RECT  16.512 59.507 16.536 59.699 ;
     RECT  26.496 59.315 27.72 59.747 ;
     RECT  65.04 57.875 65.064 59.749 ;
     RECT  44.688 57.299 45.912 59.797 ;
     RECT  53.376 59.221 56.712 59.797 ;
     RECT  52.704 59.797 56.712 59.843 ;
     RECT  40.2 58.787 41.016 59.845 ;
     RECT  2.4 59.221 3.672 59.891 ;
     RECT  33.456 58.691 33.48 59.941 ;
     RECT  34.704 58.837 37.512 59.941 ;
     RECT  20.976 59.125 21 59.989 ;
     RECT  72.432 53.651 72.912 60.085 ;
     RECT  48.48 58.307 48.504 60.227 ;
     RECT  38.496 58.787 39.048 60.325 ;
     RECT  40.2 59.845 41.304 60.325 ;
     RECT  58.272 58.117 58.632 60.373 ;
     RECT  33.456 59.941 37.512 60.419 ;
     RECT  6.912 59.029 8.856 60.421 ;
     RECT  36.384 60.419 37.512 60.421 ;
     RECT  38.496 60.325 41.304 60.421 ;
     RECT  36.384 60.421 41.304 60.467 ;
     RECT  65.04 59.749 65.592 60.467 ;
     RECT  43.632 57.493 43.656 60.563 ;
     RECT  33.456 60.419 35.352 60.613 ;
     RECT  5.424 59.221 5.592 60.661 ;
     RECT  33.216 60.613 35.352 60.709 ;
     RECT  13.104 59.363 14.28 60.757 ;
     RECT  47.424 60.661 47.448 60.853 ;
     RECT  5.232 60.661 5.592 60.899 ;
     RECT  36.816 60.467 41.304 60.899 ;
     RECT  47.424 60.853 47.88 60.899 ;
     RECT  33.072 60.709 35.352 60.901 ;
     RECT  13.104 60.757 14.808 60.947 ;
     RECT  76.944 60.805 76.968 60.947 ;
     RECT  61.296 59.315 62.112 60.949 ;
     RECT  30.96 54.755 30.984 60.997 ;
     RECT  32.352 60.901 35.352 60.997 ;
     RECT  30.96 60.997 35.352 61.043 ;
     RECT  74.784 59.797 74.808 61.043 ;
     RECT  44.688 59.797 46.344 61.045 ;
     RECT  78 56.723 78.312 61.141 ;
     RECT  80.16 60.949 80.184 61.141 ;
     RECT  39.792 60.899 41.304 61.235 ;
     RECT  47.856 60.899 47.88 61.283 ;
     RECT  20.976 59.989 21.24 61.331 ;
     RECT  31.392 61.043 35.352 61.523 ;
     RECT  5.568 60.899 5.592 61.525 ;
     RECT  6.864 60.421 8.856 61.525 ;
     RECT  61.296 60.949 62.904 61.571 ;
     RECT  66.096 60.997 66.12 61.619 ;
     RECT  26.64 59.747 27.72 61.669 ;
     RECT  31.392 61.523 33.48 61.715 ;
     RECT  72.432 60.085 73.032 61.763 ;
     RECT  61.296 61.571 62.112 61.765 ;
     RECT  78 61.141 80.184 61.765 ;
     RECT  43.776 61.045 46.344 61.907 ;
     RECT  49.536 57.875 49.56 61.909 ;
     RECT  39.792 61.235 41.064 61.955 ;
     RECT  26.64 61.669 27.912 62.003 ;
     RECT  39.792 61.955 40.512 62.003 ;
     RECT  48.624 61.909 49.56 62.051 ;
     RECT  57.888 60.373 58.632 62.101 ;
     RECT  21.216 61.331 21.24 62.147 ;
     RECT  13.104 60.947 14.232 62.195 ;
     RECT  31.392 61.715 32.376 62.195 ;
     RECT  81.6 59.267 81.624 62.195 ;
     RECT  15.888 60.997 15.912 62.243 ;
     RECT  51 57.875 51.312 62.341 ;
     RECT  52.704 59.843 55.272 62.341 ;
     RECT  5.568 61.525 8.856 62.435 ;
     RECT  34.8 61.523 35.352 62.629 ;
     RECT  36.816 60.899 38.52 62.629 ;
     RECT  51 62.341 55.272 62.675 ;
     RECT  57.888 62.101 59.592 62.675 ;
     RECT  13.2 62.195 14.232 62.677 ;
     RECT  32.352 62.195 32.376 62.723 ;
     RECT  44.112 61.907 46.344 62.723 ;
     RECT  52.752 62.675 55.272 62.773 ;
     RECT  56.4 59.843 56.712 62.773 ;
     RECT  77.136 61.765 80.184 62.915 ;
     RECT  78 62.915 80.184 62.963 ;
     RECT  34.704 62.629 35.352 63.011 ;
     RECT  57.888 62.675 58.632 63.011 ;
     RECT  24 57.683 25.032 63.013 ;
     RECT  23.904 63.013 25.032 63.059 ;
     RECT  52.752 62.773 56.712 63.059 ;
     RECT  23.904 63.059 24.456 63.155 ;
     RECT  40.2 62.003 40.512 63.205 ;
     RECT  63.888 61.765 63.912 63.251 ;
     RECT  13.2 62.677 14.808 63.299 ;
     RECT  45.264 62.723 46.344 63.299 ;
     RECT  34.8 63.011 35.352 63.347 ;
     RECT  45.264 63.299 45.912 63.347 ;
     RECT  61.008 61.765 62.112 63.347 ;
     RECT  33.456 61.715 33.48 63.397 ;
     RECT  75.408 62.677 75.432 63.539 ;
     RECT  49.536 62.051 49.56 63.541 ;
     RECT  36.48 62.629 38.52 63.685 ;
     RECT  49.008 63.541 49.56 63.731 ;
     RECT  65.04 60.467 65.064 63.733 ;
     RECT  5.568 62.435 5.592 63.781 ;
     RECT  13.2 63.299 13.944 63.781 ;
     RECT  18.6 56.099 19.848 63.781 ;
     RECT  69.984 58.645 70.008 63.781 ;
     RECT  6.864 62.435 8.856 63.829 ;
     RECT  72.432 61.763 72.912 63.875 ;
     RECT  52.752 63.059 55.272 63.923 ;
     RECT  48 63.205 48.024 64.067 ;
     RECT  51 62.675 51.768 64.165 ;
     RECT  52.752 63.923 54.84 64.165 ;
     RECT  57.888 63.011 57.912 64.259 ;
     RECT  51 64.165 54.84 64.307 ;
     RECT  61.8 63.347 62.112 64.309 ;
     RECT  18.6 63.781 20.568 64.357 ;
     RECT  34.8 63.347 35.208 64.357 ;
     RECT  44.112 62.723 44.136 64.357 ;
     RECT  36.384 63.685 38.52 64.403 ;
     RECT  10.08 61.765 10.104 64.405 ;
     RECT  15.792 63.781 15.816 64.595 ;
     RECT  6.768 63.829 8.856 64.643 ;
     RECT  36.816 64.403 38.52 64.645 ;
     RECT  57.936 64.309 57.96 64.645 ;
     RECT  29.136 57.923 29.712 64.693 ;
     RECT  31.488 64.357 31.512 64.693 ;
     RECT  6.768 64.643 8.712 64.787 ;
     RECT  64.464 63.733 65.064 64.787 ;
     RECT  83.4 51.635 83.712 64.837 ;
     RECT  52.752 64.307 54.84 64.933 ;
     RECT  33.024 63.397 33.48 64.979 ;
     RECT  44.112 64.357 44.184 65.027 ;
     RECT  61.248 64.309 62.112 65.027 ;
     RECT  29.136 64.693 31.512 65.075 ;
     RECT  34.8 64.357 35.352 65.075 ;
     RECT  45.6 63.347 45.912 65.077 ;
     RECT  12.576 63.781 13.944 65.171 ;
     RECT  51 64.307 51.672 65.173 ;
     RECT  36.816 64.645 39.144 65.219 ;
     RECT  50.88 65.173 51.672 65.365 ;
     RECT  57.936 64.645 58.056 65.365 ;
     RECT  50.64 65.365 51.672 65.509 ;
     RECT  52.752 64.933 54.888 65.509 ;
     RECT  50.64 65.509 54.888 65.555 ;
     RECT  38.496 65.219 39.144 65.603 ;
     RECT  18.048 64.357 20.568 65.605 ;
     RECT  29.136 65.075 30.696 65.651 ;
     RECT  44.16 65.027 44.184 65.651 ;
     RECT  82.656 64.837 83.712 65.651 ;
     RECT  45.312 65.077 45.912 65.653 ;
     RECT  17.952 65.605 20.568 65.747 ;
     RECT  24 63.155 24.456 65.747 ;
     RECT  40.2 63.205 41.208 65.891 ;
     RECT  33.456 64.979 33.48 65.941 ;
     RECT  33.456 65.941 33.816 66.083 ;
     RECT  65.04 64.787 65.064 66.133 ;
     RECT  69.984 63.781 70.104 66.133 ;
     RECT  18.6 65.747 20.568 66.179 ;
     RECT  69.792 66.133 70.104 66.179 ;
     RECT  34.8 65.075 35.304 66.229 ;
     RECT  36.816 65.219 36.84 66.229 ;
     RECT  50.736 65.555 54.888 66.277 ;
     RECT  56.4 63.059 56.712 66.277 ;
     RECT  57.84 65.365 58.056 66.277 ;
     RECT  64.512 66.133 65.064 66.323 ;
     RECT  49.536 63.731 49.56 66.325 ;
     RECT  61.8 65.027 62.112 66.325 ;
     RECT  50.736 66.277 55.176 66.419 ;
     RECT  56.4 66.277 58.056 66.419 ;
     RECT  50.736 66.419 54.792 66.467 ;
     RECT  61.68 66.325 62.112 66.467 ;
     RECT  75.216 64.309 75.24 66.467 ;
     RECT  48.768 66.325 49.56 66.563 ;
     RECT  34.8 66.229 36.84 66.611 ;
     RECT  63.792 66.421 63.816 66.611 ;
     RECT  24 65.747 24.408 66.613 ;
     RECT  33.456 66.083 33.48 66.661 ;
     RECT  45.216 65.653 45.912 66.661 ;
     RECT  50.832 66.467 54.792 66.707 ;
     RECT  60.72 66.469 60.744 66.707 ;
     RECT  6.864 64.787 8.712 66.755 ;
     RECT  9.888 64.405 10.104 66.755 ;
     RECT  51 66.707 54.792 66.755 ;
     RECT  57.936 66.419 58.056 66.755 ;
     RECT  49.44 66.563 49.56 66.757 ;
     RECT  49.44 66.757 49.656 66.995 ;
     RECT  51 66.755 54.744 67.043 ;
     RECT  49.44 66.995 49.56 67.187 ;
     RECT  34.8 66.611 35.304 67.283 ;
     RECT  51 67.043 54.696 67.283 ;
     RECT  78 62.963 79.272 67.283 ;
     RECT  13.2 65.171 13.944 67.285 ;
     RECT  32.592 66.661 33.48 67.333 ;
     RECT  65.04 66.323 65.064 67.333 ;
     RECT  44.448 66.661 45.912 67.379 ;
     RECT  61.8 66.467 62.112 67.525 ;
     RECT  56.4 66.419 56.904 67.573 ;
     RECT  64.992 67.333 65.064 67.619 ;
     RECT  56.4 67.573 57 67.715 ;
     RECT  60.96 67.525 62.112 67.715 ;
     RECT  72.6 63.875 72.912 67.765 ;
     RECT  29.136 65.651 29.712 67.811 ;
     RECT  38.496 65.603 39.048 67.859 ;
     RECT  36.336 66.611 36.84 67.907 ;
     RECT  69.792 66.179 69.816 67.957 ;
     RECT  7.584 66.755 8.712 68.003 ;
     RECT  18.6 66.179 19.848 68.195 ;
     RECT  12.096 67.765 12.12 68.243 ;
     RECT  82.32 67.237 82.344 68.339 ;
     RECT  7.584 68.003 8.232 68.341 ;
     RECT  51 67.283 54.312 68.341 ;
     RECT  50.688 68.341 54.312 68.387 ;
     RECT  23.856 66.613 24.408 68.435 ;
     RECT  68.832 67.957 69.816 68.533 ;
     RECT  56.4 67.715 56.952 68.579 ;
     RECT  68.736 68.533 69.816 68.579 ;
     RECT  44.448 67.379 44.472 68.629 ;
     RECT  45.6 67.379 45.912 68.629 ;
     RECT  26.64 62.003 27.72 68.773 ;
     RECT  29.4 67.811 29.712 68.773 ;
     RECT  61.68 67.715 62.112 68.773 ;
     RECT  32.112 67.333 33.48 68.869 ;
     RECT  31.92 68.869 33.48 68.915 ;
     RECT  44.448 68.629 45.912 68.915 ;
     RECT  72.6 67.765 73.464 68.915 ;
     RECT  67.2 59.315 67.512 68.917 ;
     RECT  56.4 68.579 56.904 68.963 ;
     RECT  5.04 63.781 5.592 68.965 ;
     RECT  26.64 68.773 29.712 68.965 ;
     RECT  69.792 68.579 69.816 68.965 ;
     RECT  37.2 67.957 37.224 69.011 ;
     RECT  69.792 68.965 70.104 69.011 ;
     RECT  49.536 67.187 49.56 69.013 ;
     RECT  59.52 67.669 59.544 69.155 ;
     RECT  68.736 68.579 68.76 69.203 ;
     RECT  60.912 68.773 62.112 69.205 ;
     RECT  49.056 69.013 49.56 69.251 ;
     RECT  18.6 68.195 19.656 69.301 ;
     RECT  60.816 69.205 62.112 69.301 ;
     RECT  4.8 68.965 5.592 69.349 ;
     RECT  15.888 67.765 15.912 69.493 ;
     RECT  20.976 67.669 21 69.493 ;
     RECT  4.512 69.349 5.592 69.587 ;
     RECT  7.536 68.341 8.232 69.587 ;
     RECT  26.64 68.965 29.832 69.731 ;
     RECT  33.024 68.915 33.48 69.731 ;
     RECT  45.024 68.915 45.912 69.827 ;
     RECT  50.688 68.387 51.672 69.827 ;
     RECT  39.024 67.859 39.048 69.925 ;
     RECT  72.6 68.915 72.912 69.973 ;
     RECT  78 67.283 78.312 70.021 ;
     RECT  15.888 69.493 16.44 70.117 ;
     RECT  4.8 69.587 5.592 70.163 ;
     RECT  15.456 70.117 16.44 70.163 ;
     RECT  31.92 68.915 31.944 70.163 ;
     RECT  67.2 68.917 67.608 70.357 ;
     RECT  33.456 69.731 33.48 70.403 ;
     RECT  65.04 67.619 65.064 70.595 ;
     RECT  24 68.435 24.408 70.597 ;
     RECT  67.2 70.357 67.8 70.645 ;
     RECT  23.904 70.597 24.408 70.691 ;
     RECT  38.784 69.925 39.048 70.787 ;
     RECT  66.432 70.645 67.8 70.787 ;
     RECT  51 69.827 51.672 70.835 ;
     RECT  52.656 68.387 54.312 70.835 ;
     RECT  56.4 68.963 56.808 70.883 ;
     RECT  60.624 69.301 62.112 70.979 ;
     RECT  61.68 70.979 62.112 71.171 ;
     RECT  18.48 69.301 19.656 71.221 ;
     RECT  20.976 69.493 21.672 71.221 ;
     RECT  70.08 69.011 70.104 71.221 ;
     RECT  72.6 69.973 73.176 71.315 ;
     RECT  74.976 69.349 75 71.363 ;
     RECT  15.456 70.163 15.48 71.507 ;
     RECT  26.64 69.731 27.72 71.507 ;
     RECT  18.48 71.221 21.672 71.509 ;
     RECT  31.344 70.693 31.368 71.555 ;
     RECT  17.616 71.509 21.672 71.603 ;
     RECT  10.08 66.755 10.104 71.699 ;
     RECT  78 70.021 78.888 71.747 ;
     RECT  29.4 69.731 29.832 71.797 ;
     RECT  69.504 71.221 70.104 71.891 ;
     RECT  33.552 70.645 33.576 71.989 ;
     RECT  58.032 66.755 58.056 72.035 ;
     RECT  55.152 71.989 55.176 72.133 ;
     RECT  56.4 70.883 56.712 72.133 ;
     RECT  13.2 67.285 14.232 72.179 ;
     RECT  23.904 70.691 24.312 72.179 ;
     RECT  28.896 71.797 29.832 72.179 ;
     RECT  49.536 69.251 49.56 72.179 ;
     RECT  33.552 71.989 33.768 72.229 ;
     RECT  34.8 67.283 35.112 72.229 ;
     RECT  17.616 71.603 21 72.419 ;
     RECT  27.024 71.507 27.72 72.467 ;
     RECT  33.552 72.229 35.112 72.467 ;
     RECT  17.616 72.419 20.568 72.611 ;
     RECT  66.432 70.787 67.512 72.659 ;
     RECT  63.264 69.493 63.288 72.707 ;
     RECT  52.656 70.835 53.592 72.947 ;
     RECT  68.832 72.757 68.856 72.949 ;
     RECT  7.536 69.587 8.112 72.995 ;
     RECT  68.736 72.949 68.856 73.237 ;
     RECT  68.736 73.237 68.904 73.283 ;
     RECT  78 71.747 78.312 73.333 ;
     RECT  43.872 72.901 43.896 73.379 ;
     RECT  70.08 71.891 70.104 73.379 ;
     RECT  28.896 72.179 29.712 73.523 ;
     RECT  67.104 72.659 67.512 73.523 ;
     RECT  17.616 72.611 19.656 73.571 ;
     RECT  18.6 73.571 19.656 73.811 ;
     RECT  52.656 72.947 53.4 73.811 ;
     RECT  15.12 72.325 15.144 74.003 ;
     RECT  24 72.179 24.312 74.101 ;
     RECT  4.8 70.163 4.824 74.147 ;
     RECT  27.36 72.467 27.72 74.147 ;
     RECT  39.024 70.787 39.048 74.147 ;
     RECT  52.656 73.811 53.304 74.339 ;
     RECT  55.152 72.133 56.712 74.339 ;
     RECT  77.568 73.333 78.312 74.339 ;
     RECT  23.04 74.101 24.312 74.437 ;
     RECT  16.656 74.053 16.68 74.579 ;
     RECT  40.2 65.891 40.512 74.581 ;
     RECT  7.8 72.995 8.112 74.629 ;
     RECT  33.744 72.467 35.112 74.723 ;
     RECT  36.768 71.413 36.792 74.723 ;
     RECT  53.28 74.339 53.304 74.723 ;
     RECT  55.152 74.339 55.176 74.723 ;
     RECT  68.88 73.283 68.904 74.723 ;
     RECT  19.92 74.629 19.944 74.819 ;
     RECT  23.04 74.437 24.408 74.867 ;
     RECT  40.2 74.581 41.16 74.867 ;
     RECT  42.144 73.525 42.168 74.867 ;
     RECT  38.784 74.581 38.808 75.059 ;
     RECT  7.68 74.629 8.112 75.251 ;
     RECT  10.224 74.293 10.248 75.299 ;
     RECT  24 74.867 24.408 75.299 ;
     RECT  33.744 74.723 33.768 75.395 ;
     RECT  2.4 59.891 2.712 75.609 ;
     RECT  7.8 75.251 8.112 75.609 ;
     RECT  13.2 72.179 13.512 75.609 ;
     RECT  18.6 73.811 18.912 75.609 ;
     RECT  24 75.299 24.312 75.609 ;
     RECT  29.4 73.523 29.712 75.609 ;
     RECT  34.8 74.723 35.112 75.609 ;
     RECT  40.2 74.867 40.512 75.609 ;
     RECT  45.6 69.827 45.912 75.609 ;
     RECT  51 70.835 51.312 75.609 ;
     RECT  56.4 74.339 56.712 75.609 ;
     RECT  61.8 71.171 62.112 75.609 ;
     RECT  67.2 73.523 67.512 75.609 ;
     RECT  72.6 71.315 72.912 75.609 ;
     RECT  78 74.339 78.312 75.609 ;
     RECT  83.4 65.651 83.712 75.609 ;
     RECT  2.4 75.609 2.52 75.623 ;
     RECT  7.8 75.609 7.92 75.623 ;
     RECT  13.2 75.609 13.32 75.623 ;
     RECT  18.6 75.609 18.72 75.623 ;
     RECT  24 75.609 24.12 75.623 ;
     RECT  29.4 75.609 29.52 75.623 ;
     RECT  34.8 75.609 34.92 75.623 ;
     RECT  40.2 75.609 40.32 75.623 ;
     RECT  45.6 75.609 45.72 75.623 ;
     RECT  51 75.609 51.12 75.623 ;
     RECT  56.4 75.609 56.52 75.623 ;
     RECT  61.8 75.609 61.92 75.623 ;
     RECT  67.2 75.609 67.32 75.623 ;
     RECT  72.6 75.609 72.72 75.623 ;
     RECT  78 75.609 78.12 75.623 ;
     RECT  83.4 75.609 83.52 75.623 ;
     RECT  27.696 74.147 27.72 75.781 ;
     RECT  27.696 75.781 27.816 77.676 ;
     RECT  27.72 77.676 27.792 77.712 ;
     RECT  44.328 2.245 45.6 3.347 ;
     RECT  56.712 3.301 58.128 4.355 ;
     RECT  13.656 3.397 14.832 4.019 ;
     RECT  35.112 3.875 35.208 5.365 ;
     RECT  49.704 3.877 51 4.693 ;
     RECT  17.16 3.925 18.6 4.597 ;
     RECT  58.152 3.925 59.184 4.355 ;
     RECT  34.704 4.067 34.8 5.077 ;
     RECT  2.712 4.117 4.08 5.459 ;
     RECT  46.056 4.117 47.472 4.405 ;
     RECT  56.712 4.355 59.184 5.171 ;
     RECT  46.152 4.405 47.472 5.845 ;
     RECT  47.496 4.453 48.72 6.851 ;
     RECT  51.72 4.547 51.912 4.741 ;
     RECT  17.256 4.597 18.6 5.413 ;
     RECT  51.72 4.741 52.992 6.373 ;
     RECT  48.744 4.787 50.352 6.277 ;
     RECT  72.912 4.789 74.112 6.851 ;
     RECT  61.056 4.931 61.8 6.133 ;
     RECT  29.976 5.029 30.96 6.323 ;
     RECT  56.712 5.171 58.296 5.653 ;
     RECT  24.312 5.219 24.408 6.229 ;
     RECT  17.544 5.413 18.6 6.035 ;
     RECT  11.688 5.509 13.2 6.323 ;
     RECT  56.904 5.653 58.296 5.845 ;
     RECT  65.448 5.701 66.768 6.131 ;
     RECT  46.392 5.845 47.472 6.851 ;
     RECT  56.904 5.845 58.272 6.851 ;
     RECT  17.52 6.035 18.6 7.381 ;
     RECT  8.112 6.085 9.408 7.475 ;
     RECT  60.456 6.133 61.8 6.613 ;
     RECT  24.312 6.229 25.536 8.245 ;
     RECT  78.312 6.229 79.488 6.947 ;
     RECT  48.984 6.277 50.352 6.419 ;
     RECT  12 6.323 13.2 6.805 ;
     RECT  29.712 6.323 30.96 7.957 ;
     RECT  60.696 6.613 61.8 7.957 ;
     RECT  70.728 6.659 71.856 7.475 ;
     RECT  53.016 6.661 54.048 6.707 ;
     RECT  12.024 6.805 13.2 7.237 ;
     RECT  13.512 6.805 14.832 9.061 ;
     RECT  58.296 6.805 59.472 6.851 ;
     RECT  62.112 6.805 63.36 7.955 ;
     RECT  63.384 6.805 64.512 7.955 ;
     RECT  38.136 6.899 38.232 8.293 ;
     RECT  78.312 6.947 78.408 7.429 ;
     RECT  54.072 6.949 55.344 7.909 ;
     RECT  56.712 7.139 56.904 8.437 ;
     RECT  51.312 7.379 52.416 8.195 ;
     RECT  17.208 7.381 18.6 8.003 ;
     RECT  33.624 7.381 34.8 9.155 ;
     RECT  40.512 7.475 40.872 8.821 ;
     RECT  78.312 7.667 78.408 8.917 ;
     RECT  19.704 7.861 21.12 8.867 ;
     RECT  54.312 7.909 55.344 7.957 ;
     RECT  65.448 7.957 66.72 8.051 ;
     RECT  17.808 8.003 18.6 9.061 ;
     RECT  65.208 8.051 66.72 8.099 ;
     RECT  64.92 8.099 66.72 9.013 ;
     RECT  3.432 8.293 4.512 9.683 ;
     RECT  38.808 8.293 40.2 9.779 ;
     RECT  81.288 8.485 82.608 8.531 ;
     RECT  59.472 9.011 60.432 10.261 ;
     RECT  64.92 9.013 66.144 9.059 ;
     RECT  60.456 9.155 61.584 10.211 ;
     RECT  66.168 9.155 67.2 9.731 ;
     RECT  30.984 9.589 32.496 10.355 ;
     RECT  78.312 9.683 78.888 10.789 ;
     RECT  39.984 9.779 40.2 10.693 ;
     RECT  4.536 10.165 5.856 11.941 ;
     RECT  60.456 10.211 61.8 13.285 ;
     RECT  8.112 10.213 9.456 11.411 ;
     RECT  59.112 10.261 60.432 10.883 ;
     RECT  5.88 10.357 6.864 10.883 ;
     RECT  5.88 10.883 7.8 11.845 ;
     RECT  54.744 11.027 55.776 11.459 ;
     RECT  40.968 11.077 42.432 11.365 ;
     RECT  45.912 11.219 46.008 11.221 ;
     RECT  45.912 11.221 47.328 11.747 ;
     RECT  40.968 11.365 42.096 13.189 ;
     RECT  51.312 11.365 52.656 11.509 ;
     RECT  53.16 11.365 54.528 12.517 ;
     RECT  8.112 11.411 9.432 12.709 ;
     RECT  76.176 11.411 76.2 11.845 ;
     RECT  43.272 11.413 44.256 11.555 ;
     RECT  44.28 11.413 45.6 11.555 ;
     RECT  54.744 11.459 55.92 14.245 ;
     RECT  43.272 11.555 45.6 11.557 ;
     RECT  43.272 11.557 45.504 12.565 ;
     RECT  45.912 11.747 46.104 12.421 ;
     RECT  6.408 11.845 7.8 12.563 ;
     RECT  76.056 11.845 76.2 12.517 ;
     RECT  37.032 12.325 38.304 13.237 ;
     RECT  53.496 12.517 54.528 14.533 ;
     RECT  76.056 12.517 77.472 13.621 ;
     RECT  44.328 12.565 45.504 13.093 ;
     RECT  49.968 12.707 50.112 14.149 ;
     RECT  8.112 12.709 9.408 13.045 ;
     RECT  24.312 12.851 25.392 15.685 ;
     RECT  62.112 12.901 63.552 14.963 ;
     RECT  63.576 12.947 63.672 14.101 ;
     RECT  4.536 12.995 5.856 13.043 ;
     RECT  2.712 12.997 4.032 15.061 ;
     RECT  8.112 13.045 9.12 16.595 ;
     RECT  30.984 13.045 32.448 13.283 ;
     RECT  35.112 13.045 36.192 13.525 ;
     RECT  38.328 13.045 39.744 13.717 ;
     RECT  44.472 13.093 45.504 13.859 ;
     RECT  67.512 13.141 68.928 13.427 ;
     RECT  68.952 13.141 69.936 13.427 ;
     RECT  37.032 13.237 38.256 13.475 ;
     RECT  30.984 13.283 31.368 14.245 ;
     RECT  60.648 13.285 61.8 13.429 ;
     RECT  60.432 13.331 60.624 14.147 ;
     RECT  60.744 13.429 61.8 15.443 ;
     RECT  37.032 13.475 38.304 14.531 ;
     RECT  76.056 13.621 77.184 14.867 ;
     RECT  38.376 13.717 39.744 14.005 ;
     RECT  43.272 13.763 44.448 13.859 ;
     RECT  45.12 13.859 45.504 14.053 ;
     RECT  16.584 13.861 17.568 14.915 ;
     RECT  17.592 13.861 18.6 14.915 ;
     RECT  11.784 14.099 13.2 16.885 ;
     RECT  60.432 14.147 60.72 14.389 ;
     RECT  72.48 14.387 72.6 14.773 ;
     RECT  59.256 14.389 60.72 14.485 ;
     RECT  59.64 14.485 60.72 15.443 ;
     RECT  36.36 14.531 38.304 14.869 ;
     RECT  78.888 14.531 79.176 15.205 ;
     RECT  69.96 14.773 71.184 14.917 ;
     RECT  71.208 14.773 72.6 16.259 ;
     RECT  76.056 14.867 76.392 15.491 ;
     RECT  36.36 14.869 38.256 15.299 ;
     RECT  18.48 14.915 18.6 14.917 ;
     RECT  70.104 14.917 71.184 16.213 ;
     RECT  3 15.061 4.032 16.403 ;
     RECT  78.888 15.205 80.256 16.259 ;
     RECT  80.28 15.205 81.264 16.213 ;
     RECT  36.36 15.299 38.304 15.781 ;
     RECT  45.912 15.349 47.376 16.693 ;
     RECT  15.96 15.443 16.2 16.501 ;
     RECT  32.28 15.443 33.096 16.019 ;
     RECT  45.264 15.443 45.6 16.597 ;
     RECT  59.64 15.443 59.832 16.501 ;
     RECT  76.368 15.491 76.392 15.637 ;
     RECT  31.08 15.683 32.256 16.019 ;
     RECT  37.08 15.781 38.304 16.211 ;
     RECT  4.056 15.973 5.04 16.835 ;
     RECT  31.08 16.019 33.096 16.501 ;
     RECT  36.408 16.211 38.304 16.405 ;
     RECT  78.888 16.259 80.448 17.075 ;
     RECT  22.968 16.261 24 17.171 ;
     RECT  2.712 16.403 4.032 20.003 ;
     RECT  36.408 16.405 38.064 16.499 ;
     RECT  42.6 16.451 42.84 17.557 ;
     RECT  36.36 16.499 38.064 17.077 ;
     RECT  31.08 16.501 33.648 17.075 ;
     RECT  33.672 16.501 34.656 17.075 ;
     RECT  11.784 16.885 13.056 17.075 ;
     RECT  47.4 17.029 48.864 17.605 ;
     RECT  11.784 17.075 13.2 19.813 ;
     RECT  31.08 17.075 33.048 17.077 ;
     RECT  78.888 17.075 81.024 17.269 ;
     RECT  31.08 17.077 32.16 17.891 ;
     RECT  32.184 17.077 33.048 17.891 ;
     RECT  36.36 17.077 37.632 17.989 ;
     RECT  59.832 17.077 60.96 17.219 ;
     RECT  45.912 17.219 47.376 18.469 ;
     RECT  59.832 17.219 61.8 18.037 ;
     RECT  29.712 17.267 31.056 18.467 ;
     RECT  79.608 17.269 81.024 18.179 ;
     RECT  29.088 17.459 29.232 18.181 ;
     RECT  47.592 17.605 48.864 18.035 ;
     RECT  57.384 17.605 58.752 20.053 ;
     RECT  31.08 17.891 31.32 18.421 ;
     RECT  33.024 17.891 33.048 18.565 ;
     RECT  36.456 17.989 37.632 18.085 ;
     RECT  47.592 18.035 49.056 18.659 ;
     RECT  60.744 18.037 61.8 18.421 ;
     RECT  27.816 18.181 29.232 18.995 ;
     RECT  8.112 18.229 9.36 19.477 ;
     RECT  36.456 18.419 37.824 18.611 ;
     RECT  4.056 18.565 5.376 19.379 ;
     RECT  5.88 18.611 5.976 19.669 ;
     RECT  36.456 18.611 37.872 19.859 ;
     RECT  47.4 18.659 49.056 18.899 ;
     RECT  60.504 18.707 61.68 25.715 ;
     RECT  46.44 18.899 49.056 19.285 ;
     RECT  46.44 19.285 48.864 19.715 ;
     RECT  73.8 19.379 73.848 20.725 ;
     RECT  44.328 19.429 45.6 19.717 ;
     RECT  6.408 19.669 7.8 20.195 ;
     RECT  45.912 19.715 48.864 20.005 ;
     RECT  11.784 19.813 13.104 19.955 ;
     RECT  22.824 19.813 24 20.291 ;
     RECT  36.456 19.859 38.544 20.533 ;
     RECT  44.616 19.859 45.6 21.205 ;
     RECT  11.784 19.955 13.2 21.493 ;
     RECT  8.952 20.003 9.384 21.109 ;
     RECT  82.656 20.003 83.4 20.965 ;
     RECT  45.912 20.005 46.896 21.061 ;
     RECT  46.92 20.005 48.864 20.149 ;
     RECT  57.432 20.053 58.752 20.629 ;
     RECT  47.736 20.149 48.864 20.291 ;
     RECT  79.608 20.197 80.784 20.725 ;
     RECT  47.544 20.291 48.864 20.339 ;
     RECT  47.544 20.339 49.008 21.397 ;
     RECT  37.08 20.533 38.544 21.107 ;
     RECT  57.432 20.629 58.656 21.061 ;
     RECT  73.8 20.725 75.168 21.683 ;
     RECT  81.96 20.965 83.4 21.683 ;
     RECT  16.2 21.061 17.616 22.163 ;
     RECT  57.576 21.061 58.656 21.157 ;
     RECT  36.456 21.107 38.544 21.635 ;
     RECT  8.952 21.251 9.432 22.741 ;
     RECT  44.232 21.347 45.6 21.731 ;
     RECT  47.544 21.397 48.96 21.637 ;
     RECT  36.36 21.635 38.544 21.877 ;
     RECT  47.784 21.637 48.96 22.405 ;
     RECT  78.888 21.683 80.16 22.211 ;
     RECT  43.8 21.731 43.992 22.933 ;
     RECT  36.36 21.877 37.536 22.739 ;
     RECT  37.56 21.877 38.544 22.597 ;
     RECT  16.2 22.163 18.192 23.317 ;
     RECT  47.784 22.405 48.768 23.123 ;
     RECT  29.712 22.741 30.768 23.269 ;
     RECT  68.232 22.741 69.216 24.085 ;
     RECT  45.912 22.979 47.328 23.171 ;
     RECT  47.784 23.123 49.104 23.269 ;
     RECT  47.976 23.269 49.104 24.131 ;
     RECT  30.6 23.315 30.792 23.605 ;
     RECT  16.2 23.317 17.664 24.371 ;
     RECT  34.176 23.363 34.56 23.845 ;
     RECT  13.608 23.413 14.832 23.795 ;
     RECT  14.856 23.413 16.176 23.795 ;
     RECT  30.6 23.605 31.872 24.419 ;
     RECT  73.8 23.701 74.928 23.893 ;
     RECT  13.608 23.795 16.176 23.893 ;
     RECT  33.528 23.845 34.56 24.323 ;
     RECT  13.608 23.893 14.736 24.899 ;
     RECT  14.76 23.893 16.176 24.899 ;
     RECT  73.8 23.893 74.832 24.899 ;
     RECT  47.688 24.131 49.104 25.139 ;
     RECT  37.032 24.325 38.496 25.141 ;
     RECT  59.304 24.611 60.48 25.571 ;
     RECT  67.512 24.659 69.216 25.765 ;
     RECT  13.608 24.899 16.176 26.101 ;
     RECT  73.8 24.899 74.928 26.099 ;
     RECT  43.896 25.045 45.312 25.621 ;
     RECT  47.592 25.139 49.104 26.245 ;
     RECT  37.08 25.141 38.496 25.237 ;
     RECT  37.176 25.237 38.496 25.621 ;
     RECT  35.256 25.283 36.336 26.819 ;
     RECT  58.68 25.571 60.48 25.573 ;
     RECT  58.68 25.573 59.856 26.965 ;
     RECT  37.272 25.621 38.496 25.763 ;
     RECT  69.24 25.669 70.656 26.243 ;
     RECT  44.52 25.715 45.6 26.243 ;
     RECT  60.504 25.715 61.8 27.347 ;
     RECT  36.456 25.763 38.496 26.389 ;
     RECT  67.512 25.765 68.64 28.547 ;
     RECT  73.8 26.099 75.216 28.931 ;
     RECT  13.608 26.101 14.784 26.291 ;
     RECT  14.808 26.101 16.176 26.677 ;
     RECT  32.4 26.243 32.424 27.301 ;
     RECT  44.04 26.243 45.6 27.541 ;
     RECT  47.592 26.245 48.624 27.349 ;
     RECT  13.512 26.291 14.784 27.059 ;
     RECT  36.456 26.389 38.352 26.773 ;
     RECT  46.392 26.437 47.568 28.357 ;
     RECT  15.144 26.677 16.176 28.403 ;
     RECT  29.712 26.771 30.768 27.877 ;
     RECT  36.456 26.773 37.68 26.917 ;
     RECT  35.112 26.819 36.336 28.789 ;
     RECT  13.512 27.059 15.12 27.301 ;
     RECT  34.224 27.059 34.272 27.301 ;
     RECT  18.912 27.109 19.968 27.971 ;
     RECT  19.992 27.109 21.12 27.491 ;
     RECT  16.392 27.205 17.616 27.827 ;
     RECT  11.832 27.251 13.2 30.181 ;
     RECT  37.128 27.251 38.496 28.645 ;
     RECT  13.656 27.301 15.12 28.403 ;
     RECT  32.4 27.301 33.024 27.397 ;
     RECT  33.048 27.301 34.272 27.587 ;
     RECT  60.456 27.347 61.8 28.451 ;
     RECT  32.4 27.397 32.928 27.445 ;
     RECT  30.792 27.445 32.208 27.779 ;
     RECT  19.992 27.491 21.408 27.971 ;
     RECT  33.048 27.587 34.416 28.307 ;
     RECT  5.136 27.779 5.856 28.981 ;
     RECT  16.2 27.827 17.616 28.547 ;
     RECT  69.24 27.877 70.752 28.547 ;
     RECT  70.776 27.877 72.192 28.259 ;
     RECT  63 28.213 64.416 28.355 ;
     RECT  32.952 28.307 34.416 28.643 ;
     RECT  62.952 28.355 64.416 28.931 ;
     RECT  13.656 28.403 13.992 28.453 ;
     RECT  15.648 28.403 16.176 28.453 ;
     RECT  15.648 28.453 16.032 29.461 ;
     RECT  37.176 28.645 38.496 28.979 ;
     RECT  64.44 28.645 65.904 28.931 ;
     RECT  35.208 28.789 36.336 29.221 ;
     RECT  62.952 28.931 63.864 30.181 ;
     RECT  74.688 28.931 75.216 29.029 ;
     RECT  27.912 28.933 29.088 28.981 ;
     RECT  65.928 29.027 67.2 29.459 ;
     RECT  46.392 29.075 47.568 30.469 ;
     RECT  13.512 29.123 13.992 30.565 ;
     RECT  35.208 29.221 36.24 29.317 ;
     RECT  29.712 29.363 30.696 30.037 ;
     RECT  66.768 29.459 67.2 30.181 ;
     RECT  15.648 29.461 15.984 29.893 ;
     RECT  25.176 29.507 25.416 30.661 ;
     RECT  27.912 29.699 29.232 33.829 ;
     RECT  29.712 30.037 30.768 30.275 ;
     RECT  14.424 30.565 15.648 30.611 ;
     RECT  25.176 30.661 26.736 30.709 ;
     RECT  26.76 30.661 27.888 30.757 ;
     RECT  25.176 30.709 26.592 31.907 ;
     RECT  74.712 30.709 75.744 31.955 ;
     RECT  47.592 30.755 48.576 31.859 ;
     RECT  5.88 30.757 6.864 31.381 ;
     RECT  10.44 30.757 11.808 31.379 ;
     RECT  26.856 30.757 27.888 30.995 ;
     RECT  58.632 30.803 59.616 32.003 ;
     RECT  16.2 30.851 16.584 32.197 ;
     RECT  26.712 30.995 27.888 32.147 ;
     RECT  19.944 31.237 21.408 32.531 ;
     RECT  11.832 31.379 13.2 32.437 ;
     RECT  78.888 31.667 79.8 32.341 ;
     RECT  47.592 31.859 48.672 32.531 ;
     RECT  25.176 31.907 26.688 32.147 ;
     RECT  58.44 32.003 59.616 35.123 ;
     RECT  25.176 32.147 25.608 32.341 ;
     RECT  25.224 32.341 25.608 33.013 ;
     RECT  78.888 32.341 80.064 35.939 ;
     RECT  33.72 32.389 34.8 33.539 ;
     RECT  66.768 32.435 67.2 32.437 ;
     RECT  12.168 32.437 13.2 34.259 ;
     RECT  66.168 32.437 67.2 34.165 ;
     RECT  72.912 32.437 74.208 33.875 ;
     RECT  47.592 32.531 48.96 32.579 ;
     RECT  47.592 32.579 49.008 32.963 ;
     RECT  47.592 32.963 49.056 34.597 ;
     RECT  55.368 32.963 56.4 37.091 ;
     RECT  4.68 33.013 5.856 33.541 ;
     RECT  67.512 33.299 67.608 34.741 ;
     RECT  34.032 33.539 34.8 34.165 ;
     RECT  23.712 33.635 24 34.741 ;
     RECT  62.952 33.637 64.416 34.883 ;
     RECT  82.104 34.213 83.4 34.355 ;
     RECT  44.04 34.355 45.504 34.499 ;
     RECT  66.168 34.403 67.2 36.899 ;
     RECT  43.992 34.499 45.504 34.739 ;
     RECT  47.88 34.597 49.056 35.939 ;
     RECT  46.728 34.643 47.856 34.931 ;
     RECT  43.992 34.739 44.04 35.989 ;
     RECT  21.432 34.741 22.752 35.363 ;
     RECT  22.776 34.741 24 35.363 ;
     RECT  29.712 35.219 30.72 35.939 ;
     RECT  23.856 35.363 24 35.461 ;
     RECT  40.728 35.363 42.096 36.275 ;
     RECT  19.992 35.413 21.408 35.891 ;
     RECT  5.88 35.939 5.928 36.997 ;
     RECT  29.712 35.939 30.816 36.563 ;
     RECT  78.696 35.939 80.064 36.323 ;
     RECT  26.808 36.037 27.888 37.093 ;
     RECT  65.064 36.277 66.144 36.419 ;
     RECT  78.312 36.323 80.064 36.997 ;
     RECT  60.168 36.853 61.488 37.091 ;
     RECT  67.104 36.899 67.2 37.093 ;
     RECT  5.88 36.997 6.912 37.859 ;
     RECT  78.312 36.997 79.824 37.667 ;
     RECT  53.64 37.091 55.104 37.187 ;
     RECT  55.128 37.091 56.4 37.187 ;
     RECT  26.808 38.099 27.888 39.781 ;
     RECT  24.312 38.147 25.92 39.205 ;
     RECT  52.488 38.723 53.616 40.309 ;
     RECT  42.504 38.771 43.488 40.451 ;
     RECT  56.808 38.771 56.856 39.109 ;
     RECT  4.632 39.061 5.856 39.923 ;
     RECT  56.808 39.109 58.128 39.395 ;
     RECT  24.456 39.205 25.92 41.459 ;
     RECT  56.808 39.395 57.48 40.885 ;
     RECT  17.016 39.877 18.288 43.043 ;
     RECT  54.312 40.355 54.6 41.029 ;
     RECT  42.48 40.451 43.488 40.789 ;
     RECT  39.888 40.691 40.032 40.931 ;
     RECT  2.712 40.741 4.176 40.933 ;
     RECT  42.408 40.789 43.488 41.075 ;
     RECT  39.888 40.931 40.2 41.605 ;
     RECT  2.808 40.933 4.176 41.699 ;
     RECT  54.312 41.029 55.728 41.459 ;
     RECT  56.304 41.459 56.4 42.421 ;
     RECT  40.92 41.557 42.384 42.419 ;
     RECT  39.048 41.605 40.2 45.973 ;
     RECT  2.712 41.699 4.176 43.045 ;
     RECT  81 41.795 81.48 42.181 ;
     RECT  27.72 41.939 28.704 43.955 ;
     RECT  8.856 41.989 10.224 46.355 ;
     RECT  6.408 42.035 7.392 42.803 ;
     RECT  81 42.181 82.224 42.851 ;
     RECT  82.248 42.181 83.4 42.851 ;
     RECT  66.72 42.419 67.2 42.709 ;
     RECT  65.976 42.709 67.2 42.851 ;
     RECT  5.88 42.803 7.392 43.811 ;
     RECT  40.512 43.331 40.92 44.629 ;
     RECT  2.712 43.619 3.84 44.483 ;
     RECT  7.248 43.811 7.392 43.861 ;
     RECT  21.48 43.907 21.576 44.917 ;
     RECT  52.488 43.907 53.616 47.461 ;
     RECT  27.72 43.955 29.184 44.245 ;
     RECT  10.248 44.053 11.424 45.493 ;
     RECT  27.816 44.245 29.184 45.059 ;
     RECT  2.712 44.483 4.176 51.109 ;
     RECT  72.912 44.483 73.56 45.541 ;
     RECT  24.552 44.723 25.92 45.923 ;
     RECT  27.72 45.059 29.184 45.157 ;
     RECT  34.656 45.155 34.8 46.549 ;
     RECT  22.824 45.157 24 45.587 ;
     RECT  27.72 45.157 29.088 48.997 ;
     RECT  38.4 45.539 38.448 46.837 ;
     RECT  48.432 45.539 48.576 46.597 ;
     RECT  73.512 45.541 73.56 45.685 ;
     RECT  22.728 45.587 24 45.683 ;
     RECT  21.48 45.683 24 46.693 ;
     RECT  10.248 45.731 11.52 46.355 ;
     RECT  53.64 45.731 54.672 47.317 ;
     RECT  40.512 45.779 41.064 46.933 ;
     RECT  63.048 46.163 63.864 46.357 ;
     RECT  8.856 46.355 9.624 47.077 ;
     RECT  63.048 46.357 64.32 47.747 ;
     RECT  46.68 46.597 47.76 47.029 ;
     RECT  22.2 46.693 24 46.837 ;
     RECT  55.272 46.693 56.4 48.229 ;
     RECT  67.608 46.789 69.072 46.883 ;
     RECT  69.096 46.789 70.272 46.931 ;
     RECT  22.632 46.837 24 47.123 ;
     RECT  36.936 46.837 38.448 47.845 ;
     RECT  32.4 46.931 32.424 47.125 ;
     RECT  47.784 46.931 48.768 47.507 ;
     RECT  21.096 47.027 22.176 47.171 ;
     RECT  32.136 47.125 32.424 48.325 ;
     RECT  20.76 47.171 22.176 47.555 ;
     RECT  39.048 47.363 40.2 50.389 ;
     RECT  52.488 47.461 53.568 48.421 ;
     RECT  47.736 47.507 48.768 47.795 ;
     RECT  19.848 47.555 22.176 48.421 ;
     RECT  29.712 47.701 31.008 48.421 ;
     RECT  31.032 47.701 32.112 48.133 ;
     RECT  63.048 47.747 64.344 47.939 ;
     RECT  47.736 47.795 49.008 49.477 ;
     RECT  46.728 47.843 47.712 50.773 ;
     RECT  54.216 47.891 55.248 48.611 ;
     RECT  62.112 47.939 64.344 48.325 ;
     RECT  62.112 48.325 64.416 49.429 ;
     RECT  4.2 48.421 5.328 48.995 ;
     RECT  19.848 48.421 21.888 48.853 ;
     RECT  53.832 48.611 55.248 49.381 ;
     RECT  64.488 48.805 65.52 49.667 ;
     RECT  19.944 48.853 21.888 48.901 ;
     RECT  17.16 48.901 18.288 50.771 ;
     RECT  19.944 48.901 20.928 49.043 ;
     RECT  72 48.947 72.336 50.437 ;
     RECT  4.2 48.995 4.296 50.245 ;
     RECT  20.952 48.995 22.176 49.043 ;
     RECT  6.12 48.997 7.392 49.813 ;
     RECT  27.72 48.997 28.992 49.139 ;
     RECT  27.72 49.139 29.136 51.637 ;
     RECT  52.488 49.139 53.568 51.253 ;
     RECT  55.272 49.187 56.304 50.483 ;
     RECT  40.512 49.237 41.616 50.437 ;
     RECT  41.64 49.237 43.056 50.195 ;
     RECT  53.832 49.381 54.816 51.685 ;
     RECT  63 49.429 64.416 49.571 ;
     RECT  29.712 49.475 30.96 51.781 ;
     RECT  62.112 49.571 64.416 50.819 ;
     RECT  64.488 49.667 64.968 50.533 ;
     RECT  6.36 49.813 7.392 52.211 ;
     RECT  41.64 50.195 42.024 50.533 ;
     RECT  55.272 50.483 56.4 51.733 ;
     RECT  13.608 50.627 13.656 50.917 ;
     RECT  34.08 50.819 34.224 51.589 ;
     RECT  40.512 50.819 41.616 51.923 ;
     RECT  62.112 50.819 63.336 50.869 ;
     RECT  62.112 50.869 63.312 51.251 ;
     RECT  13.608 50.917 15.072 52.259 ;
     RECT  70.728 51.253 72 52.643 ;
     RECT  19.896 51.301 21.024 52.549 ;
     RECT  11.16 51.541 12.528 52.163 ;
     RECT  33.192 51.589 34.224 51.781 ;
     RECT  47.928 51.635 49.008 51.827 ;
     RECT  27.72 51.637 29.088 52.885 ;
     RECT  55.272 51.733 56.256 52.549 ;
     RECT  29.832 51.781 30.96 51.971 ;
     RECT  47.928 51.827 49.056 53.603 ;
     RECT  32.472 51.875 33.888 51.923 ;
     RECT  40.512 51.923 41.112 52.645 ;
     RECT  46.728 51.923 47.712 53.029 ;
     RECT  29.712 51.971 30.96 61.043 ;
     RECT  9.864 52.021 11.136 52.163 ;
     RECT  25.272 52.309 26.64 52.693 ;
     RECT  60.456 52.643 61.8 54.085 ;
     RECT  70.992 52.643 72 53.557 ;
     RECT  41.064 52.787 41.112 53.171 ;
     RECT  8.856 53.075 9.84 54.371 ;
     RECT  31.032 53.123 32.112 54.179 ;
     RECT  40.512 53.171 41.112 54.085 ;
     RECT  46.728 53.363 47.712 53.603 ;
     RECT  53.784 53.411 55.2 55.477 ;
     RECT  71.016 53.557 72 53.651 ;
     RECT  25.272 53.603 26.448 55.285 ;
     RECT  47.88 53.603 49.056 56.821 ;
     RECT  71.016 53.651 72.432 54.613 ;
     RECT  35.256 53.843 36.288 56.293 ;
     RECT  32.712 54.085 34.224 55.237 ;
     RECT  40.512 54.085 42.048 54.277 ;
     RECT  13.608 54.133 15.072 54.179 ;
     RECT  55.272 54.227 56.4 57.445 ;
     RECT  41.064 54.277 42.048 54.419 ;
     RECT  8.856 54.371 9.72 55.237 ;
     RECT  40.512 54.419 42.048 54.659 ;
     RECT  71.256 54.613 72.432 55.907 ;
     RECT  40.512 54.659 40.632 55.909 ;
     RECT  82.056 54.709 83.4 56.483 ;
     RECT  6.648 54.755 7.68 55.717 ;
     RECT  77.472 54.755 78 55.957 ;
     RECT  60.72 55.139 61.248 55.957 ;
     RECT  53.784 55.477 54.816 55.813 ;
     RECT  37.512 55.811 38.496 56.917 ;
     RECT  52.056 55.811 53.376 56.387 ;
     RECT  53.784 55.813 54.768 56.197 ;
     RECT  78.312 55.861 79.392 57.059 ;
     RECT  8.856 55.907 8.904 57.157 ;
     RECT  59.448 55.957 61.248 56.099 ;
     RECT  45.912 56.005 47.184 56.339 ;
     RECT  60.96 56.099 61.248 56.389 ;
     RECT  65.544 56.389 67.056 57.829 ;
     RECT  67.512 56.389 68.928 56.869 ;
     RECT  27.72 56.483 28.896 56.723 ;
     RECT  27.72 56.723 29.136 57.781 ;
     RECT  47.88 56.821 49.008 56.963 ;
     RECT  33.48 56.867 34.704 58.213 ;
     RECT  67.512 56.869 68.688 58.355 ;
     RECT  47.88 56.963 49.536 56.965 ;
     RECT  48.504 56.965 49.536 60.227 ;
     RECT  6.624 57.059 6.96 58.405 ;
     RECT  25.272 57.299 26.448 57.683 ;
     RECT  35.304 57.299 36.288 57.395 ;
     RECT  43.872 57.299 44.688 57.493 ;
     RECT  35.256 57.395 36.288 58.837 ;
     RECT  43.656 57.493 44.688 60.563 ;
     RECT  25.032 57.683 26.496 58.741 ;
     RECT  27.72 57.781 28.752 57.923 ;
     RECT  65.544 57.829 66.72 57.875 ;
     RECT  49.56 57.875 51 65.173 ;
     RECT  65.064 57.875 66.72 58.645 ;
     RECT  27.72 57.923 29.136 61.669 ;
     RECT  55.272 58.211 56.4 59.221 ;
     RECT  33.48 58.213 34.512 58.403 ;
     RECT  33.48 58.403 34.608 58.547 ;
     RECT  5.448 58.405 6.96 59.029 ;
     RECT  62.112 58.405 63.408 59.459 ;
     RECT  41.016 58.451 41.4 59.509 ;
     RECT  37.512 58.499 38.496 60.421 ;
     RECT  33.48 58.547 34.704 59.941 ;
     RECT  65.064 58.645 66.48 59.315 ;
     RECT  25.032 58.741 26.208 59.315 ;
     RECT  39.048 58.787 40.2 60.325 ;
     RECT  5.448 59.029 6.912 59.221 ;
     RECT  19.848 59.125 20.976 61.331 ;
     RECT  5.592 59.221 6.912 60.421 ;
     RECT  17.16 59.221 18.6 59.507 ;
     RECT  25.032 59.315 26.496 59.747 ;
     RECT  65.064 59.315 65.592 59.749 ;
     RECT  14.28 59.363 14.472 60.757 ;
     RECT  62.112 59.459 62.904 60.949 ;
     RECT  41.016 59.509 42.432 59.651 ;
     RECT  42.456 59.509 43.632 59.651 ;
     RECT  41.016 59.651 41.304 59.845 ;
     RECT  51.312 59.797 52.704 62.341 ;
     RECT  55.272 59.843 56.4 62.773 ;
     RECT  56.712 60.373 57.888 64.259 ;
     RECT  35.352 60.419 36.384 60.467 ;
     RECT  5.592 60.421 6.864 61.525 ;
     RECT  35.352 60.467 36.816 62.629 ;
     RECT  65.064 60.467 65.592 60.997 ;
     RECT  43.776 60.563 44.688 61.045 ;
     RECT  46.344 60.661 47.424 60.899 ;
     RECT  76.968 60.805 78 60.947 ;
     RECT  38.52 60.899 39.792 62.003 ;
     RECT  46.344 60.899 47.856 61.283 ;
     RECT  30.984 60.901 32.352 60.997 ;
     RECT  77.136 60.947 78 61.765 ;
     RECT  80.184 60.949 81.6 62.195 ;
     RECT  65.064 60.997 66.096 61.619 ;
     RECT  66.12 60.997 67.2 61.619 ;
     RECT  19.848 61.331 21.216 62.147 ;
     RECT  33.48 61.523 34.8 62.629 ;
     RECT  27.912 61.669 29.136 62.003 ;
     RECT  32.376 61.715 33.456 62.723 ;
     RECT  8.856 61.765 10.08 64.405 ;
     RECT  63.912 61.765 65.04 63.251 ;
     RECT  40.512 61.955 41.064 63.205 ;
     RECT  27.72 62.003 29.136 67.811 ;
     RECT  48.624 62.051 49.536 63.205 ;
     RECT  59.592 62.101 61.008 62.675 ;
     RECT  5.592 62.435 6.864 63.829 ;
     RECT  33.48 62.629 34.704 63.011 ;
     RECT  35.352 62.629 36.48 63.347 ;
     RECT  51.768 62.675 52.752 64.165 ;
     RECT  33.024 62.723 33.456 63.397 ;
     RECT  44.136 62.723 45.264 63.347 ;
     RECT  33.48 63.011 34.8 65.941 ;
     RECT  57.912 63.011 57.96 64.259 ;
     RECT  55.272 63.059 56.4 63.923 ;
     RECT  48.024 63.205 49.536 63.541 ;
     RECT  64.464 63.251 65.04 63.733 ;
     RECT  35.208 63.347 36.48 63.685 ;
     RECT  44.136 63.347 45.6 64.357 ;
     RECT  61.248 63.347 61.8 64.309 ;
     RECT  48.024 63.541 49.008 63.731 ;
     RECT  35.208 63.685 36.384 64.357 ;
     RECT  48.024 63.731 49.536 64.067 ;
     RECT  5.592 63.829 6.768 64.787 ;
     RECT  54.84 63.923 56.4 64.933 ;
     RECT  56.712 64.259 57.96 64.309 ;
     RECT  51.672 64.307 52.752 65.509 ;
     RECT  56.712 64.309 57.936 65.365 ;
     RECT  31.512 64.357 33.024 64.979 ;
     RECT  35.352 64.357 36.384 64.403 ;
     RECT  44.184 64.357 45.6 65.077 ;
     RECT  35.352 64.403 36.816 65.075 ;
     RECT  8.856 64.405 9.888 64.643 ;
     RECT  8.712 64.643 9.888 66.755 ;
     RECT  39.144 64.645 40.2 65.603 ;
     RECT  5.592 64.787 6.864 66.755 ;
     RECT  64.512 64.787 65.04 66.133 ;
     RECT  54.888 64.933 56.4 66.277 ;
     RECT  61.248 65.027 61.8 66.325 ;
     RECT  35.304 65.075 36.816 66.229 ;
     RECT  44.184 65.077 45.312 65.651 ;
     RECT  49.56 65.173 50.88 65.365 ;
     RECT  49.56 65.365 50.64 65.555 ;
     RECT  56.712 65.365 57.84 66.277 ;
     RECT  49.56 65.555 50.736 66.467 ;
     RECT  39.048 65.603 40.2 74.147 ;
     RECT  44.448 65.651 45.312 65.653 ;
     RECT  44.448 65.653 45.216 66.661 ;
     RECT  33.816 65.941 34.8 66.083 ;
     RECT  33.48 66.083 34.8 70.403 ;
     RECT  19.848 66.179 20.568 67.669 ;
     RECT  55.176 66.277 56.4 66.419 ;
     RECT  64.512 66.323 65.04 66.421 ;
     RECT  61.248 66.325 61.68 66.467 ;
     RECT  56.904 66.419 57.936 66.755 ;
     RECT  63.816 66.421 65.04 66.611 ;
     RECT  49.56 66.467 50.832 66.707 ;
     RECT  61.248 66.467 61.8 66.469 ;
     RECT  60.744 66.469 61.8 66.707 ;
     RECT  35.304 66.611 36.336 67.283 ;
     RECT  64.992 66.611 65.04 67.333 ;
     RECT  49.56 66.707 51 66.757 ;
     RECT  60.72 66.707 61.8 67.525 ;
     RECT  8.712 66.755 10.08 68.003 ;
     RECT  56.904 66.755 58.032 67.573 ;
     RECT  49.656 66.757 51 66.995 ;
     RECT  49.56 66.995 51 68.341 ;
     RECT  82.344 67.237 83.4 68.339 ;
     RECT  35.112 67.283 36.336 67.907 ;
     RECT  44.472 67.379 45.6 68.629 ;
     RECT  60.72 67.525 60.96 67.669 ;
     RECT  57 67.573 58.032 67.715 ;
     RECT  19.848 67.669 20.976 68.195 ;
     RECT  58.056 67.669 59.52 69.155 ;
     RECT  59.544 67.669 60.96 67.715 ;
     RECT  56.952 67.715 58.032 68.579 ;
     RECT  59.544 67.715 61.68 68.773 ;
     RECT  12.12 67.765 13.2 68.243 ;
     RECT  27.72 67.811 29.4 68.773 ;
     RECT  67.512 67.957 68.832 68.533 ;
     RECT  19.656 68.195 20.976 71.221 ;
     RECT  49.56 68.341 50.688 69.827 ;
     RECT  51.672 68.387 52.656 70.835 ;
     RECT  67.512 68.533 68.736 68.917 ;
     RECT  56.904 68.579 58.032 68.963 ;
     RECT  68.76 68.579 69.792 69.011 ;
     RECT  59.544 68.773 60.912 69.155 ;
     RECT  31.944 68.915 33.024 69.731 ;
     RECT  72.912 68.915 73.176 69.973 ;
     RECT  67.608 68.917 68.736 69.203 ;
     RECT  56.808 68.963 58.032 70.883 ;
     RECT  68.76 69.011 70.08 69.203 ;
     RECT  60.624 69.155 60.912 69.205 ;
     RECT  67.608 69.203 67.8 70.357 ;
     RECT  60.624 69.205 60.816 69.301 ;
     RECT  62.112 69.493 63.264 72.707 ;
     RECT  31.944 69.731 33.456 70.163 ;
     RECT  49.56 69.827 51 72.179 ;
     RECT  14.232 70.117 15.456 71.507 ;
     RECT  33.552 70.403 34.8 70.645 ;
     RECT  33.576 70.645 34.8 71.989 ;
     RECT  29.832 70.693 31.344 71.555 ;
     RECT  51.312 70.835 52.656 74.339 ;
     RECT  56.712 70.883 58.032 72.035 ;
     RECT  14.232 71.507 15.144 72.179 ;
     RECT  27.72 71.797 28.896 73.523 ;
     RECT  69.504 71.891 70.08 72.757 ;
     RECT  33.768 71.989 34.8 72.229 ;
     RECT  55.176 71.989 56.4 72.133 ;
     RECT  15.12 72.179 15.144 72.325 ;
     RECT  67.512 72.757 68.832 72.949 ;
     RECT  68.856 72.757 70.08 73.237 ;
     RECT  67.512 72.949 68.736 73.283 ;
     RECT  68.904 73.237 70.08 73.379 ;
     RECT  67.512 73.283 68.88 74.723 ;
     RECT  18.912 73.811 19.656 74.629 ;
     RECT  39.024 74.147 40.2 74.581 ;
     RECT  55.176 74.339 56.4 74.723 ;
     RECT  38.808 74.581 40.2 75.059 ;
     RECT  41.16 74.581 42.144 74.867 ;
     RECT  18.912 74.629 19.92 74.819 ;
     RECT  33.768 74.723 34.8 75.395 ;
  END
END qfd_tt_ctlm_dv_wtn
END LIBRARY
